VERSION 5.8 ;
BUSBITCHARS "[]" ;
DIVIDERCHAR "/" ;
UNITS
    DATABASE MICRONS 1000 ;
END UNITS

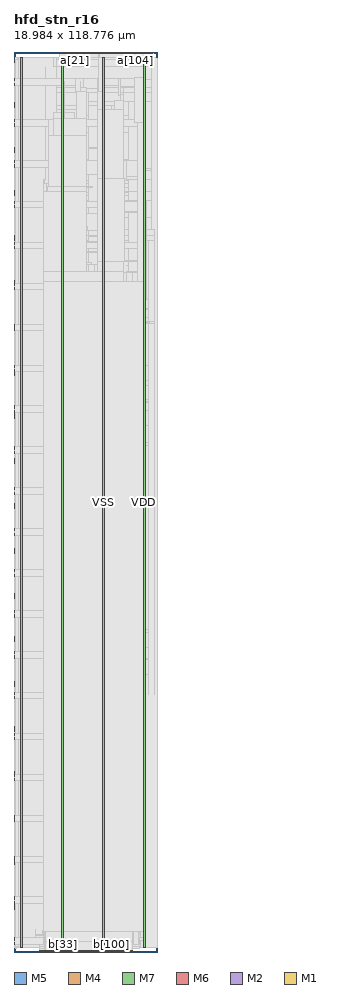
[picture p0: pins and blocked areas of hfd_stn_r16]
MACRO hfd_stn_r16
  FOREIGN hfd_stn_r16 0 0 ;
  CLASS BLOCK ;
  SIZE 18.984 BY 118.776 ;
  PIN a[0]
    DIRECTION INPUT ;
    USE SIGNAL ;
    PORT
      LAYER M5 ;
        RECT  6 118.584 6.024 118.776 ;
    END
  END a[0]
  PIN a[100]
    DIRECTION INPUT ;
    USE SIGNAL ;
    PORT
      LAYER M5 ;
        RECT  15.6 118.584 15.624 118.776 ;
    END
  END a[100]
  PIN a[101]
    DIRECTION INPUT ;
    USE SIGNAL ;
    PORT
      LAYER M5 ;
        RECT  15.696 118.584 15.72 118.776 ;
    END
  END a[101]
  PIN a[102]
    DIRECTION INPUT ;
    USE SIGNAL ;
    PORT
      LAYER M5 ;
        RECT  15.792 118.584 15.816 118.776 ;
    END
  END a[102]
  PIN a[103]
    DIRECTION INPUT ;
    USE SIGNAL ;
    PORT
      LAYER M5 ;
        RECT  15.888 118.584 15.912 118.776 ;
    END
  END a[103]
  PIN a[104]
    DIRECTION INPUT ;
    USE SIGNAL ;
    PORT
      LAYER M5 ;
        RECT  15.984 118.584 16.008 118.776 ;
    END
  END a[104]
  PIN a[105]
    DIRECTION INPUT ;
    USE SIGNAL ;
    PORT
      LAYER M5 ;
        RECT  16.08 118.584 16.104 118.776 ;
    END
  END a[105]
  PIN a[106]
    DIRECTION INPUT ;
    USE SIGNAL ;
    PORT
      LAYER M5 ;
        RECT  16.176 118.584 16.2 118.776 ;
    END
  END a[106]
  PIN a[107]
    DIRECTION INPUT ;
    USE SIGNAL ;
    PORT
      LAYER M5 ;
        RECT  16.272 118.584 16.296 118.776 ;
    END
  END a[107]
  PIN a[108]
    DIRECTION INPUT ;
    USE SIGNAL ;
    PORT
      LAYER M5 ;
        RECT  16.368 118.584 16.392 118.776 ;
    END
  END a[108]
  PIN a[109]
    DIRECTION INPUT ;
    USE SIGNAL ;
    PORT
      LAYER M5 ;
        RECT  16.464 118.584 16.488 118.776 ;
    END
  END a[109]
  PIN a[10]
    DIRECTION INPUT ;
    USE SIGNAL ;
    PORT
      LAYER M5 ;
        RECT  6.96 118.584 6.984 118.776 ;
    END
  END a[10]
  PIN a[110]
    DIRECTION INPUT ;
    USE SIGNAL ;
    PORT
      LAYER M5 ;
        RECT  16.56 118.584 16.584 118.776 ;
    END
  END a[110]
  PIN a[111]
    DIRECTION INPUT ;
    USE SIGNAL ;
    PORT
      LAYER M5 ;
        RECT  16.656 118.584 16.68 118.776 ;
    END
  END a[111]
  PIN a[112]
    DIRECTION INPUT ;
    USE SIGNAL ;
    PORT
      LAYER M5 ;
        RECT  16.752 118.584 16.776 118.776 ;
    END
  END a[112]
  PIN a[113]
    DIRECTION INPUT ;
    USE SIGNAL ;
    PORT
      LAYER M5 ;
        RECT  16.848 118.584 16.872 118.776 ;
    END
  END a[113]
  PIN a[114]
    DIRECTION INPUT ;
    USE SIGNAL ;
    PORT
      LAYER M5 ;
        RECT  16.944 118.584 16.968 118.776 ;
    END
  END a[114]
  PIN a[115]
    DIRECTION INPUT ;
    USE SIGNAL ;
    PORT
      LAYER M5 ;
        RECT  17.04 118.584 17.064 118.776 ;
    END
  END a[115]
  PIN a[116]
    DIRECTION INPUT ;
    USE SIGNAL ;
    PORT
      LAYER M5 ;
        RECT  17.136 118.584 17.16 118.776 ;
    END
  END a[116]
  PIN a[117]
    DIRECTION INPUT ;
    USE SIGNAL ;
    PORT
      LAYER M5 ;
        RECT  17.232 118.584 17.256 118.776 ;
    END
  END a[117]
  PIN a[118]
    DIRECTION INPUT ;
    USE SIGNAL ;
    PORT
      LAYER M5 ;
        RECT  17.328 118.584 17.352 118.776 ;
    END
  END a[118]
  PIN a[119]
    DIRECTION INPUT ;
    USE SIGNAL ;
    PORT
      LAYER M5 ;
        RECT  17.424 118.584 17.448 118.776 ;
    END
  END a[119]
  PIN a[11]
    DIRECTION INPUT ;
    USE SIGNAL ;
    PORT
      LAYER M5 ;
        RECT  7.056 118.584 7.08 118.776 ;
    END
  END a[11]
  PIN a[120]
    DIRECTION INPUT ;
    USE SIGNAL ;
    PORT
      LAYER M5 ;
        RECT  17.52 118.584 17.544 118.776 ;
    END
  END a[120]
  PIN a[121]
    DIRECTION INPUT ;
    USE SIGNAL ;
    PORT
      LAYER M5 ;
        RECT  17.616 118.584 17.64 118.776 ;
    END
  END a[121]
  PIN a[122]
    DIRECTION INPUT ;
    USE SIGNAL ;
    PORT
      LAYER M5 ;
        RECT  17.712 118.584 17.736 118.776 ;
    END
  END a[122]
  PIN a[123]
    DIRECTION INPUT ;
    USE SIGNAL ;
    PORT
      LAYER M5 ;
        RECT  17.808 118.584 17.832 118.776 ;
    END
  END a[123]
  PIN a[124]
    DIRECTION INPUT ;
    USE SIGNAL ;
    PORT
      LAYER M5 ;
        RECT  17.904 118.584 17.928 118.776 ;
    END
  END a[124]
  PIN a[125]
    DIRECTION INPUT ;
    USE SIGNAL ;
    PORT
      LAYER M5 ;
        RECT  18 118.584 18.024 118.776 ;
    END
  END a[125]
  PIN a[126]
    DIRECTION INPUT ;
    USE SIGNAL ;
    PORT
      LAYER M5 ;
        RECT  18.096 118.584 18.12 118.776 ;
    END
  END a[126]
  PIN a[127]
    DIRECTION INPUT ;
    USE SIGNAL ;
    PORT
      LAYER M5 ;
        RECT  18.192 118.584 18.216 118.776 ;
    END
  END a[127]
  PIN a[128]
    DIRECTION INPUT ;
    USE SIGNAL ;
    PORT
      LAYER M5 ;
        RECT  18.288 118.584 18.312 118.776 ;
    END
  END a[128]
  PIN a[12]
    DIRECTION INPUT ;
    USE SIGNAL ;
    PORT
      LAYER M5 ;
        RECT  7.152 118.584 7.176 118.776 ;
    END
  END a[12]
  PIN a[13]
    DIRECTION INPUT ;
    USE SIGNAL ;
    PORT
      LAYER M5 ;
        RECT  7.248 118.584 7.272 118.776 ;
    END
  END a[13]
  PIN a[14]
    DIRECTION INPUT ;
    USE SIGNAL ;
    PORT
      LAYER M5 ;
        RECT  7.344 118.584 7.368 118.776 ;
    END
  END a[14]
  PIN a[15]
    DIRECTION INPUT ;
    USE SIGNAL ;
    PORT
      LAYER M5 ;
        RECT  7.44 118.584 7.464 118.776 ;
    END
  END a[15]
  PIN a[16]
    DIRECTION INPUT ;
    USE SIGNAL ;
    PORT
      LAYER M5 ;
        RECT  7.536 118.584 7.56 118.776 ;
    END
  END a[16]
  PIN a[17]
    DIRECTION INPUT ;
    USE SIGNAL ;
    PORT
      LAYER M5 ;
        RECT  7.632 118.584 7.656 118.776 ;
    END
  END a[17]
  PIN a[18]
    DIRECTION INPUT ;
    USE SIGNAL ;
    PORT
      LAYER M5 ;
        RECT  7.728 118.584 7.752 118.776 ;
    END
  END a[18]
  PIN a[19]
    DIRECTION INPUT ;
    USE SIGNAL ;
    PORT
      LAYER M5 ;
        RECT  7.824 118.584 7.848 118.776 ;
    END
  END a[19]
  PIN a[1]
    DIRECTION INPUT ;
    USE SIGNAL ;
    PORT
      LAYER M5 ;
        RECT  6.096 118.584 6.12 118.776 ;
    END
  END a[1]
  PIN a[20]
    DIRECTION INPUT ;
    USE SIGNAL ;
    PORT
      LAYER M5 ;
        RECT  7.92 118.584 7.944 118.776 ;
    END
  END a[20]
  PIN a[21]
    DIRECTION INPUT ;
    USE SIGNAL ;
    PORT
      LAYER M5 ;
        RECT  8.016 118.584 8.04 118.776 ;
    END
  END a[21]
  PIN a[22]
    DIRECTION INPUT ;
    USE SIGNAL ;
    PORT
      LAYER M5 ;
        RECT  8.112 118.584 8.136 118.776 ;
    END
  END a[22]
  PIN a[23]
    DIRECTION INPUT ;
    USE SIGNAL ;
    PORT
      LAYER M5 ;
        RECT  8.208 118.584 8.232 118.776 ;
    END
  END a[23]
  PIN a[24]
    DIRECTION INPUT ;
    USE SIGNAL ;
    PORT
      LAYER M5 ;
        RECT  8.304 118.584 8.328 118.776 ;
    END
  END a[24]
  PIN a[25]
    DIRECTION INPUT ;
    USE SIGNAL ;
    PORT
      LAYER M5 ;
        RECT  8.4 118.584 8.424 118.776 ;
    END
  END a[25]
  PIN a[26]
    DIRECTION INPUT ;
    USE SIGNAL ;
    PORT
      LAYER M5 ;
        RECT  8.496 118.584 8.52 118.776 ;
    END
  END a[26]
  PIN a[27]
    DIRECTION INPUT ;
    USE SIGNAL ;
    PORT
      LAYER M5 ;
        RECT  8.592 118.584 8.616 118.776 ;
    END
  END a[27]
  PIN a[28]
    DIRECTION INPUT ;
    USE SIGNAL ;
    PORT
      LAYER M5 ;
        RECT  8.688 118.584 8.712 118.776 ;
    END
  END a[28]
  PIN a[29]
    DIRECTION INPUT ;
    USE SIGNAL ;
    PORT
      LAYER M5 ;
        RECT  8.784 118.584 8.808 118.776 ;
    END
  END a[29]
  PIN a[2]
    DIRECTION INPUT ;
    USE SIGNAL ;
    PORT
      LAYER M5 ;
        RECT  6.192 118.584 6.216 118.776 ;
    END
  END a[2]
  PIN a[30]
    DIRECTION INPUT ;
    USE SIGNAL ;
    PORT
      LAYER M5 ;
        RECT  8.88 118.584 8.904 118.776 ;
    END
  END a[30]
  PIN a[31]
    DIRECTION INPUT ;
    USE SIGNAL ;
    PORT
      LAYER M5 ;
        RECT  8.976 118.584 9 118.776 ;
    END
  END a[31]
  PIN a[32]
    DIRECTION INPUT ;
    USE SIGNAL ;
    PORT
      LAYER M5 ;
        RECT  9.072 118.584 9.096 118.776 ;
    END
  END a[32]
  PIN a[33]
    DIRECTION INPUT ;
    USE SIGNAL ;
    PORT
      LAYER M5 ;
        RECT  9.168 118.584 9.192 118.776 ;
    END
  END a[33]
  PIN a[34]
    DIRECTION INPUT ;
    USE SIGNAL ;
    PORT
      LAYER M5 ;
        RECT  9.264 118.584 9.288 118.776 ;
    END
  END a[34]
  PIN a[35]
    DIRECTION INPUT ;
    USE SIGNAL ;
    PORT
      LAYER M5 ;
        RECT  9.36 118.584 9.384 118.776 ;
    END
  END a[35]
  PIN a[36]
    DIRECTION INPUT ;
    USE SIGNAL ;
    PORT
      LAYER M5 ;
        RECT  9.456 118.584 9.48 118.776 ;
    END
  END a[36]
  PIN a[37]
    DIRECTION INPUT ;
    USE SIGNAL ;
    PORT
      LAYER M5 ;
        RECT  9.552 118.584 9.576 118.776 ;
    END
  END a[37]
  PIN a[38]
    DIRECTION INPUT ;
    USE SIGNAL ;
    PORT
      LAYER M5 ;
        RECT  9.648 118.584 9.672 118.776 ;
    END
  END a[38]
  PIN a[39]
    DIRECTION INPUT ;
    USE SIGNAL ;
    PORT
      LAYER M5 ;
        RECT  9.744 118.584 9.768 118.776 ;
    END
  END a[39]
  PIN a[3]
    DIRECTION INPUT ;
    USE SIGNAL ;
    PORT
      LAYER M5 ;
        RECT  6.288 118.584 6.312 118.776 ;
    END
  END a[3]
  PIN a[40]
    DIRECTION INPUT ;
    USE SIGNAL ;
    PORT
      LAYER M5 ;
        RECT  9.84 118.584 9.864 118.776 ;
    END
  END a[40]
  PIN a[41]
    DIRECTION INPUT ;
    USE SIGNAL ;
    PORT
      LAYER M5 ;
        RECT  9.936 118.584 9.96 118.776 ;
    END
  END a[41]
  PIN a[42]
    DIRECTION INPUT ;
    USE SIGNAL ;
    PORT
      LAYER M5 ;
        RECT  10.032 118.584 10.056 118.776 ;
    END
  END a[42]
  PIN a[43]
    DIRECTION INPUT ;
    USE SIGNAL ;
    PORT
      LAYER M5 ;
        RECT  10.128 118.584 10.152 118.776 ;
    END
  END a[43]
  PIN a[44]
    DIRECTION INPUT ;
    USE SIGNAL ;
    PORT
      LAYER M5 ;
        RECT  10.224 118.584 10.248 118.776 ;
    END
  END a[44]
  PIN a[45]
    DIRECTION INPUT ;
    USE SIGNAL ;
    PORT
      LAYER M5 ;
        RECT  10.32 118.584 10.344 118.776 ;
    END
  END a[45]
  PIN a[46]
    DIRECTION INPUT ;
    USE SIGNAL ;
    PORT
      LAYER M5 ;
        RECT  10.416 118.584 10.44 118.776 ;
    END
  END a[46]
  PIN a[47]
    DIRECTION INPUT ;
    USE SIGNAL ;
    PORT
      LAYER M5 ;
        RECT  10.512 118.584 10.536 118.776 ;
    END
  END a[47]
  PIN a[48]
    DIRECTION INPUT ;
    USE SIGNAL ;
    PORT
      LAYER M5 ;
        RECT  10.608 118.584 10.632 118.776 ;
    END
  END a[48]
  PIN a[49]
    DIRECTION INPUT ;
    USE SIGNAL ;
    PORT
      LAYER M5 ;
        RECT  10.704 118.584 10.728 118.776 ;
    END
  END a[49]
  PIN a[4]
    DIRECTION INPUT ;
    USE SIGNAL ;
    PORT
      LAYER M5 ;
        RECT  6.384 118.584 6.408 118.776 ;
    END
  END a[4]
  PIN a[50]
    DIRECTION INPUT ;
    USE SIGNAL ;
    PORT
      LAYER M5 ;
        RECT  10.8 118.584 10.824 118.776 ;
    END
  END a[50]
  PIN a[51]
    DIRECTION INPUT ;
    USE SIGNAL ;
    PORT
      LAYER M5 ;
        RECT  10.896 118.584 10.92 118.776 ;
    END
  END a[51]
  PIN a[52]
    DIRECTION INPUT ;
    USE SIGNAL ;
    PORT
      LAYER M5 ;
        RECT  10.992 118.584 11.016 118.776 ;
    END
  END a[52]
  PIN a[53]
    DIRECTION INPUT ;
    USE SIGNAL ;
    PORT
      LAYER M5 ;
        RECT  11.088 118.584 11.112 118.776 ;
    END
  END a[53]
  PIN a[54]
    DIRECTION INPUT ;
    USE SIGNAL ;
    PORT
      LAYER M5 ;
        RECT  11.184 118.584 11.208 118.776 ;
    END
  END a[54]
  PIN a[55]
    DIRECTION INPUT ;
    USE SIGNAL ;
    PORT
      LAYER M5 ;
        RECT  11.28 118.584 11.304 118.776 ;
    END
  END a[55]
  PIN a[56]
    DIRECTION INPUT ;
    USE SIGNAL ;
    PORT
      LAYER M5 ;
        RECT  11.376 118.584 11.4 118.776 ;
    END
  END a[56]
  PIN a[57]
    DIRECTION INPUT ;
    USE SIGNAL ;
    PORT
      LAYER M5 ;
        RECT  11.472 118.584 11.496 118.776 ;
    END
  END a[57]
  PIN a[58]
    DIRECTION INPUT ;
    USE SIGNAL ;
    PORT
      LAYER M5 ;
        RECT  11.568 118.584 11.592 118.776 ;
    END
  END a[58]
  PIN a[59]
    DIRECTION INPUT ;
    USE SIGNAL ;
    PORT
      LAYER M5 ;
        RECT  11.664 118.584 11.688 118.776 ;
    END
  END a[59]
  PIN a[5]
    DIRECTION INPUT ;
    USE SIGNAL ;
    PORT
      LAYER M5 ;
        RECT  6.48 118.584 6.504 118.776 ;
    END
  END a[5]
  PIN a[60]
    DIRECTION INPUT ;
    USE SIGNAL ;
    PORT
      LAYER M5 ;
        RECT  11.76 118.584 11.784 118.776 ;
    END
  END a[60]
  PIN a[61]
    DIRECTION INPUT ;
    USE SIGNAL ;
    PORT
      LAYER M5 ;
        RECT  11.856 118.584 11.88 118.776 ;
    END
  END a[61]
  PIN a[62]
    DIRECTION INPUT ;
    USE SIGNAL ;
    PORT
      LAYER M5 ;
        RECT  11.952 118.584 11.976 118.776 ;
    END
  END a[62]
  PIN a[63]
    DIRECTION INPUT ;
    USE SIGNAL ;
    PORT
      LAYER M5 ;
        RECT  12.048 118.584 12.072 118.776 ;
    END
  END a[63]
  PIN a[64]
    DIRECTION INPUT ;
    USE SIGNAL ;
    PORT
      LAYER M5 ;
        RECT  12.144 118.584 12.168 118.776 ;
    END
  END a[64]
  PIN a[65]
    DIRECTION INPUT ;
    USE SIGNAL ;
    PORT
      LAYER M5 ;
        RECT  12.24 118.584 12.264 118.776 ;
    END
  END a[65]
  PIN a[66]
    DIRECTION INPUT ;
    USE SIGNAL ;
    PORT
      LAYER M5 ;
        RECT  12.336 118.584 12.36 118.776 ;
    END
  END a[66]
  PIN a[67]
    DIRECTION INPUT ;
    USE SIGNAL ;
    PORT
      LAYER M5 ;
        RECT  12.432 118.584 12.456 118.776 ;
    END
  END a[67]
  PIN a[68]
    DIRECTION INPUT ;
    USE SIGNAL ;
    PORT
      LAYER M5 ;
        RECT  12.528 118.584 12.552 118.776 ;
    END
  END a[68]
  PIN a[69]
    DIRECTION INPUT ;
    USE SIGNAL ;
    PORT
      LAYER M5 ;
        RECT  12.624 118.584 12.648 118.776 ;
    END
  END a[69]
  PIN a[6]
    DIRECTION INPUT ;
    USE SIGNAL ;
    PORT
      LAYER M5 ;
        RECT  6.576 118.584 6.6 118.776 ;
    END
  END a[6]
  PIN a[70]
    DIRECTION INPUT ;
    USE SIGNAL ;
    PORT
      LAYER M5 ;
        RECT  12.72 118.584 12.744 118.776 ;
    END
  END a[70]
  PIN a[71]
    DIRECTION INPUT ;
    USE SIGNAL ;
    PORT
      LAYER M5 ;
        RECT  12.816 118.584 12.84 118.776 ;
    END
  END a[71]
  PIN a[72]
    DIRECTION INPUT ;
    USE SIGNAL ;
    PORT
      LAYER M5 ;
        RECT  12.912 118.584 12.936 118.776 ;
    END
  END a[72]
  PIN a[73]
    DIRECTION INPUT ;
    USE SIGNAL ;
    PORT
      LAYER M5 ;
        RECT  13.008 118.584 13.032 118.776 ;
    END
  END a[73]
  PIN a[74]
    DIRECTION INPUT ;
    USE SIGNAL ;
    PORT
      LAYER M5 ;
        RECT  13.104 118.584 13.128 118.776 ;
    END
  END a[74]
  PIN a[75]
    DIRECTION INPUT ;
    USE SIGNAL ;
    PORT
      LAYER M5 ;
        RECT  13.2 118.584 13.224 118.776 ;
    END
  END a[75]
  PIN a[76]
    DIRECTION INPUT ;
    USE SIGNAL ;
    PORT
      LAYER M5 ;
        RECT  13.296 118.584 13.32 118.776 ;
    END
  END a[76]
  PIN a[77]
    DIRECTION INPUT ;
    USE SIGNAL ;
    PORT
      LAYER M5 ;
        RECT  13.392 118.584 13.416 118.776 ;
    END
  END a[77]
  PIN a[78]
    DIRECTION INPUT ;
    USE SIGNAL ;
    PORT
      LAYER M5 ;
        RECT  13.488 118.584 13.512 118.776 ;
    END
  END a[78]
  PIN a[79]
    DIRECTION INPUT ;
    USE SIGNAL ;
    PORT
      LAYER M5 ;
        RECT  13.584 118.584 13.608 118.776 ;
    END
  END a[79]
  PIN a[7]
    DIRECTION INPUT ;
    USE SIGNAL ;
    PORT
      LAYER M5 ;
        RECT  6.672 118.584 6.696 118.776 ;
    END
  END a[7]
  PIN a[80]
    DIRECTION INPUT ;
    USE SIGNAL ;
    PORT
      LAYER M5 ;
        RECT  13.68 118.584 13.704 118.776 ;
    END
  END a[80]
  PIN a[81]
    DIRECTION INPUT ;
    USE SIGNAL ;
    PORT
      LAYER M5 ;
        RECT  13.776 118.584 13.8 118.776 ;
    END
  END a[81]
  PIN a[82]
    DIRECTION INPUT ;
    USE SIGNAL ;
    PORT
      LAYER M5 ;
        RECT  13.872 118.584 13.896 118.776 ;
    END
  END a[82]
  PIN a[83]
    DIRECTION INPUT ;
    USE SIGNAL ;
    PORT
      LAYER M5 ;
        RECT  13.968 118.584 13.992 118.776 ;
    END
  END a[83]
  PIN a[84]
    DIRECTION INPUT ;
    USE SIGNAL ;
    PORT
      LAYER M5 ;
        RECT  14.064 118.584 14.088 118.776 ;
    END
  END a[84]
  PIN a[85]
    DIRECTION INPUT ;
    USE SIGNAL ;
    PORT
      LAYER M5 ;
        RECT  14.16 118.584 14.184 118.776 ;
    END
  END a[85]
  PIN a[86]
    DIRECTION INPUT ;
    USE SIGNAL ;
    PORT
      LAYER M5 ;
        RECT  14.256 118.584 14.28 118.776 ;
    END
  END a[86]
  PIN a[87]
    DIRECTION INPUT ;
    USE SIGNAL ;
    PORT
      LAYER M5 ;
        RECT  14.352 118.584 14.376 118.776 ;
    END
  END a[87]
  PIN a[88]
    DIRECTION INPUT ;
    USE SIGNAL ;
    PORT
      LAYER M5 ;
        RECT  14.448 118.584 14.472 118.776 ;
    END
  END a[88]
  PIN a[89]
    DIRECTION INPUT ;
    USE SIGNAL ;
    PORT
      LAYER M5 ;
        RECT  14.544 118.584 14.568 118.776 ;
    END
  END a[89]
  PIN a[8]
    DIRECTION INPUT ;
    USE SIGNAL ;
    PORT
      LAYER M5 ;
        RECT  6.768 118.584 6.792 118.776 ;
    END
  END a[8]
  PIN a[90]
    DIRECTION INPUT ;
    USE SIGNAL ;
    PORT
      LAYER M5 ;
        RECT  14.64 118.584 14.664 118.776 ;
    END
  END a[90]
  PIN a[91]
    DIRECTION INPUT ;
    USE SIGNAL ;
    PORT
      LAYER M5 ;
        RECT  14.736 118.584 14.76 118.776 ;
    END
  END a[91]
  PIN a[92]
    DIRECTION INPUT ;
    USE SIGNAL ;
    PORT
      LAYER M5 ;
        RECT  14.832 118.584 14.856 118.776 ;
    END
  END a[92]
  PIN a[93]
    DIRECTION INPUT ;
    USE SIGNAL ;
    PORT
      LAYER M5 ;
        RECT  14.928 118.584 14.952 118.776 ;
    END
  END a[93]
  PIN a[94]
    DIRECTION INPUT ;
    USE SIGNAL ;
    PORT
      LAYER M5 ;
        RECT  15.024 118.584 15.048 118.776 ;
    END
  END a[94]
  PIN a[95]
    DIRECTION INPUT ;
    USE SIGNAL ;
    PORT
      LAYER M5 ;
        RECT  15.12 118.584 15.144 118.776 ;
    END
  END a[95]
  PIN a[96]
    DIRECTION INPUT ;
    USE SIGNAL ;
    PORT
      LAYER M5 ;
        RECT  15.216 118.584 15.24 118.776 ;
    END
  END a[96]
  PIN a[97]
    DIRECTION INPUT ;
    USE SIGNAL ;
    PORT
      LAYER M5 ;
        RECT  15.312 118.584 15.336 118.776 ;
    END
  END a[97]
  PIN a[98]
    DIRECTION INPUT ;
    USE SIGNAL ;
    PORT
      LAYER M5 ;
        RECT  15.408 118.584 15.432 118.776 ;
    END
  END a[98]
  PIN a[99]
    DIRECTION INPUT ;
    USE SIGNAL ;
    PORT
      LAYER M5 ;
        RECT  15.504 118.584 15.528 118.776 ;
    END
  END a[99]
  PIN a[9]
    DIRECTION INPUT ;
    USE SIGNAL ;
    PORT
      LAYER M5 ;
        RECT  6.864 118.584 6.888 118.776 ;
    END
  END a[9]
  PIN b[0]
    DIRECTION OUTPUT ;
    USE SIGNAL ;
    PORT
      LAYER M5 ;
        RECT  3.312 0 3.336 0.192 ;
    END
  END b[0]
  PIN b[100]
    DIRECTION OUTPUT ;
    USE SIGNAL ;
    PORT
      LAYER M5 ;
        RECT  12.912 0 12.936 0.192 ;
    END
  END b[100]
  PIN b[101]
    DIRECTION OUTPUT ;
    USE SIGNAL ;
    PORT
      LAYER M5 ;
        RECT  13.008 0 13.032 0.192 ;
    END
  END b[101]
  PIN b[102]
    DIRECTION OUTPUT ;
    USE SIGNAL ;
    PORT
      LAYER M5 ;
        RECT  13.104 0 13.128 0.192 ;
    END
  END b[102]
  PIN b[103]
    DIRECTION OUTPUT ;
    USE SIGNAL ;
    PORT
      LAYER M5 ;
        RECT  13.2 0 13.224 0.192 ;
    END
  END b[103]
  PIN b[104]
    DIRECTION OUTPUT ;
    USE SIGNAL ;
    PORT
      LAYER M5 ;
        RECT  13.296 0 13.32 0.192 ;
    END
  END b[104]
  PIN b[105]
    DIRECTION OUTPUT ;
    USE SIGNAL ;
    PORT
      LAYER M5 ;
        RECT  13.392 0 13.416 0.192 ;
    END
  END b[105]
  PIN b[106]
    DIRECTION OUTPUT ;
    USE SIGNAL ;
    PORT
      LAYER M5 ;
        RECT  13.488 0 13.512 0.192 ;
    END
  END b[106]
  PIN b[107]
    DIRECTION OUTPUT ;
    USE SIGNAL ;
    PORT
      LAYER M5 ;
        RECT  13.584 0 13.608 0.192 ;
    END
  END b[107]
  PIN b[108]
    DIRECTION OUTPUT ;
    USE SIGNAL ;
    PORT
      LAYER M5 ;
        RECT  13.68 0 13.704 0.192 ;
    END
  END b[108]
  PIN b[109]
    DIRECTION OUTPUT ;
    USE SIGNAL ;
    PORT
      LAYER M5 ;
        RECT  13.776 0 13.8 0.192 ;
    END
  END b[109]
  PIN b[10]
    DIRECTION OUTPUT ;
    USE SIGNAL ;
    PORT
      LAYER M5 ;
        RECT  4.272 0 4.296 0.192 ;
    END
  END b[10]
  PIN b[110]
    DIRECTION OUTPUT ;
    USE SIGNAL ;
    PORT
      LAYER M5 ;
        RECT  13.872 0 13.896 0.192 ;
    END
  END b[110]
  PIN b[111]
    DIRECTION OUTPUT ;
    USE SIGNAL ;
    PORT
      LAYER M5 ;
        RECT  13.968 0 13.992 0.192 ;
    END
  END b[111]
  PIN b[112]
    DIRECTION OUTPUT ;
    USE SIGNAL ;
    PORT
      LAYER M5 ;
        RECT  14.064 0 14.088 0.192 ;
    END
  END b[112]
  PIN b[113]
    DIRECTION OUTPUT ;
    USE SIGNAL ;
    PORT
      LAYER M5 ;
        RECT  14.16 0 14.184 0.192 ;
    END
  END b[113]
  PIN b[114]
    DIRECTION OUTPUT ;
    USE SIGNAL ;
    PORT
      LAYER M5 ;
        RECT  14.256 0 14.28 0.192 ;
    END
  END b[114]
  PIN b[115]
    DIRECTION OUTPUT ;
    USE SIGNAL ;
    PORT
      LAYER M5 ;
        RECT  14.352 0 14.376 0.192 ;
    END
  END b[115]
  PIN b[116]
    DIRECTION OUTPUT ;
    USE SIGNAL ;
    PORT
      LAYER M5 ;
        RECT  14.448 0 14.472 0.192 ;
    END
  END b[116]
  PIN b[117]
    DIRECTION OUTPUT ;
    USE SIGNAL ;
    PORT
      LAYER M5 ;
        RECT  14.544 0 14.568 0.192 ;
    END
  END b[117]
  PIN b[118]
    DIRECTION OUTPUT ;
    USE SIGNAL ;
    PORT
      LAYER M5 ;
        RECT  14.64 0 14.664 0.192 ;
    END
  END b[118]
  PIN b[119]
    DIRECTION OUTPUT ;
    USE SIGNAL ;
    PORT
      LAYER M5 ;
        RECT  14.736 0 14.76 0.192 ;
    END
  END b[119]
  PIN b[11]
    DIRECTION OUTPUT ;
    USE SIGNAL ;
    PORT
      LAYER M5 ;
        RECT  4.368 0 4.392 0.192 ;
    END
  END b[11]
  PIN b[120]
    DIRECTION OUTPUT ;
    USE SIGNAL ;
    PORT
      LAYER M5 ;
        RECT  14.832 0 14.856 0.192 ;
    END
  END b[120]
  PIN b[121]
    DIRECTION OUTPUT ;
    USE SIGNAL ;
    PORT
      LAYER M5 ;
        RECT  14.928 0 14.952 0.192 ;
    END
  END b[121]
  PIN b[122]
    DIRECTION OUTPUT ;
    USE SIGNAL ;
    PORT
      LAYER M5 ;
        RECT  15.024 0 15.048 0.192 ;
    END
  END b[122]
  PIN b[123]
    DIRECTION OUTPUT ;
    USE SIGNAL ;
    PORT
      LAYER M5 ;
        RECT  15.12 0 15.144 0.192 ;
    END
  END b[123]
  PIN b[124]
    DIRECTION OUTPUT ;
    USE SIGNAL ;
    PORT
      LAYER M5 ;
        RECT  15.216 0 15.24 0.192 ;
    END
  END b[124]
  PIN b[125]
    DIRECTION OUTPUT ;
    USE SIGNAL ;
    PORT
      LAYER M5 ;
        RECT  15.312 0 15.336 0.192 ;
    END
  END b[125]
  PIN b[126]
    DIRECTION OUTPUT ;
    USE SIGNAL ;
    PORT
      LAYER M5 ;
        RECT  15.408 0 15.432 0.192 ;
    END
  END b[126]
  PIN b[127]
    DIRECTION OUTPUT ;
    USE SIGNAL ;
    PORT
      LAYER M5 ;
        RECT  15.504 0 15.528 0.192 ;
    END
  END b[127]
  PIN b[128]
    DIRECTION OUTPUT ;
    USE SIGNAL ;
    PORT
      LAYER M5 ;
        RECT  15.6 0 15.624 0.192 ;
    END
  END b[128]
  PIN b[12]
    DIRECTION OUTPUT ;
    USE SIGNAL ;
    PORT
      LAYER M5 ;
        RECT  4.464 0 4.488 0.192 ;
    END
  END b[12]
  PIN b[13]
    DIRECTION OUTPUT ;
    USE SIGNAL ;
    PORT
      LAYER M5 ;
        RECT  4.56 0 4.584 0.192 ;
    END
  END b[13]
  PIN b[14]
    DIRECTION OUTPUT ;
    USE SIGNAL ;
    PORT
      LAYER M5 ;
        RECT  4.656 0 4.68 0.192 ;
    END
  END b[14]
  PIN b[15]
    DIRECTION OUTPUT ;
    USE SIGNAL ;
    PORT
      LAYER M5 ;
        RECT  4.752 0 4.776 0.192 ;
    END
  END b[15]
  PIN b[16]
    DIRECTION OUTPUT ;
    USE SIGNAL ;
    PORT
      LAYER M5 ;
        RECT  4.848 0 4.872 0.192 ;
    END
  END b[16]
  PIN b[17]
    DIRECTION OUTPUT ;
    USE SIGNAL ;
    PORT
      LAYER M5 ;
        RECT  4.944 0 4.968 0.192 ;
    END
  END b[17]
  PIN b[18]
    DIRECTION OUTPUT ;
    USE SIGNAL ;
    PORT
      LAYER M5 ;
        RECT  5.04 0 5.064 0.192 ;
    END
  END b[18]
  PIN b[19]
    DIRECTION OUTPUT ;
    USE SIGNAL ;
    PORT
      LAYER M5 ;
        RECT  5.136 0 5.16 0.192 ;
    END
  END b[19]
  PIN b[1]
    DIRECTION OUTPUT ;
    USE SIGNAL ;
    PORT
      LAYER M5 ;
        RECT  3.408 0 3.432 0.192 ;
    END
  END b[1]
  PIN b[20]
    DIRECTION OUTPUT ;
    USE SIGNAL ;
    PORT
      LAYER M5 ;
        RECT  5.232 0 5.256 0.192 ;
    END
  END b[20]
  PIN b[21]
    DIRECTION OUTPUT ;
    USE SIGNAL ;
    PORT
      LAYER M5 ;
        RECT  5.328 0 5.352 0.192 ;
    END
  END b[21]
  PIN b[22]
    DIRECTION OUTPUT ;
    USE SIGNAL ;
    PORT
      LAYER M5 ;
        RECT  5.424 0 5.448 0.192 ;
    END
  END b[22]
  PIN b[23]
    DIRECTION OUTPUT ;
    USE SIGNAL ;
    PORT
      LAYER M5 ;
        RECT  5.52 0 5.544 0.192 ;
    END
  END b[23]
  PIN b[24]
    DIRECTION OUTPUT ;
    USE SIGNAL ;
    PORT
      LAYER M5 ;
        RECT  5.616 0 5.64 0.192 ;
    END
  END b[24]
  PIN b[25]
    DIRECTION OUTPUT ;
    USE SIGNAL ;
    PORT
      LAYER M5 ;
        RECT  5.712 0 5.736 0.192 ;
    END
  END b[25]
  PIN b[26]
    DIRECTION OUTPUT ;
    USE SIGNAL ;
    PORT
      LAYER M5 ;
        RECT  5.808 0 5.832 0.192 ;
    END
  END b[26]
  PIN b[27]
    DIRECTION OUTPUT ;
    USE SIGNAL ;
    PORT
      LAYER M5 ;
        RECT  5.904 0 5.928 0.192 ;
    END
  END b[27]
  PIN b[28]
    DIRECTION OUTPUT ;
    USE SIGNAL ;
    PORT
      LAYER M5 ;
        RECT  6 0 6.024 0.192 ;
    END
  END b[28]
  PIN b[29]
    DIRECTION OUTPUT ;
    USE SIGNAL ;
    PORT
      LAYER M5 ;
        RECT  6.096 0 6.12 0.192 ;
    END
  END b[29]
  PIN b[2]
    DIRECTION OUTPUT ;
    USE SIGNAL ;
    PORT
      LAYER M5 ;
        RECT  3.504 0 3.528 0.192 ;
    END
  END b[2]
  PIN b[30]
    DIRECTION OUTPUT ;
    USE SIGNAL ;
    PORT
      LAYER M5 ;
        RECT  6.192 0 6.216 0.192 ;
    END
  END b[30]
  PIN b[31]
    DIRECTION OUTPUT ;
    USE SIGNAL ;
    PORT
      LAYER M5 ;
        RECT  6.288 0 6.312 0.192 ;
    END
  END b[31]
  PIN b[32]
    DIRECTION OUTPUT ;
    USE SIGNAL ;
    PORT
      LAYER M5 ;
        RECT  6.384 0 6.408 0.192 ;
    END
  END b[32]
  PIN b[33]
    DIRECTION OUTPUT ;
    USE SIGNAL ;
    PORT
      LAYER M5 ;
        RECT  6.48 0 6.504 0.192 ;
    END
  END b[33]
  PIN b[34]
    DIRECTION OUTPUT ;
    USE SIGNAL ;
    PORT
      LAYER M5 ;
        RECT  6.576 0 6.6 0.192 ;
    END
  END b[34]
  PIN b[35]
    DIRECTION OUTPUT ;
    USE SIGNAL ;
    PORT
      LAYER M5 ;
        RECT  6.672 0 6.696 0.192 ;
    END
  END b[35]
  PIN b[36]
    DIRECTION OUTPUT ;
    USE SIGNAL ;
    PORT
      LAYER M5 ;
        RECT  6.768 0 6.792 0.192 ;
    END
  END b[36]
  PIN b[37]
    DIRECTION OUTPUT ;
    USE SIGNAL ;
    PORT
      LAYER M5 ;
        RECT  6.864 0 6.888 0.192 ;
    END
  END b[37]
  PIN b[38]
    DIRECTION OUTPUT ;
    USE SIGNAL ;
    PORT
      LAYER M5 ;
        RECT  6.96 0 6.984 0.192 ;
    END
  END b[38]
  PIN b[39]
    DIRECTION OUTPUT ;
    USE SIGNAL ;
    PORT
      LAYER M5 ;
        RECT  7.056 0 7.08 0.192 ;
    END
  END b[39]
  PIN b[3]
    DIRECTION OUTPUT ;
    USE SIGNAL ;
    PORT
      LAYER M5 ;
        RECT  3.6 0 3.624 0.192 ;
    END
  END b[3]
  PIN b[40]
    DIRECTION OUTPUT ;
    USE SIGNAL ;
    PORT
      LAYER M5 ;
        RECT  7.152 0 7.176 0.192 ;
    END
  END b[40]
  PIN b[41]
    DIRECTION OUTPUT ;
    USE SIGNAL ;
    PORT
      LAYER M5 ;
        RECT  7.248 0 7.272 0.192 ;
    END
  END b[41]
  PIN b[42]
    DIRECTION OUTPUT ;
    USE SIGNAL ;
    PORT
      LAYER M5 ;
        RECT  7.344 0 7.368 0.192 ;
    END
  END b[42]
  PIN b[43]
    DIRECTION OUTPUT ;
    USE SIGNAL ;
    PORT
      LAYER M5 ;
        RECT  7.44 0 7.464 0.192 ;
    END
  END b[43]
  PIN b[44]
    DIRECTION OUTPUT ;
    USE SIGNAL ;
    PORT
      LAYER M5 ;
        RECT  7.536 0 7.56 0.192 ;
    END
  END b[44]
  PIN b[45]
    DIRECTION OUTPUT ;
    USE SIGNAL ;
    PORT
      LAYER M5 ;
        RECT  7.632 0 7.656 0.192 ;
    END
  END b[45]
  PIN b[46]
    DIRECTION OUTPUT ;
    USE SIGNAL ;
    PORT
      LAYER M5 ;
        RECT  7.728 0 7.752 0.192 ;
    END
  END b[46]
  PIN b[47]
    DIRECTION OUTPUT ;
    USE SIGNAL ;
    PORT
      LAYER M5 ;
        RECT  7.824 0 7.848 0.192 ;
    END
  END b[47]
  PIN b[48]
    DIRECTION OUTPUT ;
    USE SIGNAL ;
    PORT
      LAYER M5 ;
        RECT  7.92 0 7.944 0.192 ;
    END
  END b[48]
  PIN b[49]
    DIRECTION OUTPUT ;
    USE SIGNAL ;
    PORT
      LAYER M5 ;
        RECT  8.016 0 8.04 0.192 ;
    END
  END b[49]
  PIN b[4]
    DIRECTION OUTPUT ;
    USE SIGNAL ;
    PORT
      LAYER M5 ;
        RECT  3.696 0 3.72 0.192 ;
    END
  END b[4]
  PIN b[50]
    DIRECTION OUTPUT ;
    USE SIGNAL ;
    PORT
      LAYER M5 ;
        RECT  8.112 0 8.136 0.192 ;
    END
  END b[50]
  PIN b[51]
    DIRECTION OUTPUT ;
    USE SIGNAL ;
    PORT
      LAYER M5 ;
        RECT  8.208 0 8.232 0.192 ;
    END
  END b[51]
  PIN b[52]
    DIRECTION OUTPUT ;
    USE SIGNAL ;
    PORT
      LAYER M5 ;
        RECT  8.304 0 8.328 0.192 ;
    END
  END b[52]
  PIN b[53]
    DIRECTION OUTPUT ;
    USE SIGNAL ;
    PORT
      LAYER M5 ;
        RECT  8.4 0 8.424 0.192 ;
    END
  END b[53]
  PIN b[54]
    DIRECTION OUTPUT ;
    USE SIGNAL ;
    PORT
      LAYER M5 ;
        RECT  8.496 0 8.52 0.192 ;
    END
  END b[54]
  PIN b[55]
    DIRECTION OUTPUT ;
    USE SIGNAL ;
    PORT
      LAYER M5 ;
        RECT  8.592 0 8.616 0.192 ;
    END
  END b[55]
  PIN b[56]
    DIRECTION OUTPUT ;
    USE SIGNAL ;
    PORT
      LAYER M5 ;
        RECT  8.688 0 8.712 0.192 ;
    END
  END b[56]
  PIN b[57]
    DIRECTION OUTPUT ;
    USE SIGNAL ;
    PORT
      LAYER M5 ;
        RECT  8.784 0 8.808 0.192 ;
    END
  END b[57]
  PIN b[58]
    DIRECTION OUTPUT ;
    USE SIGNAL ;
    PORT
      LAYER M5 ;
        RECT  8.88 0 8.904 0.192 ;
    END
  END b[58]
  PIN b[59]
    DIRECTION OUTPUT ;
    USE SIGNAL ;
    PORT
      LAYER M5 ;
        RECT  8.976 0 9 0.192 ;
    END
  END b[59]
  PIN b[5]
    DIRECTION OUTPUT ;
    USE SIGNAL ;
    PORT
      LAYER M5 ;
        RECT  3.792 0 3.816 0.192 ;
    END
  END b[5]
  PIN b[60]
    DIRECTION OUTPUT ;
    USE SIGNAL ;
    PORT
      LAYER M5 ;
        RECT  9.072 0 9.096 0.192 ;
    END
  END b[60]
  PIN b[61]
    DIRECTION OUTPUT ;
    USE SIGNAL ;
    PORT
      LAYER M5 ;
        RECT  9.168 0 9.192 0.192 ;
    END
  END b[61]
  PIN b[62]
    DIRECTION OUTPUT ;
    USE SIGNAL ;
    PORT
      LAYER M5 ;
        RECT  9.264 0 9.288 0.192 ;
    END
  END b[62]
  PIN b[63]
    DIRECTION OUTPUT ;
    USE SIGNAL ;
    PORT
      LAYER M5 ;
        RECT  9.36 0 9.384 0.192 ;
    END
  END b[63]
  PIN b[64]
    DIRECTION OUTPUT ;
    USE SIGNAL ;
    PORT
      LAYER M5 ;
        RECT  9.456 0 9.48 0.192 ;
    END
  END b[64]
  PIN b[65]
    DIRECTION OUTPUT ;
    USE SIGNAL ;
    PORT
      LAYER M5 ;
        RECT  9.552 0 9.576 0.192 ;
    END
  END b[65]
  PIN b[66]
    DIRECTION OUTPUT ;
    USE SIGNAL ;
    PORT
      LAYER M5 ;
        RECT  9.648 0 9.672 0.192 ;
    END
  END b[66]
  PIN b[67]
    DIRECTION OUTPUT ;
    USE SIGNAL ;
    PORT
      LAYER M5 ;
        RECT  9.744 0 9.768 0.192 ;
    END
  END b[67]
  PIN b[68]
    DIRECTION OUTPUT ;
    USE SIGNAL ;
    PORT
      LAYER M5 ;
        RECT  9.84 0 9.864 0.192 ;
    END
  END b[68]
  PIN b[69]
    DIRECTION OUTPUT ;
    USE SIGNAL ;
    PORT
      LAYER M5 ;
        RECT  9.936 0 9.96 0.192 ;
    END
  END b[69]
  PIN b[6]
    DIRECTION OUTPUT ;
    USE SIGNAL ;
    PORT
      LAYER M5 ;
        RECT  3.888 0 3.912 0.192 ;
    END
  END b[6]
  PIN b[70]
    DIRECTION OUTPUT ;
    USE SIGNAL ;
    PORT
      LAYER M5 ;
        RECT  10.032 0 10.056 0.192 ;
    END
  END b[70]
  PIN b[71]
    DIRECTION OUTPUT ;
    USE SIGNAL ;
    PORT
      LAYER M5 ;
        RECT  10.128 0 10.152 0.192 ;
    END
  END b[71]
  PIN b[72]
    DIRECTION OUTPUT ;
    USE SIGNAL ;
    PORT
      LAYER M5 ;
        RECT  10.224 0 10.248 0.192 ;
    END
  END b[72]
  PIN b[73]
    DIRECTION OUTPUT ;
    USE SIGNAL ;
    PORT
      LAYER M5 ;
        RECT  10.32 0 10.344 0.192 ;
    END
  END b[73]
  PIN b[74]
    DIRECTION OUTPUT ;
    USE SIGNAL ;
    PORT
      LAYER M5 ;
        RECT  10.416 0 10.44 0.192 ;
    END
  END b[74]
  PIN b[75]
    DIRECTION OUTPUT ;
    USE SIGNAL ;
    PORT
      LAYER M5 ;
        RECT  10.512 0 10.536 0.192 ;
    END
  END b[75]
  PIN b[76]
    DIRECTION OUTPUT ;
    USE SIGNAL ;
    PORT
      LAYER M5 ;
        RECT  10.608 0 10.632 0.192 ;
    END
  END b[76]
  PIN b[77]
    DIRECTION OUTPUT ;
    USE SIGNAL ;
    PORT
      LAYER M5 ;
        RECT  10.704 0 10.728 0.192 ;
    END
  END b[77]
  PIN b[78]
    DIRECTION OUTPUT ;
    USE SIGNAL ;
    PORT
      LAYER M5 ;
        RECT  10.8 0 10.824 0.192 ;
    END
  END b[78]
  PIN b[79]
    DIRECTION OUTPUT ;
    USE SIGNAL ;
    PORT
      LAYER M5 ;
        RECT  10.896 0 10.92 0.192 ;
    END
  END b[79]
  PIN b[7]
    DIRECTION OUTPUT ;
    USE SIGNAL ;
    PORT
      LAYER M5 ;
        RECT  3.984 0 4.008 0.192 ;
    END
  END b[7]
  PIN b[80]
    DIRECTION OUTPUT ;
    USE SIGNAL ;
    PORT
      LAYER M5 ;
        RECT  10.992 0 11.016 0.192 ;
    END
  END b[80]
  PIN b[81]
    DIRECTION OUTPUT ;
    USE SIGNAL ;
    PORT
      LAYER M5 ;
        RECT  11.088 0 11.112 0.192 ;
    END
  END b[81]
  PIN b[82]
    DIRECTION OUTPUT ;
    USE SIGNAL ;
    PORT
      LAYER M5 ;
        RECT  11.184 0 11.208 0.192 ;
    END
  END b[82]
  PIN b[83]
    DIRECTION OUTPUT ;
    USE SIGNAL ;
    PORT
      LAYER M5 ;
        RECT  11.28 0 11.304 0.192 ;
    END
  END b[83]
  PIN b[84]
    DIRECTION OUTPUT ;
    USE SIGNAL ;
    PORT
      LAYER M5 ;
        RECT  11.376 0 11.4 0.192 ;
    END
  END b[84]
  PIN b[85]
    DIRECTION OUTPUT ;
    USE SIGNAL ;
    PORT
      LAYER M5 ;
        RECT  11.472 0 11.496 0.192 ;
    END
  END b[85]
  PIN b[86]
    DIRECTION OUTPUT ;
    USE SIGNAL ;
    PORT
      LAYER M5 ;
        RECT  11.568 0 11.592 0.192 ;
    END
  END b[86]
  PIN b[87]
    DIRECTION OUTPUT ;
    USE SIGNAL ;
    PORT
      LAYER M5 ;
        RECT  11.664 0 11.688 0.192 ;
    END
  END b[87]
  PIN b[88]
    DIRECTION OUTPUT ;
    USE SIGNAL ;
    PORT
      LAYER M5 ;
        RECT  11.76 0 11.784 0.192 ;
    END
  END b[88]
  PIN b[89]
    DIRECTION OUTPUT ;
    USE SIGNAL ;
    PORT
      LAYER M5 ;
        RECT  11.856 0 11.88 0.192 ;
    END
  END b[89]
  PIN b[8]
    DIRECTION OUTPUT ;
    USE SIGNAL ;
    PORT
      LAYER M5 ;
        RECT  4.08 0 4.104 0.192 ;
    END
  END b[8]
  PIN b[90]
    DIRECTION OUTPUT ;
    USE SIGNAL ;
    PORT
      LAYER M5 ;
        RECT  11.952 0 11.976 0.192 ;
    END
  END b[90]
  PIN b[91]
    DIRECTION OUTPUT ;
    USE SIGNAL ;
    PORT
      LAYER M5 ;
        RECT  12.048 0 12.072 0.192 ;
    END
  END b[91]
  PIN b[92]
    DIRECTION OUTPUT ;
    USE SIGNAL ;
    PORT
      LAYER M5 ;
        RECT  12.144 0 12.168 0.192 ;
    END
  END b[92]
  PIN b[93]
    DIRECTION OUTPUT ;
    USE SIGNAL ;
    PORT
      LAYER M5 ;
        RECT  12.24 0 12.264 0.192 ;
    END
  END b[93]
  PIN b[94]
    DIRECTION OUTPUT ;
    USE SIGNAL ;
    PORT
      LAYER M5 ;
        RECT  12.336 0 12.36 0.192 ;
    END
  END b[94]
  PIN b[95]
    DIRECTION OUTPUT ;
    USE SIGNAL ;
    PORT
      LAYER M5 ;
        RECT  12.432 0 12.456 0.192 ;
    END
  END b[95]
  PIN b[96]
    DIRECTION OUTPUT ;
    USE SIGNAL ;
    PORT
      LAYER M5 ;
        RECT  12.528 0 12.552 0.192 ;
    END
  END b[96]
  PIN b[97]
    DIRECTION OUTPUT ;
    USE SIGNAL ;
    PORT
      LAYER M5 ;
        RECT  12.624 0 12.648 0.192 ;
    END
  END b[97]
  PIN b[98]
    DIRECTION OUTPUT ;
    USE SIGNAL ;
    PORT
      LAYER M5 ;
        RECT  12.72 0 12.744 0.192 ;
    END
  END b[98]
  PIN b[99]
    DIRECTION OUTPUT ;
    USE SIGNAL ;
    PORT
      LAYER M5 ;
        RECT  12.816 0 12.84 0.192 ;
    END
  END b[99]
  PIN b[9]
    DIRECTION OUTPUT ;
    USE SIGNAL ;
    PORT
      LAYER M5 ;
        RECT  4.176 0 4.2 0.192 ;
    END
  END b[9]
  PIN rst[0]
    DIRECTION INPUT ;
    USE SIGNAL ;
    PORT
      LAYER M4 ;
        RECT  18.792 118.08 18.984 118.104 ;
    END
  END rst[0]
  PIN VDD
    DIRECTION INOUT ;
    USE POWER ;
    PORT
      LAYER M7 ;
        RECT  17.056 0.531 17.344 117.999 ;
        RECT  6.256 0.531 6.544 117.999 ;
      LAYER M6 ;
        RECT  0 114.972 0.032 115.26 ;
        RECT  0 109.572 0.032 109.86 ;
        RECT  0 104.172 0.032 104.46 ;
        RECT  0 98.772 0.032 99.06 ;
        RECT  0 93.372 0.032 93.66 ;
        RECT  0 87.972 0.032 88.26 ;
        RECT  0 82.572 0.032 82.86 ;
        RECT  0 77.172 0.032 77.46 ;
        RECT  0 71.772 0.032 72.06 ;
        RECT  0 66.372 0.032 66.66 ;
        RECT  0 60.972 0.032 61.26 ;
        RECT  0 55.572 0.032 55.86 ;
        RECT  0 50.172 0.032 50.46 ;
        RECT  0 44.772 0.032 45.06 ;
        RECT  0 39.372 0.032 39.66 ;
        RECT  0 33.972 0.032 34.26 ;
        RECT  0 28.572 0.032 28.86 ;
        RECT  0 23.172 0.032 23.46 ;
        RECT  0 17.772 0.032 18.06 ;
        RECT  0 12.372 0.032 12.66 ;
        RECT  0 6.972 0.032 7.26 ;
        RECT  0 1.572 0.032 1.86 ;
      LAYER M2 ;
        RECT  0 117.981 0.018 117.999 ;
        RECT  0 117.441 0.018 117.459 ;
        RECT  0 116.901 0.018 116.919 ;
        RECT  0 116.361 0.018 116.379 ;
        RECT  0 115.821 0.018 115.839 ;
        RECT  0 115.281 0.018 115.299 ;
        RECT  0 114.741 0.018 114.759 ;
        RECT  0 114.201 0.018 114.219 ;
        RECT  0 113.661 0.018 113.679 ;
        RECT  0 113.121 0.018 113.139 ;
        RECT  0 112.581 0.018 112.599 ;
        RECT  0 112.041 0.018 112.059 ;
        RECT  0 111.501 0.018 111.519 ;
        RECT  0 110.961 0.018 110.979 ;
        RECT  0 110.421 0.018 110.439 ;
        RECT  0 109.881 0.018 109.899 ;
        RECT  0 109.341 0.018 109.359 ;
        RECT  0 108.801 0.018 108.819 ;
        RECT  0 108.261 0.018 108.279 ;
        RECT  0 107.721 0.018 107.739 ;
        RECT  0 107.181 0.018 107.199 ;
        RECT  0 106.641 0.018 106.659 ;
        RECT  0 106.101 0.018 106.119 ;
        RECT  0 105.561 0.018 105.579 ;
        RECT  0 105.021 0.018 105.039 ;
        RECT  0 104.481 0.018 104.499 ;
        RECT  0 103.941 0.018 103.959 ;
        RECT  0 103.401 0.018 103.419 ;
        RECT  0 102.861 0.018 102.879 ;
        RECT  0 102.321 0.018 102.339 ;
        RECT  0 101.781 0.018 101.799 ;
        RECT  0 101.241 0.018 101.259 ;
        RECT  0 100.701 0.018 100.719 ;
        RECT  0 100.161 0.018 100.179 ;
        RECT  0 99.621 0.018 99.639 ;
        RECT  0 99.081 0.018 99.099 ;
        RECT  0 98.541 0.018 98.559 ;
        RECT  0 98.001 0.018 98.019 ;
        RECT  0 97.461 0.018 97.479 ;
        RECT  0 96.921 0.018 96.939 ;
        RECT  0 96.381 0.018 96.399 ;
        RECT  0 95.841 0.018 95.859 ;
        RECT  0 95.301 0.018 95.319 ;
        RECT  0 94.761 0.018 94.779 ;
        RECT  0 94.221 0.018 94.239 ;
        RECT  0 93.681 0.018 93.699 ;
        RECT  0 93.141 0.018 93.159 ;
        RECT  0 92.601 0.018 92.619 ;
        RECT  0 92.061 0.018 92.079 ;
        RECT  0 91.521 0.018 91.539 ;
        RECT  0 90.981 0.018 90.999 ;
        RECT  0 90.441 0.018 90.459 ;
        RECT  0 89.901 0.018 89.919 ;
        RECT  0 89.361 0.018 89.379 ;
        RECT  0 88.821 0.018 88.839 ;
        RECT  0 88.281 0.018 88.299 ;
        RECT  0 87.741 0.018 87.759 ;
        RECT  0 87.201 0.018 87.219 ;
        RECT  0 86.661 0.018 86.679 ;
        RECT  0 86.121 0.018 86.139 ;
        RECT  0 85.581 0.018 85.599 ;
        RECT  0 85.041 0.018 85.059 ;
        RECT  0 84.501 0.018 84.519 ;
        RECT  0 83.961 0.018 83.979 ;
        RECT  0 83.421 0.018 83.439 ;
        RECT  0 82.881 0.018 82.899 ;
        RECT  0 82.341 0.018 82.359 ;
        RECT  0 81.801 0.018 81.819 ;
        RECT  0 81.261 0.018 81.279 ;
        RECT  0 80.721 0.018 80.739 ;
        RECT  0 80.181 0.018 80.199 ;
        RECT  0 79.641 0.018 79.659 ;
        RECT  0 79.101 0.018 79.119 ;
        RECT  0 78.561 0.018 78.579 ;
        RECT  0 78.021 0.018 78.039 ;
        RECT  0 77.481 0.018 77.499 ;
        RECT  0 76.941 0.018 76.959 ;
        RECT  0 76.401 0.018 76.419 ;
        RECT  0 75.861 0.018 75.879 ;
        RECT  0 75.321 0.018 75.339 ;
        RECT  0 74.781 0.018 74.799 ;
        RECT  0 74.241 0.018 74.259 ;
        RECT  0 73.701 0.018 73.719 ;
        RECT  0 73.161 0.018 73.179 ;
        RECT  0 72.621 0.018 72.639 ;
        RECT  0 72.081 0.018 72.099 ;
        RECT  0 71.541 0.018 71.559 ;
        RECT  0 71.001 0.018 71.019 ;
        RECT  0 70.461 0.018 70.479 ;
        RECT  0 69.921 0.018 69.939 ;
        RECT  0 69.381 0.018 69.399 ;
        RECT  0 68.841 0.018 68.859 ;
        RECT  0 68.301 0.018 68.319 ;
        RECT  0 67.761 0.018 67.779 ;
        RECT  0 67.221 0.018 67.239 ;
        RECT  0 66.681 0.018 66.699 ;
        RECT  0 66.141 0.018 66.159 ;
        RECT  0 65.601 0.018 65.619 ;
        RECT  0 65.061 0.018 65.079 ;
        RECT  0 64.521 0.018 64.539 ;
        RECT  0 63.981 0.018 63.999 ;
        RECT  0 63.441 0.018 63.459 ;
        RECT  0 62.901 0.018 62.919 ;
        RECT  0 62.361 0.018 62.379 ;
        RECT  0 61.821 0.018 61.839 ;
        RECT  0 61.281 0.018 61.299 ;
        RECT  0 60.741 0.018 60.759 ;
        RECT  0 60.201 0.018 60.219 ;
        RECT  0 59.661 0.018 59.679 ;
        RECT  0 59.121 0.018 59.139 ;
        RECT  0 58.581 0.018 58.599 ;
        RECT  0 58.041 0.018 58.059 ;
        RECT  0 57.501 0.018 57.519 ;
        RECT  0 56.961 0.018 56.979 ;
        RECT  0 56.421 0.018 56.439 ;
        RECT  0 55.881 0.018 55.899 ;
        RECT  0 55.341 0.018 55.359 ;
        RECT  0 54.801 0.018 54.819 ;
        RECT  0 54.261 0.018 54.279 ;
        RECT  0 53.721 0.018 53.739 ;
        RECT  0 53.181 0.018 53.199 ;
        RECT  0 52.641 0.018 52.659 ;
        RECT  0 52.101 0.018 52.119 ;
        RECT  0 51.561 0.018 51.579 ;
        RECT  0 51.021 0.018 51.039 ;
        RECT  0 50.481 0.018 50.499 ;
        RECT  0 49.941 0.018 49.959 ;
        RECT  0 49.401 0.018 49.419 ;
        RECT  0 48.861 0.018 48.879 ;
        RECT  0 48.321 0.018 48.339 ;
        RECT  0 47.781 0.018 47.799 ;
        RECT  0 47.241 0.018 47.259 ;
        RECT  0 46.701 0.018 46.719 ;
        RECT  0 46.161 0.018 46.179 ;
        RECT  0 45.621 0.018 45.639 ;
        RECT  0 45.081 0.018 45.099 ;
        RECT  0 44.541 0.018 44.559 ;
        RECT  0 44.001 0.018 44.019 ;
        RECT  0 43.461 0.018 43.479 ;
        RECT  0 42.921 0.018 42.939 ;
        RECT  0 42.381 0.018 42.399 ;
        RECT  0 41.841 0.018 41.859 ;
        RECT  0 41.301 0.018 41.319 ;
        RECT  0 40.761 0.018 40.779 ;
        RECT  0 40.221 0.018 40.239 ;
        RECT  0 39.681 0.018 39.699 ;
        RECT  0 39.141 0.018 39.159 ;
        RECT  0 38.601 0.018 38.619 ;
        RECT  0 38.061 0.018 38.079 ;
        RECT  0 37.521 0.018 37.539 ;
        RECT  0 36.981 0.018 36.999 ;
        RECT  0 36.441 0.018 36.459 ;
        RECT  0 35.901 0.018 35.919 ;
        RECT  0 35.361 0.018 35.379 ;
        RECT  0 34.821 0.018 34.839 ;
        RECT  0 34.281 0.018 34.299 ;
        RECT  0 33.741 0.018 33.759 ;
        RECT  0 33.201 0.018 33.219 ;
        RECT  0 32.661 0.018 32.679 ;
        RECT  0 32.121 0.018 32.139 ;
        RECT  0 31.581 0.018 31.599 ;
        RECT  0 31.041 0.018 31.059 ;
        RECT  0 30.501 0.018 30.519 ;
        RECT  0 29.961 0.018 29.979 ;
        RECT  0 29.421 0.018 29.439 ;
        RECT  0 28.881 0.018 28.899 ;
        RECT  0 28.341 0.018 28.359 ;
        RECT  0 27.801 0.018 27.819 ;
        RECT  0 27.261 0.018 27.279 ;
        RECT  0 26.721 0.018 26.739 ;
        RECT  0 26.181 0.018 26.199 ;
        RECT  0 25.641 0.018 25.659 ;
        RECT  0 25.101 0.018 25.119 ;
        RECT  0 24.561 0.018 24.579 ;
        RECT  0 24.021 0.018 24.039 ;
        RECT  0 23.481 0.018 23.499 ;
        RECT  0 22.941 0.018 22.959 ;
        RECT  0 22.401 0.018 22.419 ;
        RECT  0 21.861 0.018 21.879 ;
        RECT  0 21.321 0.018 21.339 ;
        RECT  0 20.781 0.018 20.799 ;
        RECT  0 20.241 0.018 20.259 ;
        RECT  0 19.701 0.018 19.719 ;
        RECT  0 19.161 0.018 19.179 ;
        RECT  0 18.621 0.018 18.639 ;
        RECT  0 18.081 0.018 18.099 ;
        RECT  0 17.541 0.018 17.559 ;
        RECT  0 17.001 0.018 17.019 ;
        RECT  0 16.461 0.018 16.479 ;
        RECT  0 15.921 0.018 15.939 ;
        RECT  0 15.381 0.018 15.399 ;
        RECT  0 14.841 0.018 14.859 ;
        RECT  0 14.301 0.018 14.319 ;
        RECT  0 13.761 0.018 13.779 ;
        RECT  0 13.221 0.018 13.239 ;
        RECT  0 12.681 0.018 12.699 ;
        RECT  0 12.141 0.018 12.159 ;
        RECT  0 11.601 0.018 11.619 ;
        RECT  0 11.061 0.018 11.079 ;
        RECT  0 10.521 0.018 10.539 ;
        RECT  0 9.981 0.018 9.999 ;
        RECT  0 9.441 0.018 9.459 ;
        RECT  0 8.901 0.018 8.919 ;
        RECT  0 8.361 0.018 8.379 ;
        RECT  0 7.821 0.018 7.839 ;
        RECT  0 7.281 0.018 7.299 ;
        RECT  0 6.741 0.018 6.759 ;
        RECT  0 6.201 0.018 6.219 ;
        RECT  0 5.661 0.018 5.679 ;
        RECT  0 5.121 0.018 5.139 ;
        RECT  0 4.581 0.018 4.599 ;
        RECT  0 4.041 0.018 4.059 ;
        RECT  0 3.501 0.018 3.519 ;
        RECT  0 2.961 0.018 2.979 ;
        RECT  0 2.421 0.018 2.439 ;
        RECT  0 1.881 0.018 1.899 ;
        RECT  0 1.341 0.018 1.359 ;
        RECT  0 0.801 0.018 0.819 ;
      LAYER M1 ;
        RECT  0 117.981 0.018 117.999 ;
        RECT  0 117.441 0.018 117.459 ;
        RECT  0 116.901 0.018 116.919 ;
        RECT  0 116.361 0.018 116.379 ;
        RECT  0 115.821 0.018 115.839 ;
        RECT  0 115.281 0.018 115.299 ;
        RECT  0 114.741 0.018 114.759 ;
        RECT  0 114.201 0.018 114.219 ;
        RECT  0 113.661 0.018 113.679 ;
        RECT  0 113.121 0.018 113.139 ;
        RECT  0 112.581 0.018 112.599 ;
        RECT  0 112.041 0.018 112.059 ;
        RECT  0 111.501 0.018 111.519 ;
        RECT  0 110.961 0.018 110.979 ;
        RECT  0 110.421 0.018 110.439 ;
        RECT  0 109.881 0.018 109.899 ;
        RECT  0 109.341 0.018 109.359 ;
        RECT  0 108.801 0.018 108.819 ;
        RECT  0 108.261 0.018 108.279 ;
        RECT  0 107.721 0.018 107.739 ;
        RECT  0 107.181 0.018 107.199 ;
        RECT  0 106.641 0.018 106.659 ;
        RECT  0 106.101 0.018 106.119 ;
        RECT  0 105.561 0.018 105.579 ;
        RECT  0 105.021 0.018 105.039 ;
        RECT  0 104.481 0.018 104.499 ;
        RECT  0 103.941 0.018 103.959 ;
        RECT  0 103.401 0.018 103.419 ;
        RECT  0 102.861 0.018 102.879 ;
        RECT  0 102.321 0.018 102.339 ;
        RECT  0 101.781 0.018 101.799 ;
        RECT  0 101.241 0.018 101.259 ;
        RECT  0 100.701 0.018 100.719 ;
        RECT  0 100.161 0.018 100.179 ;
        RECT  0 99.621 0.018 99.639 ;
        RECT  0 99.081 0.018 99.099 ;
        RECT  0 98.541 0.018 98.559 ;
        RECT  0 98.001 0.018 98.019 ;
        RECT  0 97.461 0.018 97.479 ;
        RECT  0 96.921 0.018 96.939 ;
        RECT  0 96.381 0.018 96.399 ;
        RECT  0 95.841 0.018 95.859 ;
        RECT  0 95.301 0.018 95.319 ;
        RECT  0 94.761 0.018 94.779 ;
        RECT  0 94.221 0.018 94.239 ;
        RECT  0 93.681 0.018 93.699 ;
        RECT  0 93.141 0.018 93.159 ;
        RECT  0 92.601 0.018 92.619 ;
        RECT  0 92.061 0.018 92.079 ;
        RECT  0 91.521 0.018 91.539 ;
        RECT  0 90.981 0.018 90.999 ;
        RECT  0 90.441 0.018 90.459 ;
        RECT  0 89.901 0.018 89.919 ;
        RECT  0 89.361 0.018 89.379 ;
        RECT  0 88.821 0.018 88.839 ;
        RECT  0 88.281 0.018 88.299 ;
        RECT  0 87.741 0.018 87.759 ;
        RECT  0 87.201 0.018 87.219 ;
        RECT  0 86.661 0.018 86.679 ;
        RECT  0 86.121 0.018 86.139 ;
        RECT  0 85.581 0.018 85.599 ;
        RECT  0 85.041 0.018 85.059 ;
        RECT  0 84.501 0.018 84.519 ;
        RECT  0 83.961 0.018 83.979 ;
        RECT  0 83.421 0.018 83.439 ;
        RECT  0 82.881 0.018 82.899 ;
        RECT  0 82.341 0.018 82.359 ;
        RECT  0 81.801 0.018 81.819 ;
        RECT  0 81.261 0.018 81.279 ;
        RECT  0 80.721 0.018 80.739 ;
        RECT  0 80.181 0.018 80.199 ;
        RECT  0 79.641 0.018 79.659 ;
        RECT  0 79.101 0.018 79.119 ;
        RECT  0 78.561 0.018 78.579 ;
        RECT  0 78.021 0.018 78.039 ;
        RECT  0 77.481 0.018 77.499 ;
        RECT  0 76.941 0.018 76.959 ;
        RECT  0 76.401 0.018 76.419 ;
        RECT  0 75.861 0.018 75.879 ;
        RECT  0 75.321 0.018 75.339 ;
        RECT  0 74.781 0.018 74.799 ;
        RECT  0 74.241 0.018 74.259 ;
        RECT  0 73.701 0.018 73.719 ;
        RECT  0 73.161 0.018 73.179 ;
        RECT  0 72.621 0.018 72.639 ;
        RECT  0 72.081 0.018 72.099 ;
        RECT  0 71.541 0.018 71.559 ;
        RECT  0 71.001 0.018 71.019 ;
        RECT  0 70.461 0.018 70.479 ;
        RECT  0 69.921 0.018 69.939 ;
        RECT  0 69.381 0.018 69.399 ;
        RECT  0 68.841 0.018 68.859 ;
        RECT  0 68.301 0.018 68.319 ;
        RECT  0 67.761 0.018 67.779 ;
        RECT  0 67.221 0.018 67.239 ;
        RECT  0 66.681 0.018 66.699 ;
        RECT  0 66.141 0.018 66.159 ;
        RECT  0 65.601 0.018 65.619 ;
        RECT  0 65.061 0.018 65.079 ;
        RECT  0 64.521 0.018 64.539 ;
        RECT  0 63.981 0.018 63.999 ;
        RECT  0 63.441 0.018 63.459 ;
        RECT  0 62.901 0.018 62.919 ;
        RECT  0 62.361 0.018 62.379 ;
        RECT  0 61.821 0.018 61.839 ;
        RECT  0 61.281 0.018 61.299 ;
        RECT  0 60.741 0.018 60.759 ;
        RECT  0 60.201 0.018 60.219 ;
        RECT  0 59.661 0.018 59.679 ;
        RECT  0 59.121 0.018 59.139 ;
        RECT  0 58.581 0.018 58.599 ;
        RECT  0 58.041 0.018 58.059 ;
        RECT  0 57.501 0.018 57.519 ;
        RECT  0 56.961 0.018 56.979 ;
        RECT  0 56.421 0.018 56.439 ;
        RECT  0 55.881 0.018 55.899 ;
        RECT  0 55.341 0.018 55.359 ;
        RECT  0 54.801 0.018 54.819 ;
        RECT  0 54.261 0.018 54.279 ;
        RECT  0 53.721 0.018 53.739 ;
        RECT  0 53.181 0.018 53.199 ;
        RECT  0 52.641 0.018 52.659 ;
        RECT  0 52.101 0.018 52.119 ;
        RECT  0 51.561 0.018 51.579 ;
        RECT  0 51.021 0.018 51.039 ;
        RECT  0 50.481 0.018 50.499 ;
        RECT  0 49.941 0.018 49.959 ;
        RECT  0 49.401 0.018 49.419 ;
        RECT  0 48.861 0.018 48.879 ;
        RECT  0 48.321 0.018 48.339 ;
        RECT  0 47.781 0.018 47.799 ;
        RECT  0 47.241 0.018 47.259 ;
        RECT  0 46.701 0.018 46.719 ;
        RECT  0 46.161 0.018 46.179 ;
        RECT  0 45.621 0.018 45.639 ;
        RECT  0 45.081 0.018 45.099 ;
        RECT  0 44.541 0.018 44.559 ;
        RECT  0 44.001 0.018 44.019 ;
        RECT  0 43.461 0.018 43.479 ;
        RECT  0 42.921 0.018 42.939 ;
        RECT  0 42.381 0.018 42.399 ;
        RECT  0 41.841 0.018 41.859 ;
        RECT  0 41.301 0.018 41.319 ;
        RECT  0 40.761 0.018 40.779 ;
        RECT  0 40.221 0.018 40.239 ;
        RECT  0 39.681 0.018 39.699 ;
        RECT  0 39.141 0.018 39.159 ;
        RECT  0 38.601 0.018 38.619 ;
        RECT  0 38.061 0.018 38.079 ;
        RECT  0 37.521 0.018 37.539 ;
        RECT  0 36.981 0.018 36.999 ;
        RECT  0 36.441 0.018 36.459 ;
        RECT  0 35.901 0.018 35.919 ;
        RECT  0 35.361 0.018 35.379 ;
        RECT  0 34.821 0.018 34.839 ;
        RECT  0 34.281 0.018 34.299 ;
        RECT  0 33.741 0.018 33.759 ;
        RECT  0 33.201 0.018 33.219 ;
        RECT  0 32.661 0.018 32.679 ;
        RECT  0 32.121 0.018 32.139 ;
        RECT  0 31.581 0.018 31.599 ;
        RECT  0 31.041 0.018 31.059 ;
        RECT  0 30.501 0.018 30.519 ;
        RECT  0 29.961 0.018 29.979 ;
        RECT  0 29.421 0.018 29.439 ;
        RECT  0 28.881 0.018 28.899 ;
        RECT  0 28.341 0.018 28.359 ;
        RECT  0 27.801 0.018 27.819 ;
        RECT  0 27.261 0.018 27.279 ;
        RECT  0 26.721 0.018 26.739 ;
        RECT  0 26.181 0.018 26.199 ;
        RECT  0 25.641 0.018 25.659 ;
        RECT  0 25.101 0.018 25.119 ;
        RECT  0 24.561 0.018 24.579 ;
        RECT  0 24.021 0.018 24.039 ;
        RECT  0 23.481 0.018 23.499 ;
        RECT  0 22.941 0.018 22.959 ;
        RECT  0 22.401 0.018 22.419 ;
        RECT  0 21.861 0.018 21.879 ;
        RECT  0 21.321 0.018 21.339 ;
        RECT  0 20.781 0.018 20.799 ;
        RECT  0 20.241 0.018 20.259 ;
        RECT  0 19.701 0.018 19.719 ;
        RECT  0 19.161 0.018 19.179 ;
        RECT  0 18.621 0.018 18.639 ;
        RECT  0 18.081 0.018 18.099 ;
        RECT  0 17.541 0.018 17.559 ;
        RECT  0 17.001 0.018 17.019 ;
        RECT  0 16.461 0.018 16.479 ;
        RECT  0 15.921 0.018 15.939 ;
        RECT  0 15.381 0.018 15.399 ;
        RECT  0 14.841 0.018 14.859 ;
        RECT  0 14.301 0.018 14.319 ;
        RECT  0 13.761 0.018 13.779 ;
        RECT  0 13.221 0.018 13.239 ;
        RECT  0 12.681 0.018 12.699 ;
        RECT  0 12.141 0.018 12.159 ;
        RECT  0 11.601 0.018 11.619 ;
        RECT  0 11.061 0.018 11.079 ;
        RECT  0 10.521 0.018 10.539 ;
        RECT  0 9.981 0.018 9.999 ;
        RECT  0 9.441 0.018 9.459 ;
        RECT  0 8.901 0.018 8.919 ;
        RECT  0 8.361 0.018 8.379 ;
        RECT  0 7.821 0.018 7.839 ;
        RECT  0 7.281 0.018 7.299 ;
        RECT  0 6.741 0.018 6.759 ;
        RECT  0 6.201 0.018 6.219 ;
        RECT  0 5.661 0.018 5.679 ;
        RECT  0 5.121 0.018 5.139 ;
        RECT  0 4.581 0.018 4.599 ;
        RECT  0 4.041 0.018 4.059 ;
        RECT  0 3.501 0.018 3.519 ;
        RECT  0 2.961 0.018 2.979 ;
        RECT  0 2.421 0.018 2.439 ;
        RECT  0 1.881 0.018 1.899 ;
        RECT  0 1.341 0.018 1.359 ;
        RECT  0 0.801 0.018 0.819 ;
    END
  END VDD
  PIN VSS
    DIRECTION INOUT ;
    USE GROUND ;
    PORT
      LAYER M7 ;
        RECT  11.656 0.531 11.944 117.999 ;
        RECT  0.856 0.531 1.144 117.999 ;
      LAYER M6 ;
        RECT  0 114.396 0.032 114.684 ;
        RECT  0 108.996 0.032 109.284 ;
        RECT  0 103.596 0.032 103.884 ;
        RECT  0 98.196 0.032 98.484 ;
        RECT  0 92.796 0.032 93.084 ;
        RECT  0 87.396 0.032 87.684 ;
        RECT  0 81.996 0.032 82.284 ;
        RECT  0 76.596 0.032 76.884 ;
        RECT  0 71.196 0.032 71.484 ;
        RECT  0 65.796 0.032 66.084 ;
        RECT  0 60.396 0.032 60.684 ;
        RECT  0 54.996 0.032 55.284 ;
        RECT  0 49.596 0.032 49.884 ;
        RECT  0 44.196 0.032 44.484 ;
        RECT  0 38.796 0.032 39.084 ;
        RECT  0 33.396 0.032 33.684 ;
        RECT  0 27.996 0.032 28.284 ;
        RECT  0 22.596 0.032 22.884 ;
        RECT  0 17.196 0.032 17.484 ;
        RECT  0 11.796 0.032 12.084 ;
        RECT  0 6.396 0.032 6.684 ;
        RECT  0 0.996 0.032 1.284 ;
      LAYER M2 ;
        RECT  0 117.711 0.018 117.729 ;
        RECT  0 117.171 0.018 117.189 ;
        RECT  0 116.631 0.018 116.649 ;
        RECT  0 116.091 0.018 116.109 ;
        RECT  0 115.551 0.018 115.569 ;
        RECT  0 115.011 0.018 115.029 ;
        RECT  0 114.471 0.018 114.489 ;
        RECT  0 113.931 0.018 113.949 ;
        RECT  0 113.391 0.018 113.409 ;
        RECT  0 112.851 0.018 112.869 ;
        RECT  0 112.311 0.018 112.329 ;
        RECT  0 111.771 0.018 111.789 ;
        RECT  0 111.231 0.018 111.249 ;
        RECT  0 110.691 0.018 110.709 ;
        RECT  0 110.151 0.018 110.169 ;
        RECT  0 109.611 0.018 109.629 ;
        RECT  0 109.071 0.018 109.089 ;
        RECT  0 108.531 0.018 108.549 ;
        RECT  0 107.991 0.018 108.009 ;
        RECT  0 107.451 0.018 107.469 ;
        RECT  0 106.911 0.018 106.929 ;
        RECT  0 106.371 0.018 106.389 ;
        RECT  0 105.831 0.018 105.849 ;
        RECT  0 105.291 0.018 105.309 ;
        RECT  0 104.751 0.018 104.769 ;
        RECT  0 104.211 0.018 104.229 ;
        RECT  0 103.671 0.018 103.689 ;
        RECT  0 103.131 0.018 103.149 ;
        RECT  0 102.591 0.018 102.609 ;
        RECT  0 102.051 0.018 102.069 ;
        RECT  0 101.511 0.018 101.529 ;
        RECT  0 100.971 0.018 100.989 ;
        RECT  0 100.431 0.018 100.449 ;
        RECT  0 99.891 0.018 99.909 ;
        RECT  0 99.351 0.018 99.369 ;
        RECT  0 98.811 0.018 98.829 ;
        RECT  0 98.271 0.018 98.289 ;
        RECT  0 97.731 0.018 97.749 ;
        RECT  0 97.191 0.018 97.209 ;
        RECT  0 96.651 0.018 96.669 ;
        RECT  0 96.111 0.018 96.129 ;
        RECT  0 95.571 0.018 95.589 ;
        RECT  0 95.031 0.018 95.049 ;
        RECT  0 94.491 0.018 94.509 ;
        RECT  0 93.951 0.018 93.969 ;
        RECT  0 93.411 0.018 93.429 ;
        RECT  0 92.871 0.018 92.889 ;
        RECT  0 92.331 0.018 92.349 ;
        RECT  0 91.791 0.018 91.809 ;
        RECT  0 91.251 0.018 91.269 ;
        RECT  0 90.711 0.018 90.729 ;
        RECT  0 90.171 0.018 90.189 ;
        RECT  0 89.631 0.018 89.649 ;
        RECT  0 89.091 0.018 89.109 ;
        RECT  0 88.551 0.018 88.569 ;
        RECT  0 88.011 0.018 88.029 ;
        RECT  0 87.471 0.018 87.489 ;
        RECT  0 86.931 0.018 86.949 ;
        RECT  0 86.391 0.018 86.409 ;
        RECT  0 85.851 0.018 85.869 ;
        RECT  0 85.311 0.018 85.329 ;
        RECT  0 84.771 0.018 84.789 ;
        RECT  0 84.231 0.018 84.249 ;
        RECT  0 83.691 0.018 83.709 ;
        RECT  0 83.151 0.018 83.169 ;
        RECT  0 82.611 0.018 82.629 ;
        RECT  0 82.071 0.018 82.089 ;
        RECT  0 81.531 0.018 81.549 ;
        RECT  0 80.991 0.018 81.009 ;
        RECT  0 80.451 0.018 80.469 ;
        RECT  0 79.911 0.018 79.929 ;
        RECT  0 79.371 0.018 79.389 ;
        RECT  0 78.831 0.018 78.849 ;
        RECT  0 78.291 0.018 78.309 ;
        RECT  0 77.751 0.018 77.769 ;
        RECT  0 77.211 0.018 77.229 ;
        RECT  0 76.671 0.018 76.689 ;
        RECT  0 76.131 0.018 76.149 ;
        RECT  0 75.591 0.018 75.609 ;
        RECT  0 75.051 0.018 75.069 ;
        RECT  0 74.511 0.018 74.529 ;
        RECT  0 73.971 0.018 73.989 ;
        RECT  0 73.431 0.018 73.449 ;
        RECT  0 72.891 0.018 72.909 ;
        RECT  0 72.351 0.018 72.369 ;
        RECT  0 71.811 0.018 71.829 ;
        RECT  0 71.271 0.018 71.289 ;
        RECT  0 70.731 0.018 70.749 ;
        RECT  0 70.191 0.018 70.209 ;
        RECT  0 69.651 0.018 69.669 ;
        RECT  0 69.111 0.018 69.129 ;
        RECT  0 68.571 0.018 68.589 ;
        RECT  0 68.031 0.018 68.049 ;
        RECT  0 67.491 0.018 67.509 ;
        RECT  0 66.951 0.018 66.969 ;
        RECT  0 66.411 0.018 66.429 ;
        RECT  0 65.871 0.018 65.889 ;
        RECT  0 65.331 0.018 65.349 ;
        RECT  0 64.791 0.018 64.809 ;
        RECT  0 64.251 0.018 64.269 ;
        RECT  0 63.711 0.018 63.729 ;
        RECT  0 63.171 0.018 63.189 ;
        RECT  0 62.631 0.018 62.649 ;
        RECT  0 62.091 0.018 62.109 ;
        RECT  0 61.551 0.018 61.569 ;
        RECT  0 61.011 0.018 61.029 ;
        RECT  0 60.471 0.018 60.489 ;
        RECT  0 59.931 0.018 59.949 ;
        RECT  0 59.391 0.018 59.409 ;
        RECT  0 58.851 0.018 58.869 ;
        RECT  0 58.311 0.018 58.329 ;
        RECT  0 57.771 0.018 57.789 ;
        RECT  0 57.231 0.018 57.249 ;
        RECT  0 56.691 0.018 56.709 ;
        RECT  0 56.151 0.018 56.169 ;
        RECT  0 55.611 0.018 55.629 ;
        RECT  0 55.071 0.018 55.089 ;
        RECT  0 54.531 0.018 54.549 ;
        RECT  0 53.991 0.018 54.009 ;
        RECT  0 53.451 0.018 53.469 ;
        RECT  0 52.911 0.018 52.929 ;
        RECT  0 52.371 0.018 52.389 ;
        RECT  0 51.831 0.018 51.849 ;
        RECT  0 51.291 0.018 51.309 ;
        RECT  0 50.751 0.018 50.769 ;
        RECT  0 50.211 0.018 50.229 ;
        RECT  0 49.671 0.018 49.689 ;
        RECT  0 49.131 0.018 49.149 ;
        RECT  0 48.591 0.018 48.609 ;
        RECT  0 48.051 0.018 48.069 ;
        RECT  0 47.511 0.018 47.529 ;
        RECT  0 46.971 0.018 46.989 ;
        RECT  0 46.431 0.018 46.449 ;
        RECT  0 45.891 0.018 45.909 ;
        RECT  0 45.351 0.018 45.369 ;
        RECT  0 44.811 0.018 44.829 ;
        RECT  0 44.271 0.018 44.289 ;
        RECT  0 43.731 0.018 43.749 ;
        RECT  0 43.191 0.018 43.209 ;
        RECT  0 42.651 0.018 42.669 ;
        RECT  0 42.111 0.018 42.129 ;
        RECT  0 41.571 0.018 41.589 ;
        RECT  0 41.031 0.018 41.049 ;
        RECT  0 40.491 0.018 40.509 ;
        RECT  0 39.951 0.018 39.969 ;
        RECT  0 39.411 0.018 39.429 ;
        RECT  0 38.871 0.018 38.889 ;
        RECT  0 38.331 0.018 38.349 ;
        RECT  0 37.791 0.018 37.809 ;
        RECT  0 37.251 0.018 37.269 ;
        RECT  0 36.711 0.018 36.729 ;
        RECT  0 36.171 0.018 36.189 ;
        RECT  0 35.631 0.018 35.649 ;
        RECT  0 35.091 0.018 35.109 ;
        RECT  0 34.551 0.018 34.569 ;
        RECT  0 34.011 0.018 34.029 ;
        RECT  0 33.471 0.018 33.489 ;
        RECT  0 32.931 0.018 32.949 ;
        RECT  0 32.391 0.018 32.409 ;
        RECT  0 31.851 0.018 31.869 ;
        RECT  0 31.311 0.018 31.329 ;
        RECT  0 30.771 0.018 30.789 ;
        RECT  0 30.231 0.018 30.249 ;
        RECT  0 29.691 0.018 29.709 ;
        RECT  0 29.151 0.018 29.169 ;
        RECT  0 28.611 0.018 28.629 ;
        RECT  0 28.071 0.018 28.089 ;
        RECT  0 27.531 0.018 27.549 ;
        RECT  0 26.991 0.018 27.009 ;
        RECT  0 26.451 0.018 26.469 ;
        RECT  0 25.911 0.018 25.929 ;
        RECT  0 25.371 0.018 25.389 ;
        RECT  0 24.831 0.018 24.849 ;
        RECT  0 24.291 0.018 24.309 ;
        RECT  0 23.751 0.018 23.769 ;
        RECT  0 23.211 0.018 23.229 ;
        RECT  0 22.671 0.018 22.689 ;
        RECT  0 22.131 0.018 22.149 ;
        RECT  0 21.591 0.018 21.609 ;
        RECT  0 21.051 0.018 21.069 ;
        RECT  0 20.511 0.018 20.529 ;
        RECT  0 19.971 0.018 19.989 ;
        RECT  0 19.431 0.018 19.449 ;
        RECT  0 18.891 0.018 18.909 ;
        RECT  0 18.351 0.018 18.369 ;
        RECT  0 17.811 0.018 17.829 ;
        RECT  0 17.271 0.018 17.289 ;
        RECT  0 16.731 0.018 16.749 ;
        RECT  0 16.191 0.018 16.209 ;
        RECT  0 15.651 0.018 15.669 ;
        RECT  0 15.111 0.018 15.129 ;
        RECT  0 14.571 0.018 14.589 ;
        RECT  0 14.031 0.018 14.049 ;
        RECT  0 13.491 0.018 13.509 ;
        RECT  0 12.951 0.018 12.969 ;
        RECT  0 12.411 0.018 12.429 ;
        RECT  0 11.871 0.018 11.889 ;
        RECT  0 11.331 0.018 11.349 ;
        RECT  0 10.791 0.018 10.809 ;
        RECT  0 10.251 0.018 10.269 ;
        RECT  0 9.711 0.018 9.729 ;
        RECT  0 9.171 0.018 9.189 ;
        RECT  0 8.631 0.018 8.649 ;
        RECT  0 8.091 0.018 8.109 ;
        RECT  0 7.551 0.018 7.569 ;
        RECT  0 7.011 0.018 7.029 ;
        RECT  0 6.471 0.018 6.489 ;
        RECT  0 5.931 0.018 5.949 ;
        RECT  0 5.391 0.018 5.409 ;
        RECT  0 4.851 0.018 4.869 ;
        RECT  0 4.311 0.018 4.329 ;
        RECT  0 3.771 0.018 3.789 ;
        RECT  0 3.231 0.018 3.249 ;
        RECT  0 2.691 0.018 2.709 ;
        RECT  0 2.151 0.018 2.169 ;
        RECT  0 1.611 0.018 1.629 ;
        RECT  0 1.071 0.018 1.089 ;
        RECT  0 0.531 0.018 0.549 ;
      LAYER M1 ;
        RECT  0 117.711 0.018 117.729 ;
        RECT  0 117.171 0.018 117.189 ;
        RECT  0 116.631 0.018 116.649 ;
        RECT  0 116.091 0.018 116.109 ;
        RECT  0 115.551 0.018 115.569 ;
        RECT  0 115.011 0.018 115.029 ;
        RECT  0 114.471 0.018 114.489 ;
        RECT  0 113.931 0.018 113.949 ;
        RECT  0 113.391 0.018 113.409 ;
        RECT  0 112.851 0.018 112.869 ;
        RECT  0 112.311 0.018 112.329 ;
        RECT  0 111.771 0.018 111.789 ;
        RECT  0 111.231 0.018 111.249 ;
        RECT  0 110.691 0.018 110.709 ;
        RECT  0 110.151 0.018 110.169 ;
        RECT  0 109.611 0.018 109.629 ;
        RECT  0 109.071 0.018 109.089 ;
        RECT  0 108.531 0.018 108.549 ;
        RECT  0 107.991 0.018 108.009 ;
        RECT  0 107.451 0.018 107.469 ;
        RECT  0 106.911 0.018 106.929 ;
        RECT  0 106.371 0.018 106.389 ;
        RECT  0 105.831 0.018 105.849 ;
        RECT  0 105.291 0.018 105.309 ;
        RECT  0 104.751 0.018 104.769 ;
        RECT  0 104.211 0.018 104.229 ;
        RECT  0 103.671 0.018 103.689 ;
        RECT  0 103.131 0.018 103.149 ;
        RECT  0 102.591 0.018 102.609 ;
        RECT  0 102.051 0.018 102.069 ;
        RECT  0 101.511 0.018 101.529 ;
        RECT  0 100.971 0.018 100.989 ;
        RECT  0 100.431 0.018 100.449 ;
        RECT  0 99.891 0.018 99.909 ;
        RECT  0 99.351 0.018 99.369 ;
        RECT  0 98.811 0.018 98.829 ;
        RECT  0 98.271 0.018 98.289 ;
        RECT  0 97.731 0.018 97.749 ;
        RECT  0 97.191 0.018 97.209 ;
        RECT  0 96.651 0.018 96.669 ;
        RECT  0 96.111 0.018 96.129 ;
        RECT  0 95.571 0.018 95.589 ;
        RECT  0 95.031 0.018 95.049 ;
        RECT  0 94.491 0.018 94.509 ;
        RECT  0 93.951 0.018 93.969 ;
        RECT  0 93.411 0.018 93.429 ;
        RECT  0 92.871 0.018 92.889 ;
        RECT  0 92.331 0.018 92.349 ;
        RECT  0 91.791 0.018 91.809 ;
        RECT  0 91.251 0.018 91.269 ;
        RECT  0 90.711 0.018 90.729 ;
        RECT  0 90.171 0.018 90.189 ;
        RECT  0 89.631 0.018 89.649 ;
        RECT  0 89.091 0.018 89.109 ;
        RECT  0 88.551 0.018 88.569 ;
        RECT  0 88.011 0.018 88.029 ;
        RECT  0 87.471 0.018 87.489 ;
        RECT  0 86.931 0.018 86.949 ;
        RECT  0 86.391 0.018 86.409 ;
        RECT  0 85.851 0.018 85.869 ;
        RECT  0 85.311 0.018 85.329 ;
        RECT  0 84.771 0.018 84.789 ;
        RECT  0 84.231 0.018 84.249 ;
        RECT  0 83.691 0.018 83.709 ;
        RECT  0 83.151 0.018 83.169 ;
        RECT  0 82.611 0.018 82.629 ;
        RECT  0 82.071 0.018 82.089 ;
        RECT  0 81.531 0.018 81.549 ;
        RECT  0 80.991 0.018 81.009 ;
        RECT  0 80.451 0.018 80.469 ;
        RECT  0 79.911 0.018 79.929 ;
        RECT  0 79.371 0.018 79.389 ;
        RECT  0 78.831 0.018 78.849 ;
        RECT  0 78.291 0.018 78.309 ;
        RECT  0 77.751 0.018 77.769 ;
        RECT  0 77.211 0.018 77.229 ;
        RECT  0 76.671 0.018 76.689 ;
        RECT  0 76.131 0.018 76.149 ;
        RECT  0 75.591 0.018 75.609 ;
        RECT  0 75.051 0.018 75.069 ;
        RECT  0 74.511 0.018 74.529 ;
        RECT  0 73.971 0.018 73.989 ;
        RECT  0 73.431 0.018 73.449 ;
        RECT  0 72.891 0.018 72.909 ;
        RECT  0 72.351 0.018 72.369 ;
        RECT  0 71.811 0.018 71.829 ;
        RECT  0 71.271 0.018 71.289 ;
        RECT  0 70.731 0.018 70.749 ;
        RECT  0 70.191 0.018 70.209 ;
        RECT  0 69.651 0.018 69.669 ;
        RECT  0 69.111 0.018 69.129 ;
        RECT  0 68.571 0.018 68.589 ;
        RECT  0 68.031 0.018 68.049 ;
        RECT  0 67.491 0.018 67.509 ;
        RECT  0 66.951 0.018 66.969 ;
        RECT  0 66.411 0.018 66.429 ;
        RECT  0 65.871 0.018 65.889 ;
        RECT  0 65.331 0.018 65.349 ;
        RECT  0 64.791 0.018 64.809 ;
        RECT  0 64.251 0.018 64.269 ;
        RECT  0 63.711 0.018 63.729 ;
        RECT  0 63.171 0.018 63.189 ;
        RECT  0 62.631 0.018 62.649 ;
        RECT  0 62.091 0.018 62.109 ;
        RECT  0 61.551 0.018 61.569 ;
        RECT  0 61.011 0.018 61.029 ;
        RECT  0 60.471 0.018 60.489 ;
        RECT  0 59.931 0.018 59.949 ;
        RECT  0 59.391 0.018 59.409 ;
        RECT  0 58.851 0.018 58.869 ;
        RECT  0 58.311 0.018 58.329 ;
        RECT  0 57.771 0.018 57.789 ;
        RECT  0 57.231 0.018 57.249 ;
        RECT  0 56.691 0.018 56.709 ;
        RECT  0 56.151 0.018 56.169 ;
        RECT  0 55.611 0.018 55.629 ;
        RECT  0 55.071 0.018 55.089 ;
        RECT  0 54.531 0.018 54.549 ;
        RECT  0 53.991 0.018 54.009 ;
        RECT  0 53.451 0.018 53.469 ;
        RECT  0 52.911 0.018 52.929 ;
        RECT  0 52.371 0.018 52.389 ;
        RECT  0 51.831 0.018 51.849 ;
        RECT  0 51.291 0.018 51.309 ;
        RECT  0 50.751 0.018 50.769 ;
        RECT  0 50.211 0.018 50.229 ;
        RECT  0 49.671 0.018 49.689 ;
        RECT  0 49.131 0.018 49.149 ;
        RECT  0 48.591 0.018 48.609 ;
        RECT  0 48.051 0.018 48.069 ;
        RECT  0 47.511 0.018 47.529 ;
        RECT  0 46.971 0.018 46.989 ;
        RECT  0 46.431 0.018 46.449 ;
        RECT  0 45.891 0.018 45.909 ;
        RECT  0 45.351 0.018 45.369 ;
        RECT  0 44.811 0.018 44.829 ;
        RECT  0 44.271 0.018 44.289 ;
        RECT  0 43.731 0.018 43.749 ;
        RECT  0 43.191 0.018 43.209 ;
        RECT  0 42.651 0.018 42.669 ;
        RECT  0 42.111 0.018 42.129 ;
        RECT  0 41.571 0.018 41.589 ;
        RECT  0 41.031 0.018 41.049 ;
        RECT  0 40.491 0.018 40.509 ;
        RECT  0 39.951 0.018 39.969 ;
        RECT  0 39.411 0.018 39.429 ;
        RECT  0 38.871 0.018 38.889 ;
        RECT  0 38.331 0.018 38.349 ;
        RECT  0 37.791 0.018 37.809 ;
        RECT  0 37.251 0.018 37.269 ;
        RECT  0 36.711 0.018 36.729 ;
        RECT  0 36.171 0.018 36.189 ;
        RECT  0 35.631 0.018 35.649 ;
        RECT  0 35.091 0.018 35.109 ;
        RECT  0 34.551 0.018 34.569 ;
        RECT  0 34.011 0.018 34.029 ;
        RECT  0 33.471 0.018 33.489 ;
        RECT  0 32.931 0.018 32.949 ;
        RECT  0 32.391 0.018 32.409 ;
        RECT  0 31.851 0.018 31.869 ;
        RECT  0 31.311 0.018 31.329 ;
        RECT  0 30.771 0.018 30.789 ;
        RECT  0 30.231 0.018 30.249 ;
        RECT  0 29.691 0.018 29.709 ;
        RECT  0 29.151 0.018 29.169 ;
        RECT  0 28.611 0.018 28.629 ;
        RECT  0 28.071 0.018 28.089 ;
        RECT  0 27.531 0.018 27.549 ;
        RECT  0 26.991 0.018 27.009 ;
        RECT  0 26.451 0.018 26.469 ;
        RECT  0 25.911 0.018 25.929 ;
        RECT  0 25.371 0.018 25.389 ;
        RECT  0 24.831 0.018 24.849 ;
        RECT  0 24.291 0.018 24.309 ;
        RECT  0 23.751 0.018 23.769 ;
        RECT  0 23.211 0.018 23.229 ;
        RECT  0 22.671 0.018 22.689 ;
        RECT  0 22.131 0.018 22.149 ;
        RECT  0 21.591 0.018 21.609 ;
        RECT  0 21.051 0.018 21.069 ;
        RECT  0 20.511 0.018 20.529 ;
        RECT  0 19.971 0.018 19.989 ;
        RECT  0 19.431 0.018 19.449 ;
        RECT  0 18.891 0.018 18.909 ;
        RECT  0 18.351 0.018 18.369 ;
        RECT  0 17.811 0.018 17.829 ;
        RECT  0 17.271 0.018 17.289 ;
        RECT  0 16.731 0.018 16.749 ;
        RECT  0 16.191 0.018 16.209 ;
        RECT  0 15.651 0.018 15.669 ;
        RECT  0 15.111 0.018 15.129 ;
        RECT  0 14.571 0.018 14.589 ;
        RECT  0 14.031 0.018 14.049 ;
        RECT  0 13.491 0.018 13.509 ;
        RECT  0 12.951 0.018 12.969 ;
        RECT  0 12.411 0.018 12.429 ;
        RECT  0 11.871 0.018 11.889 ;
        RECT  0 11.331 0.018 11.349 ;
        RECT  0 10.791 0.018 10.809 ;
        RECT  0 10.251 0.018 10.269 ;
        RECT  0 9.711 0.018 9.729 ;
        RECT  0 9.171 0.018 9.189 ;
        RECT  0 8.631 0.018 8.649 ;
        RECT  0 8.091 0.018 8.109 ;
        RECT  0 7.551 0.018 7.569 ;
        RECT  0 7.011 0.018 7.029 ;
        RECT  0 6.471 0.018 6.489 ;
        RECT  0 5.931 0.018 5.949 ;
        RECT  0 5.391 0.018 5.409 ;
        RECT  0 4.851 0.018 4.869 ;
        RECT  0 4.311 0.018 4.329 ;
        RECT  0 3.771 0.018 3.789 ;
        RECT  0 3.231 0.018 3.249 ;
        RECT  0 2.691 0.018 2.709 ;
        RECT  0 2.151 0.018 2.169 ;
        RECT  0 1.611 0.018 1.629 ;
        RECT  0 1.071 0.018 1.089 ;
        RECT  0 0.531 0.018 0.549 ;
    END
  END VSS
  OBS
    LAYER RVTN ;
     RECT  0 0.54 18.954 0.675 ;
     RECT  0 0.945 18.954 1.215 ;
     RECT  0 1.485 18.954 1.755 ;
     RECT  0 2.025 18.954 2.295 ;
     RECT  0 2.565 18.954 2.835 ;
     RECT  0 3.105 18.954 3.375 ;
     RECT  0 3.645 18.954 3.915 ;
     RECT  0 4.185 18.954 4.455 ;
     RECT  0 4.725 18.954 4.995 ;
     RECT  0 5.265 18.954 5.535 ;
     RECT  0 5.805 18.954 6.075 ;
     RECT  0 6.345 18.954 6.615 ;
     RECT  0 6.885 18.954 7.155 ;
     RECT  0 7.425 18.954 7.695 ;
     RECT  0 7.965 18.954 8.235 ;
     RECT  0 8.505 18.954 8.775 ;
     RECT  0 9.045 18.954 9.315 ;
     RECT  0 9.585 18.954 9.855 ;
     RECT  0 10.125 18.954 10.395 ;
     RECT  0 10.665 18.954 10.935 ;
     RECT  0 11.205 18.954 11.475 ;
     RECT  0 11.745 18.954 12.015 ;
     RECT  0 12.285 18.954 12.555 ;
     RECT  0 12.825 18.954 13.095 ;
     RECT  0 13.365 18.954 13.635 ;
     RECT  0 13.905 18.954 14.175 ;
     RECT  0 14.445 18.954 14.715 ;
     RECT  0 14.985 18.954 15.255 ;
     RECT  0 15.525 18.954 15.795 ;
     RECT  0 16.065 18.954 16.335 ;
     RECT  0 16.605 18.954 16.875 ;
     RECT  0 17.145 18.954 17.415 ;
     RECT  0 17.685 18.954 17.955 ;
     RECT  0 18.225 18.954 18.495 ;
     RECT  0 18.765 18.954 19.035 ;
     RECT  0 19.305 18.954 19.575 ;
     RECT  0 19.845 18.954 20.115 ;
     RECT  0 20.385 18.954 20.655 ;
     RECT  0 20.925 18.954 21.195 ;
     RECT  0 21.465 18.954 21.735 ;
     RECT  0 22.005 18.954 22.275 ;
     RECT  0 22.545 18.954 22.815 ;
     RECT  0 23.085 18.954 23.355 ;
     RECT  0 23.625 18.954 23.895 ;
     RECT  0 24.165 18.954 24.435 ;
     RECT  0 24.705 18.954 24.975 ;
     RECT  0 25.245 18.954 25.515 ;
     RECT  0 25.785 18.954 26.055 ;
     RECT  0 26.325 18.954 26.595 ;
     RECT  0 26.865 18.954 27.135 ;
     RECT  0 27.405 18.954 27.675 ;
     RECT  0 27.945 18.954 28.215 ;
     RECT  0 28.485 18.954 28.755 ;
     RECT  0 29.025 18.954 29.295 ;
     RECT  0 29.565 18.954 29.835 ;
     RECT  0 30.105 18.954 30.375 ;
     RECT  0 30.645 18.954 30.915 ;
     RECT  0 31.185 18.954 31.455 ;
     RECT  0 31.725 18.954 31.995 ;
     RECT  0 32.265 18.954 32.535 ;
     RECT  0 32.805 18.954 33.075 ;
     RECT  0 33.345 18.954 33.615 ;
     RECT  0 33.885 18.954 34.155 ;
     RECT  0 34.425 18.954 34.695 ;
     RECT  0 34.965 18.954 35.235 ;
     RECT  0 35.505 18.954 35.775 ;
     RECT  0 36.045 18.954 36.315 ;
     RECT  0 36.585 18.954 36.855 ;
     RECT  0 37.125 18.954 37.395 ;
     RECT  0 37.665 18.954 37.935 ;
     RECT  0 38.205 18.954 38.475 ;
     RECT  0 38.745 18.954 39.015 ;
     RECT  0 39.285 18.954 39.555 ;
     RECT  0 39.825 18.954 40.095 ;
     RECT  0 40.365 18.954 40.635 ;
     RECT  0 40.905 18.954 41.175 ;
     RECT  0 41.445 18.954 41.715 ;
     RECT  0 41.985 18.954 42.255 ;
     RECT  0 42.525 18.954 42.795 ;
     RECT  0 43.065 18.954 43.335 ;
     RECT  0 43.605 18.954 43.875 ;
     RECT  0 44.145 18.954 44.415 ;
     RECT  0 44.685 18.954 44.955 ;
     RECT  0 45.225 18.954 45.495 ;
     RECT  0 45.765 18.954 46.035 ;
     RECT  0 46.305 18.954 46.575 ;
     RECT  0 46.845 18.954 47.115 ;
     RECT  0 47.385 18.954 47.655 ;
     RECT  0 47.925 18.954 48.195 ;
     RECT  0 48.465 18.954 48.735 ;
     RECT  0 49.005 18.954 49.275 ;
     RECT  0 49.545 18.954 49.815 ;
     RECT  0 50.085 18.954 50.355 ;
     RECT  0 50.625 18.954 50.895 ;
     RECT  0 51.165 18.954 51.435 ;
     RECT  0 51.705 18.954 51.975 ;
     RECT  0 52.245 18.954 52.515 ;
     RECT  0 52.785 18.954 53.055 ;
     RECT  0 53.325 18.954 53.595 ;
     RECT  0 53.865 18.954 54.135 ;
     RECT  0 54.405 18.954 54.675 ;
     RECT  0 54.945 18.954 55.215 ;
     RECT  0 55.485 18.954 55.755 ;
     RECT  0 56.025 18.954 56.295 ;
     RECT  0 56.565 18.954 56.835 ;
     RECT  0 57.105 18.954 57.375 ;
     RECT  0 57.645 18.954 57.915 ;
     RECT  0 58.185 18.954 58.455 ;
     RECT  0 58.725 18.954 58.995 ;
     RECT  0 59.265 18.954 59.535 ;
     RECT  0 59.805 18.954 60.075 ;
     RECT  0 60.345 18.954 60.615 ;
     RECT  0 60.885 18.954 61.155 ;
     RECT  0 61.425 18.954 61.695 ;
     RECT  0 61.965 18.954 62.235 ;
     RECT  0 62.505 18.954 62.775 ;
     RECT  0 63.045 18.954 63.315 ;
     RECT  0 63.585 18.954 63.855 ;
     RECT  0 64.125 18.954 64.395 ;
     RECT  0 64.665 18.954 64.935 ;
     RECT  0 65.205 18.954 65.475 ;
     RECT  0 65.745 18.954 66.015 ;
     RECT  0 66.285 18.954 66.555 ;
     RECT  0 66.825 18.954 67.095 ;
     RECT  0 67.365 18.954 67.635 ;
     RECT  0 67.905 18.954 68.175 ;
     RECT  0 68.445 18.954 68.715 ;
     RECT  0 68.985 18.954 69.255 ;
     RECT  0 69.525 18.954 69.795 ;
     RECT  0 70.065 18.954 70.335 ;
     RECT  0 70.605 18.954 70.875 ;
     RECT  0 71.145 18.954 71.415 ;
     RECT  0 71.685 18.954 71.955 ;
     RECT  0 72.225 18.954 72.495 ;
     RECT  0 72.765 18.954 73.035 ;
     RECT  0 73.305 18.954 73.575 ;
     RECT  0 73.845 18.954 74.115 ;
     RECT  0 74.385 18.954 74.655 ;
     RECT  0 74.925 18.954 75.195 ;
     RECT  0 75.465 18.954 75.735 ;
     RECT  0 76.005 18.954 76.275 ;
     RECT  0 76.545 18.954 76.815 ;
     RECT  0 77.085 18.954 77.355 ;
     RECT  0 77.625 18.954 77.895 ;
     RECT  0 78.165 18.954 78.435 ;
     RECT  0 78.705 18.954 78.975 ;
     RECT  0 79.245 18.954 79.515 ;
     RECT  0 79.785 18.954 80.055 ;
     RECT  0 80.325 18.954 80.595 ;
     RECT  0 80.865 18.954 81.135 ;
     RECT  0 81.405 18.954 81.675 ;
     RECT  0 81.945 18.954 82.215 ;
     RECT  0 82.485 18.954 82.755 ;
     RECT  0 83.025 18.954 83.295 ;
     RECT  0 83.565 18.954 83.835 ;
     RECT  0 84.105 18.954 84.375 ;
     RECT  0 84.645 18.954 84.915 ;
     RECT  0 85.185 18.954 85.455 ;
     RECT  0 85.725 18.954 85.995 ;
     RECT  0 86.265 18.954 86.535 ;
     RECT  0 86.805 18.954 87.075 ;
     RECT  0 87.345 18.954 87.615 ;
     RECT  0 87.885 18.954 88.155 ;
     RECT  0 88.425 18.954 88.695 ;
     RECT  0 88.965 18.954 89.235 ;
     RECT  0 89.505 18.954 89.775 ;
     RECT  0 90.045 18.954 90.315 ;
     RECT  0 90.585 18.954 90.855 ;
     RECT  0 91.125 18.954 91.395 ;
     RECT  0 91.665 18.954 91.935 ;
     RECT  0 92.205 18.954 92.475 ;
     RECT  0 92.745 18.954 93.015 ;
     RECT  0 93.285 18.954 93.555 ;
     RECT  0 93.825 18.954 94.095 ;
     RECT  0 94.365 18.954 94.635 ;
     RECT  0 94.905 18.954 95.175 ;
     RECT  0 95.445 18.954 95.715 ;
     RECT  0 95.985 18.954 96.255 ;
     RECT  0 96.525 18.954 96.795 ;
     RECT  0 97.065 18.954 97.335 ;
     RECT  0 97.605 18.954 97.875 ;
     RECT  0 98.145 18.954 98.415 ;
     RECT  0 98.685 18.954 98.955 ;
     RECT  0 99.225 18.954 99.495 ;
     RECT  0 99.765 18.954 100.035 ;
     RECT  0 100.305 18.954 100.575 ;
     RECT  0 100.845 18.954 101.115 ;
     RECT  0 101.385 18.954 101.655 ;
     RECT  0 101.925 18.954 102.195 ;
     RECT  0 102.465 18.954 102.735 ;
     RECT  0 103.005 18.954 103.275 ;
     RECT  0 103.545 18.954 103.815 ;
     RECT  0 104.085 18.954 104.355 ;
     RECT  0 104.625 18.954 104.895 ;
     RECT  0 105.165 18.954 105.435 ;
     RECT  0 105.705 18.954 105.975 ;
     RECT  0 106.245 18.954 106.515 ;
     RECT  0 106.785 18.954 107.055 ;
     RECT  0 107.325 18.954 107.595 ;
     RECT  0 107.865 18.954 108.135 ;
     RECT  0 108.405 18.954 108.675 ;
     RECT  0 108.945 18.954 109.215 ;
     RECT  0 109.485 18.954 109.755 ;
     RECT  0 110.025 18.954 110.295 ;
     RECT  0 110.565 18.954 110.835 ;
     RECT  0 111.105 18.954 111.375 ;
     RECT  0 111.645 18.954 111.915 ;
     RECT  0 112.185 18.954 112.455 ;
     RECT  0 112.725 18.954 112.995 ;
     RECT  0 113.265 18.954 113.535 ;
     RECT  0 113.805 18.954 114.075 ;
     RECT  0 114.345 18.954 114.615 ;
     RECT  0 114.885 18.954 115.155 ;
     RECT  0 115.425 18.954 115.695 ;
     RECT  0 115.965 18.954 116.235 ;
     RECT  0 116.505 18.954 116.775 ;
     RECT  0 117.045 18.954 117.315 ;
     RECT  0 117.585 18.954 117.855 ;
    LAYER RVTP ;
     RECT  0 0.675 18.954 0.945 ;
     RECT  0 1.215 18.954 1.485 ;
     RECT  0 1.755 18.954 2.025 ;
     RECT  0 2.295 18.954 2.565 ;
     RECT  0 2.835 18.954 3.105 ;
     RECT  0 3.375 18.954 3.645 ;
     RECT  0 3.915 18.954 4.185 ;
     RECT  0 4.455 18.954 4.725 ;
     RECT  0 4.995 18.954 5.265 ;
     RECT  0 5.535 18.954 5.805 ;
     RECT  0 6.075 18.954 6.345 ;
     RECT  0 6.615 18.954 6.885 ;
     RECT  0 7.155 18.954 7.425 ;
     RECT  0 7.695 18.954 7.965 ;
     RECT  0 8.235 18.954 8.505 ;
     RECT  0 8.775 18.954 9.045 ;
     RECT  0 9.315 18.954 9.585 ;
     RECT  0 9.855 18.954 10.125 ;
     RECT  0 10.395 18.954 10.665 ;
     RECT  0 10.935 18.954 11.205 ;
     RECT  0 11.475 18.954 11.745 ;
     RECT  0 12.015 18.954 12.285 ;
     RECT  0 12.555 18.954 12.825 ;
     RECT  0 13.095 18.954 13.365 ;
     RECT  0 13.635 18.954 13.905 ;
     RECT  0 14.175 18.954 14.445 ;
     RECT  0 14.715 18.954 14.985 ;
     RECT  0 15.255 18.954 15.525 ;
     RECT  0 15.795 18.954 16.065 ;
     RECT  0 16.335 18.954 16.605 ;
     RECT  0 16.875 18.954 17.145 ;
     RECT  0 17.415 18.954 17.685 ;
     RECT  0 17.955 18.954 18.225 ;
     RECT  0 18.495 18.954 18.765 ;
     RECT  0 19.035 18.954 19.305 ;
     RECT  0 19.575 18.954 19.845 ;
     RECT  0 20.115 18.954 20.385 ;
     RECT  0 20.655 18.954 20.925 ;
     RECT  0 21.195 18.954 21.465 ;
     RECT  0 21.735 18.954 22.005 ;
     RECT  0 22.275 18.954 22.545 ;
     RECT  0 22.815 18.954 23.085 ;
     RECT  0 23.355 18.954 23.625 ;
     RECT  0 23.895 18.954 24.165 ;
     RECT  0 24.435 18.954 24.705 ;
     RECT  0 24.975 18.954 25.245 ;
     RECT  0 25.515 18.954 25.785 ;
     RECT  0 26.055 18.954 26.325 ;
     RECT  0 26.595 18.954 26.865 ;
     RECT  0 27.135 18.954 27.405 ;
     RECT  0 27.675 18.954 27.945 ;
     RECT  0 28.215 18.954 28.485 ;
     RECT  0 28.755 18.954 29.025 ;
     RECT  0 29.295 18.954 29.565 ;
     RECT  0 29.835 18.954 30.105 ;
     RECT  0 30.375 18.954 30.645 ;
     RECT  0 30.915 18.954 31.185 ;
     RECT  0 31.455 18.954 31.725 ;
     RECT  0 31.995 18.954 32.265 ;
     RECT  0 32.535 18.954 32.805 ;
     RECT  0 33.075 18.954 33.345 ;
     RECT  0 33.615 18.954 33.885 ;
     RECT  0 34.155 18.954 34.425 ;
     RECT  0 34.695 18.954 34.965 ;
     RECT  0 35.235 18.954 35.505 ;
     RECT  0 35.775 18.954 36.045 ;
     RECT  0 36.315 18.954 36.585 ;
     RECT  0 36.855 18.954 37.125 ;
     RECT  0 37.395 18.954 37.665 ;
     RECT  0 37.935 18.954 38.205 ;
     RECT  0 38.475 18.954 38.745 ;
     RECT  0 39.015 18.954 39.285 ;
     RECT  0 39.555 18.954 39.825 ;
     RECT  0 40.095 18.954 40.365 ;
     RECT  0 40.635 18.954 40.905 ;
     RECT  0 41.175 18.954 41.445 ;
     RECT  0 41.715 18.954 41.985 ;
     RECT  0 42.255 18.954 42.525 ;
     RECT  0 42.795 18.954 43.065 ;
     RECT  0 43.335 18.954 43.605 ;
     RECT  0 43.875 18.954 44.145 ;
     RECT  0 44.415 18.954 44.685 ;
     RECT  0 44.955 18.954 45.225 ;
     RECT  0 45.495 18.954 45.765 ;
     RECT  0 46.035 18.954 46.305 ;
     RECT  0 46.575 18.954 46.845 ;
     RECT  0 47.115 18.954 47.385 ;
     RECT  0 47.655 18.954 47.925 ;
     RECT  0 48.195 18.954 48.465 ;
     RECT  0 48.735 18.954 49.005 ;
     RECT  0 49.275 18.954 49.545 ;
     RECT  0 49.815 18.954 50.085 ;
     RECT  0 50.355 18.954 50.625 ;
     RECT  0 50.895 18.954 51.165 ;
     RECT  0 51.435 18.954 51.705 ;
     RECT  0 51.975 18.954 52.245 ;
     RECT  0 52.515 18.954 52.785 ;
     RECT  0 53.055 18.954 53.325 ;
     RECT  0 53.595 18.954 53.865 ;
     RECT  0 54.135 18.954 54.405 ;
     RECT  0 54.675 18.954 54.945 ;
     RECT  0 55.215 18.954 55.485 ;
     RECT  0 55.755 18.954 56.025 ;
     RECT  0 56.295 18.954 56.565 ;
     RECT  0 56.835 18.954 57.105 ;
     RECT  0 57.375 18.954 57.645 ;
     RECT  0 57.915 18.954 58.185 ;
     RECT  0 58.455 18.954 58.725 ;
     RECT  0 58.995 18.954 59.265 ;
     RECT  0 59.535 18.954 59.805 ;
     RECT  0 60.075 18.954 60.345 ;
     RECT  0 60.615 18.954 60.885 ;
     RECT  0 61.155 18.954 61.425 ;
     RECT  0 61.695 18.954 61.965 ;
     RECT  0 62.235 18.954 62.505 ;
     RECT  0 62.775 18.954 63.045 ;
     RECT  0 63.315 18.954 63.585 ;
     RECT  0 63.855 18.954 64.125 ;
     RECT  0 64.395 18.954 64.665 ;
     RECT  0 64.935 18.954 65.205 ;
     RECT  0 65.475 18.954 65.745 ;
     RECT  0 66.015 18.954 66.285 ;
     RECT  0 66.555 18.954 66.825 ;
     RECT  0 67.095 18.954 67.365 ;
     RECT  0 67.635 18.954 67.905 ;
     RECT  0 68.175 18.954 68.445 ;
     RECT  0 68.715 18.954 68.985 ;
     RECT  0 69.255 18.954 69.525 ;
     RECT  0 69.795 18.954 70.065 ;
     RECT  0 70.335 18.954 70.605 ;
     RECT  0 70.875 18.954 71.145 ;
     RECT  0 71.415 18.954 71.685 ;
     RECT  0 71.955 18.954 72.225 ;
     RECT  0 72.495 18.954 72.765 ;
     RECT  0 73.035 18.954 73.305 ;
     RECT  0 73.575 18.954 73.845 ;
     RECT  0 74.115 18.954 74.385 ;
     RECT  0 74.655 18.954 74.925 ;
     RECT  0 75.195 18.954 75.465 ;
     RECT  0 75.735 18.954 76.005 ;
     RECT  0 76.275 18.954 76.545 ;
     RECT  0 76.815 18.954 77.085 ;
     RECT  0 77.355 18.954 77.625 ;
     RECT  0 77.895 18.954 78.165 ;
     RECT  0 78.435 18.954 78.705 ;
     RECT  0 78.975 18.954 79.245 ;
     RECT  0 79.515 18.954 79.785 ;
     RECT  0 80.055 18.954 80.325 ;
     RECT  0 80.595 18.954 80.865 ;
     RECT  0 81.135 18.954 81.405 ;
     RECT  0 81.675 18.954 81.945 ;
     RECT  0 82.215 18.954 82.485 ;
     RECT  0 82.755 18.954 83.025 ;
     RECT  0 83.295 18.954 83.565 ;
     RECT  0 83.835 18.954 84.105 ;
     RECT  0 84.375 18.954 84.645 ;
     RECT  0 84.915 18.954 85.185 ;
     RECT  0 85.455 18.954 85.725 ;
     RECT  0 85.995 18.954 86.265 ;
     RECT  0 86.535 18.954 86.805 ;
     RECT  0 87.075 18.954 87.345 ;
     RECT  0 87.615 18.954 87.885 ;
     RECT  0 88.155 18.954 88.425 ;
     RECT  0 88.695 18.954 88.965 ;
     RECT  0 89.235 18.954 89.505 ;
     RECT  0 89.775 18.954 90.045 ;
     RECT  0 90.315 18.954 90.585 ;
     RECT  0 90.855 18.954 91.125 ;
     RECT  0 91.395 18.954 91.665 ;
     RECT  0 91.935 18.954 92.205 ;
     RECT  0 92.475 18.954 92.745 ;
     RECT  0 93.015 18.954 93.285 ;
     RECT  0 93.555 18.954 93.825 ;
     RECT  0 94.095 18.954 94.365 ;
     RECT  0 94.635 18.954 94.905 ;
     RECT  0 95.175 18.954 95.445 ;
     RECT  0 95.715 18.954 95.985 ;
     RECT  0 96.255 18.954 96.525 ;
     RECT  0 96.795 18.954 97.065 ;
     RECT  0 97.335 18.954 97.605 ;
     RECT  0 97.875 18.954 98.145 ;
     RECT  0 98.415 18.954 98.685 ;
     RECT  0 98.955 18.954 99.225 ;
     RECT  0 99.495 18.954 99.765 ;
     RECT  0 100.035 18.954 100.305 ;
     RECT  0 100.575 18.954 100.845 ;
     RECT  0 101.115 18.954 101.385 ;
     RECT  0 101.655 18.954 101.925 ;
     RECT  0 102.195 18.954 102.465 ;
     RECT  0 102.735 18.954 103.005 ;
     RECT  0 103.275 18.954 103.545 ;
     RECT  0 103.815 18.954 104.085 ;
     RECT  0 104.355 18.954 104.625 ;
     RECT  0 104.895 18.954 105.165 ;
     RECT  0 105.435 18.954 105.705 ;
     RECT  0 105.975 18.954 106.245 ;
     RECT  0 106.515 18.954 106.785 ;
     RECT  0 107.055 18.954 107.325 ;
     RECT  0 107.595 18.954 107.865 ;
     RECT  0 108.135 18.954 108.405 ;
     RECT  0 108.675 18.954 108.945 ;
     RECT  0 109.215 18.954 109.485 ;
     RECT  0 109.755 18.954 110.025 ;
     RECT  0 110.295 18.954 110.565 ;
     RECT  0 110.835 18.954 111.105 ;
     RECT  0 111.375 18.954 111.645 ;
     RECT  0 111.915 18.954 112.185 ;
     RECT  0 112.455 18.954 112.725 ;
     RECT  0 112.995 18.954 113.265 ;
     RECT  0 113.535 18.954 113.805 ;
     RECT  0 114.075 18.954 114.345 ;
     RECT  0 114.615 18.954 114.885 ;
     RECT  0 115.155 18.954 115.425 ;
     RECT  0 115.695 18.954 115.965 ;
     RECT  0 116.235 18.954 116.505 ;
     RECT  0 116.775 18.954 117.045 ;
     RECT  0 117.315 18.954 117.585 ;
     RECT  0 117.855 18.954 117.99 ;
    LAYER M1 ;
     RECT  0 0.531 18.954 117.999 ;
    LAYER M2 ;
     RECT  0 0.531 18.954 117.999 ;
    LAYER M3 ;
     RECT  4.752 0.187 5.058 0.235 ;
     RECT  10.152 0.187 10.17 0.317 ;
     RECT  6.012 0.187 6.03 0.379 ;
     RECT  4.68 0.235 5.058 0.523 ;
     RECT  6.012 0.379 6.138 0.523 ;
     RECT  11.196 0.379 11.214 0.523 ;
     RECT  7.92 0.187 8.406 0.571 ;
     RECT  12.24 0.187 12.258 0.571 ;
     RECT  7.848 0.571 8.406 0.619 ;
     RECT  12.24 0.571 12.582 0.619 ;
     RECT  16.455 0.523 16.545 0.619 ;
     RECT  4.68 0.523 6.138 0.667 ;
     RECT  0.255 0.523 0.345 0.793 ;
     RECT  11.055 0.523 11.214 0.793 ;
     RECT  16.455 0.619 16.614 0.793 ;
     RECT  16.455 0.793 16.737 0.811 ;
     RECT  15.984 0.811 16.737 0.949 ;
     RECT  12.24 0.619 12.762 0.955 ;
     RECT  14.652 0.571 14.922 1.021 ;
     RECT  15.696 0.949 16.737 1.021 ;
     RECT  3.42 0.187 3.438 1.147 ;
     RECT  4.68 0.667 6.282 1.147 ;
     RECT  7.02 0.619 7.038 1.147 ;
     RECT  7.848 0.619 8.658 1.147 ;
     RECT  9.684 0.571 10.134 1.147 ;
     RECT  11.055 0.793 11.337 1.147 ;
     RECT  12.096 0.955 12.762 1.147 ;
     RECT  13.86 0.571 13.878 1.147 ;
     RECT  14.652 1.021 16.737 1.147 ;
     RECT  3.348 1.147 11.337 1.525 ;
     RECT  12.096 1.147 16.737 1.525 ;
     RECT  3.348 1.525 16.737 1.561 ;
     RECT  2.772 1.561 16.737 2.129 ;
     RECT  2.772 2.129 8.514 2.291 ;
     RECT  3.816 2.291 8.514 2.831 ;
     RECT  4.356 2.831 8.514 2.875 ;
     RECT  2.772 2.291 2.79 2.939 ;
     RECT  4.356 2.875 8.586 3.181 ;
     RECT  4.356 3.181 8.622 3.209 ;
     RECT  5.544 3.209 8.622 3.299 ;
     RECT  5.544 3.299 8.586 3.371 ;
     RECT  9.396 2.129 16.737 3.371 ;
     RECT  4.356 3.209 4.77 3.389 ;
     RECT  5.544 3.371 8.514 3.389 ;
     RECT  9.396 3.371 12.474 3.389 ;
     RECT  13.212 3.371 14.202 3.389 ;
     RECT  14.94 3.371 16.737 3.389 ;
     RECT  7.704 3.389 8.514 3.437 ;
     RECT  9.396 3.389 12.294 3.839 ;
     RECT  7.704 3.437 8.262 3.965 ;
     RECT  4.464 3.389 4.77 3.979 ;
     RECT  5.544 3.389 6.822 3.979 ;
     RECT  13.428 3.389 13.878 4.555 ;
     RECT  14.94 3.389 15.102 4.555 ;
     RECT  15.84 3.389 16.737 4.555 ;
     RECT  13.428 4.555 16.737 4.877 ;
     RECT  4.464 3.979 6.822 5.369 ;
     RECT  13.428 4.877 15.102 5.729 ;
     RECT  14.94 5.729 15.102 5.881 ;
     RECT  15.84 4.877 16.737 5.881 ;
     RECT  4.464 5.369 4.77 6.859 ;
     RECT  5.544 5.369 6.822 6.859 ;
     RECT  4.464 6.859 6.822 6.881 ;
     RECT  4.464 6.881 6.75 7.435 ;
     RECT  13.428 5.729 13.878 7.771 ;
     RECT  10.224 3.839 12.294 7.933 ;
     RECT  13.14 7.771 13.878 7.933 ;
     RECT  7.704 3.965 8.226 7.997 ;
     RECT  4.284 7.435 6.75 8.239 ;
     RECT  4.284 8.239 7.002 8.339 ;
     RECT  4.356 8.339 7.002 8.465 ;
     RECT  7.74 7.997 8.226 8.509 ;
     RECT  7.74 8.509 8.514 8.539 ;
     RECT  9.396 3.839 9.414 8.539 ;
     RECT  4.572 8.465 7.002 8.699 ;
     RECT  10.224 7.933 13.878 8.771 ;
     RECT  5.472 8.699 7.002 8.779 ;
     RECT  7.74 8.539 9.414 8.779 ;
     RECT  4.572 8.699 4.698 8.879 ;
     RECT  13.14 8.771 13.878 8.909 ;
     RECT  13.428 8.909 13.878 9.509 ;
     RECT  10.224 8.771 12.294 9.661 ;
     RECT  10.224 9.661 12.33 9.691 ;
     RECT  5.472 8.779 9.414 10.201 ;
     RECT  10.188 9.691 12.33 10.201 ;
     RECT  5.472 10.201 12.33 10.471 ;
     RECT  13.428 9.509 13.59 10.471 ;
     RECT  14.94 5.881 16.737 11.011 ;
     RECT  14.796 11.011 16.737 11.435 ;
     RECT  4.68 8.879 4.698 12.857 ;
     RECT  5.472 10.471 13.59 12.865 ;
     RECT  4.824 12.865 13.59 13.019 ;
     RECT  9.252 13.019 13.59 15.019 ;
     RECT  14.94 11.435 16.737 15.019 ;
     RECT  9.252 15.019 16.737 15.059 ;
     RECT  9.252 15.059 13.59 16.259 ;
     RECT  5.472 13.019 8.514 16.979 ;
     RECT  9.396 16.259 13.59 17.083 ;
     RECT  14.508 15.059 16.737 17.083 ;
     RECT  9.396 17.083 16.737 18.059 ;
     RECT  5.655 16.979 8.514 20.309 ;
     RECT  14.508 18.059 16.737 20.587 ;
     RECT  9.396 18.059 13.59 20.731 ;
     RECT  14.364 20.587 16.737 20.731 ;
     RECT  9.396 20.731 16.737 21.115 ;
     RECT  9.252 21.115 16.737 21.155 ;
     RECT  5.655 20.309 8.226 21.163 ;
     RECT  9.252 21.155 13.662 21.197 ;
     RECT  5.292 21.163 8.226 21.631 ;
     RECT  9.252 21.197 13.626 21.659 ;
     RECT  9.324 21.659 13.626 21.677 ;
     RECT  9.396 21.677 13.626 22.171 ;
     RECT  14.508 21.155 16.737 22.171 ;
     RECT  9.396 22.171 16.737 22.208 ;
     RECT  5.112 21.631 8.226 22.649 ;
     RECT  5.22 22.649 8.226 22.781 ;
     RECT  9.396 22.208 13.59 23.125 ;
     RECT  14.508 22.208 16.737 23.125 ;
     RECT  9.396 23.125 16.737 23.189 ;
     RECT  5.655 22.781 8.226 23.512 ;
     RECT  5.364 23.512 8.226 23.549 ;
     RECT  14.184 23.189 16.737 24.205 ;
     RECT  13.752 24.205 16.737 24.269 ;
     RECT  5.616 23.549 8.226 24.331 ;
     RECT  5.544 24.331 8.226 25.099 ;
     RECT  9.396 23.189 12.978 25.099 ;
     RECT  5.292 25.099 12.978 25.439 ;
     RECT  5.292 25.439 8.406 25.591 ;
     RECT  9.18 25.439 12.978 25.672 ;
     RECT  9.18 25.672 13.122 25.861 ;
     RECT  13.968 24.269 16.737 25.861 ;
     RECT  9.18 25.861 16.737 26.249 ;
     RECT  5.112 25.591 8.406 26.429 ;
     RECT  5.544 26.429 8.406 26.525 ;
     RECT  5.655 26.525 8.406 26.671 ;
     RECT  9.18 26.249 12.978 26.671 ;
     RECT  5.655 26.671 12.978 27.329 ;
     RECT  9.144 27.329 12.978 27.599 ;
     RECT  5.655 27.329 8.226 28.507 ;
     RECT  9.36 27.599 12.978 28.507 ;
     RECT  5.655 28.507 12.978 28.679 ;
     RECT  9.396 28.679 12.978 29.759 ;
     RECT  5.655 28.679 8.658 31.963 ;
     RECT  9.432 29.759 12.978 31.963 ;
     RECT  5.655 31.963 12.978 32.477 ;
     RECT  13.968 26.249 16.737 33.043 ;
     RECT  9.432 32.477 12.978 33.115 ;
     RECT  13.968 33.043 16.794 33.809 ;
     RECT  9.432 33.115 13.158 33.961 ;
     RECT  9.432 33.961 13.194 34.079 ;
     RECT  9.432 34.079 12.978 36.391 ;
     RECT  13.968 33.809 16.737 36.472 ;
     RECT  13.968 36.472 16.938 36.661 ;
     RECT  17.748 33.925 17.766 36.661 ;
     RECT  9.432 36.391 13.086 37.049 ;
     RECT  9.432 37.049 12.978 37.471 ;
     RECT  5.655 32.477 8.658 37.627 ;
     RECT  9.396 37.471 12.978 37.627 ;
     RECT  5.655 37.627 12.978 38.632 ;
     RECT  13.968 36.661 17.766 38.632 ;
     RECT  5.655 38.632 17.766 38.669 ;
     RECT  5.655 38.669 12.978 39.979 ;
     RECT  5.655 39.979 13.05 40.019 ;
     RECT  13.968 38.669 17.766 40.171 ;
     RECT  5.655 40.019 12.978 40.829 ;
     RECT  9.072 40.829 12.978 41.099 ;
     RECT  9.396 41.099 12.978 42.151 ;
     RECT  13.896 40.171 17.766 42.151 ;
     RECT  5.655 40.829 8.298 42.565 ;
     RECT  9.396 42.151 17.766 42.565 ;
     RECT  5.655 42.565 17.766 42.605 ;
     RECT  5.655 42.605 8.298 66.901 ;
     RECT  9.324 42.605 17.766 66.901 ;
     RECT  5.655 66.901 17.766 67.289 ;
     RECT  5.655 67.289 8.298 69.421 ;
     RECT  9.324 67.289 17.766 69.421 ;
     RECT  5.655 69.421 17.766 71.501 ;
     RECT  9.324 71.501 17.766 72.565 ;
     RECT  9.072 72.565 17.766 72.605 ;
     RECT  9.252 72.605 17.766 72.959 ;
     RECT  5.655 71.501 8.298 74.659 ;
     RECT  5.655 74.659 8.334 74.731 ;
     RECT  9.324 72.959 17.766 74.731 ;
     RECT  5.655 74.731 17.766 75.389 ;
     RECT  5.655 75.389 8.586 77.431 ;
     RECT  9.324 75.389 17.766 77.431 ;
     RECT  5.655 77.431 17.766 82.987 ;
     RECT  18.54 33.961 18.558 82.987 ;
     RECT  5.655 82.987 18.558 83.219 ;
     RECT  5.655 83.219 17.802 83.275 ;
     RECT  5.256 83.275 17.802 83.759 ;
     RECT  5.655 83.759 17.766 84.847 ;
     RECT  5.544 84.847 17.766 84.893 ;
     RECT  5.655 84.893 17.766 93.901 ;
     RECT  18.54 83.219 18.558 93.901 ;
     RECT  5.655 93.901 18.558 94.559 ;
     RECT  5.655 94.559 18.486 95.369 ;
     RECT  5.655 95.369 18.198 96.989 ;
     RECT  5.655 96.989 18.09 99.197 ;
     RECT  5.655 99.197 17.658 99.787 ;
     RECT  5.4 99.787 17.658 100.273 ;
     RECT  5.22 100.273 17.658 100.939 ;
     RECT  5.04 100.939 17.658 101.461 ;
     RECT  4.86 101.461 17.658 101.849 ;
     RECT  3.924 101.947 3.942 101.993 ;
     RECT  5.148 101.849 17.658 102.659 ;
     RECT  5.655 102.659 17.658 103.621 ;
     RECT  5.655 103.621 17.694 104.549 ;
     RECT  5.655 104.549 17.658 108.211 ;
     RECT  5.544 108.211 17.658 108.985 ;
     RECT  5.544 108.985 17.694 110.335 ;
     RECT  5.544 110.335 17.73 114.605 ;
     RECT  5.544 114.605 17.658 114.653 ;
     RECT  5.544 114.653 17.478 114.781 ;
     RECT  4.968 114.781 17.478 114.845 ;
     RECT  5.655 114.845 17.478 114.989 ;
     RECT  4.14 102.001 4.158 116.699 ;
     RECT  8.892 114.989 17.478 116.699 ;
     RECT  5.655 114.989 8.154 116.815 ;
     RECT  8.892 116.699 11.43 116.815 ;
     RECT  12.312 116.699 17.478 116.909 ;
     RECT  12.6 116.909 17.37 116.957 ;
     RECT  12.996 116.957 17.37 117.437 ;
     RECT  12.996 117.437 17.334 117.533 ;
     RECT  0.255 0.793 0.537 117.737 ;
     RECT  0.447 117.737 0.537 118.007 ;
     RECT  5.256 116.815 11.43 118.007 ;
     RECT  6.228 118.007 11.43 118.013 ;
     RECT  12.996 117.533 15.246 118.013 ;
     RECT  16.02 117.533 17.334 118.013 ;
     RECT  7.884 118.013 9.45 118.061 ;
     RECT  10.188 118.013 10.818 118.061 ;
     RECT  13.176 118.013 14.202 118.061 ;
     RECT  15.12 118.013 15.246 118.061 ;
     RECT  5.256 118.007 5.274 118.109 ;
     RECT  7.884 118.061 8.766 118.109 ;
     RECT  10.188 118.061 10.71 118.157 ;
     RECT  13.176 118.061 14.094 118.157 ;
     RECT  13.176 118.157 13.986 118.205 ;
     RECT  16.02 118.013 17.046 118.445 ;
     RECT  7.884 118.109 7.902 118.685 ;
     RECT  8.748 118.109 8.766 118.685 ;
     RECT  10.188 118.157 10.206 118.685 ;
     RECT  13.176 118.205 13.338 118.685 ;
     RECT  15.84 118.555 15.858 118.685 ;
     RECT  17.028 118.445 17.046 118.685 ;
     RECT  13.32 118.685 13.338 118.733 ;
    LAYER M4 ;
     RECT  0.248 0.528 0.352 117.732 ;
     RECT  0.352 0.798 0.44 117.732 ;
     RECT  0.44 0.798 0.544 118.002 ;
     RECT  3.293 1.152 3.365 1.176 ;
     RECT  3.365 0.192 3.449 1.176 ;
     RECT  3.449 0.576 3.556 1.176 ;
     RECT  3.884 101.952 3.971 101.976 ;
     RECT  3.556 0.576 3.973 1.224 ;
     RECT  3.973 0.576 4.165 1.272 ;
     RECT  3.836 2.688 4.165 2.712 ;
     RECT  4.165 0.576 4.268 2.712 ;
     RECT  4.229 7.44 4.313 7.464 ;
     RECT  4.268 0.576 4.345 2.808 ;
     RECT  4.345 0.576 4.493 3.384 ;
     RECT  4.493 0.576 4.549 1.272 ;
     RECT  4.549 0.192 4.565 1.272 ;
     RECT  4.493 2.688 4.643 3.384 ;
     RECT  5.125 23.52 5.209 23.544 ;
     RECT  5.125 21.168 5.489 21.192 ;
     RECT  5.209 22.752 5.489 23.544 ;
     RECT  5.125 25.104 5.489 25.128 ;
     RECT  4.549 100.944 5.509 100.968 ;
     RECT  4.565 0.192 5.648 1.224 ;
     RECT  4.643 2.688 5.648 2.808 ;
     RECT  4.949 3.984 5.648 4.008 ;
     RECT  4.453 6.864 5.648 6.888 ;
     RECT  5.489 21.168 5.648 25.128 ;
     RECT  5.489 26.496 5.648 26.52 ;
     RECT  5.125 83.28 5.648 83.304 ;
     RECT  5.489 84.864 5.648 84.888 ;
     RECT  5.125 99.792 5.648 99.816 ;
     RECT  5.509 100.944 5.648 101.448 ;
     RECT  4.957 114.816 5.648 114.84 ;
     RECT  5.245 118.08 5.648 118.104 ;
     RECT  5.648 0.192 5.944 118.104 ;
     RECT  5.944 114.576 6.035 118.104 ;
     RECT  5.944 0.192 6.041 3.432 ;
     RECT  6.041 0.288 6.083 3.432 ;
     RECT  5.944 33.12 6.083 34.776 ;
     RECT  5.944 92.784 6.083 92.808 ;
     RECT  5.944 106.896 6.085 107.832 ;
     RECT  6.083 0.384 6.11 3.432 ;
     RECT  6.11 0.384 6.149 3.384 ;
     RECT  6.083 33.12 6.149 33.864 ;
     RECT  6.149 0.576 6.193 3.384 ;
     RECT  5.944 104.256 6.265 104.28 ;
     RECT  6.085 106.896 6.323 107.256 ;
     RECT  6.193 0.576 6.329 3.192 ;
     RECT  6.149 33.12 6.329 33.144 ;
     RECT  5.944 100.368 6.337 100.392 ;
     RECT  6.329 2.304 6.401 3.192 ;
     RECT  6.035 114.576 6.419 118.008 ;
     RECT  6.419 114.576 6.515 115.176 ;
     RECT  5.944 109.152 6.563 109.176 ;
     RECT  6.323 107.232 6.581 107.256 ;
     RECT  6.419 116.304 6.707 118.008 ;
     RECT  5.944 13.968 6.796 13.992 ;
     RECT  5.944 111.744 6.803 111.768 ;
     RECT  5.944 17.088 6.889 18.072 ;
     RECT  5.944 90.672 6.94 91.32 ;
     RECT  6.94 91.296 6.941 91.32 ;
     RECT  5.944 10.896 6.977 10.92 ;
     RECT  5.944 105.504 7.004 105.528 ;
     RECT  6.956 80.112 7.043 80.136 ;
     RECT  5.944 97.68 7.085 97.704 ;
     RECT  7.004 104.832 7.091 105.528 ;
     RECT  5.944 102.048 7.121 102.792 ;
     RECT  6.889 18.048 7.187 18.072 ;
     RECT  7.045 26.736 7.187 26.76 ;
     RECT  6.707 116.304 7.187 116.376 ;
     RECT  7.091 105.504 7.229 105.528 ;
     RECT  6.329 0.576 7.325 1.224 ;
     RECT  7.121 102.624 7.427 102.792 ;
     RECT  7.427 102.768 7.429 102.792 ;
     RECT  6.401 2.352 7.477 3.192 ;
     RECT  7.405 25.68 7.484 25.704 ;
     RECT  7.484 25.344 7.489 25.704 ;
     RECT  7.429 102.768 7.517 103.224 ;
     RECT  7.436 88.992 7.523 89.016 ;
     RECT  7.429 36.528 7.553 36.552 ;
     RECT  7.489 25.344 7.571 25.368 ;
     RECT  7.187 116.352 7.571 116.376 ;
     RECT  7.532 20.304 7.619 20.328 ;
     RECT  7.532 27.312 7.619 27.336 ;
     RECT  7.325 0.576 7.621 1.272 ;
     RECT  7.477 2.352 7.621 3.384 ;
     RECT  7.549 33.12 7.633 33.144 ;
     RECT  7.621 0.576 7.805 3.384 ;
     RECT  7.429 99.648 7.805 99.672 ;
     RECT  6.707 117.408 7.829 118.008 ;
     RECT  7.805 0.576 7.861 1.656 ;
     RECT  7.805 2.784 7.861 3.384 ;
     RECT  7.801 96.288 7.907 96.312 ;
     RECT  7.861 0.288 7.909 1.656 ;
     RECT  7.868 70.752 7.955 70.776 ;
     RECT  7.868 85.92 7.955 85.944 ;
     RECT  7.937 110.064 7.957 110.088 ;
     RECT  7.861 2.784 7.985 4.008 ;
     RECT  7.429 28.992 7.985 29.016 ;
     RECT  6.515 114.576 8.005 114.84 ;
     RECT  8.005 114.576 8.017 115.176 ;
     RECT  7.937 24.528 8.021 24.552 ;
     RECT  7.957 110.064 8.021 110.808 ;
     RECT  7.517 102.768 8.044 102.792 ;
     RECT  7.964 67.392 8.051 67.416 ;
     RECT  7.964 97.776 8.051 97.8 ;
     RECT  8.017 82.608 8.125 82.632 ;
     RECT  7.909 0.192 8.165 1.656 ;
     RECT  7.957 36.624 8.201 36.648 ;
     RECT  8.021 110.784 8.201 110.808 ;
     RECT  7.985 2.784 8.209 3.96 ;
     RECT  8.156 75.36 8.243 75.384 ;
     RECT  8.209 2.832 8.317 3.96 ;
     RECT  8.125 82.56 8.341 82.632 ;
     RECT  8.165 0.192 8.417 1.224 ;
     RECT  7.957 30.816 8.417 30.84 ;
     RECT  7.957 87.84 8.417 87.864 ;
     RECT  8.317 2.832 8.435 3.432 ;
     RECT  8.053 107.184 8.435 107.208 ;
     RECT  8.341 82.08 8.489 82.632 ;
     RECT  7.045 83.808 8.525 83.832 ;
     RECT  8.435 2.88 8.531 3.432 ;
     RECT  8.444 31.872 8.531 31.896 ;
     RECT  8.513 78.672 8.597 78.696 ;
     RECT  8.513 86.736 8.597 86.76 ;
     RECT  8.513 89.04 8.597 89.064 ;
     RECT  8.017 114.576 8.668 115.224 ;
     RECT  8.588 10.224 8.675 10.248 ;
     RECT  8.593 74.736 8.677 74.76 ;
     RECT  8.293 37.632 8.684 37.656 ;
     RECT  7.829 117.408 8.701 118.68 ;
     RECT  8.684 37.632 8.705 38.184 ;
     RECT  8.636 90.048 8.723 90.072 ;
     RECT  8.668 114.624 8.723 115.224 ;
     RECT  8.705 38.16 8.771 38.184 ;
     RECT  8.533 69.456 8.777 69.48 ;
     RECT  8.701 117.12 8.777 118.68 ;
     RECT  8.725 71.472 8.813 71.496 ;
     RECT  8.533 82.944 8.819 83.592 ;
     RECT  8.732 102.528 8.819 102.552 ;
     RECT  8.732 111.696 8.819 111.72 ;
     RECT  8.777 117.12 8.819 118.584 ;
     RECT  8.819 82.944 8.849 82.968 ;
     RECT  8.773 98.64 8.857 98.664 ;
     RECT  8.723 114.624 8.915 115.176 ;
     RECT  7.813 8.544 8.993 8.568 ;
     RECT  8.917 28.512 9.001 28.536 ;
     RECT  8.533 96.912 9.02 96.936 ;
     RECT  8.972 42.576 9.059 42.6 ;
     RECT  8.972 79.728 9.059 79.752 ;
     RECT  9.02 96.672 9.061 96.936 ;
     RECT  9.013 31.968 9.1 32.472 ;
     RECT  9.013 102.624 9.101 102.648 ;
     RECT  9.02 72.576 9.107 72.6 ;
     RECT  9.061 96.672 9.107 97.368 ;
     RECT  8.417 0.576 9.137 1.224 ;
     RECT  9.107 97.344 9.145 97.368 ;
     RECT  9.061 93.504 9.148 93.528 ;
     RECT  8.677 13.104 9.164 13.128 ;
     RECT  9.089 27.408 9.173 27.432 ;
     RECT  9.1 31.968 9.173 31.992 ;
     RECT  9.089 39.168 9.173 39.192 ;
     RECT  8.915 115.152 9.203 115.176 ;
     RECT  8.819 117.12 9.205 118.104 ;
     RECT  8.533 25.104 9.209 25.128 ;
     RECT  9.109 92.352 9.209 92.376 ;
     RECT  9.157 81.216 9.244 81.24 ;
     RECT  9.212 21.12 9.269 21.144 ;
     RECT  9.164 12.96 9.281 13.128 ;
     RECT  9.269 21.12 9.353 21.672 ;
     RECT  9.353 21.12 9.443 21.576 ;
     RECT  9.109 113.472 9.497 113.496 ;
     RECT  9.445 20.64 9.533 20.664 ;
     RECT  8.531 2.88 9.548 2.904 ;
     RECT  9.589 87.504 9.673 87.528 ;
     RECT  9.673 87.504 9.677 88.392 ;
     RECT  9.457 77.04 9.683 77.064 ;
     RECT  9.673 95.28 9.685 95.304 ;
     RECT  9.281 12.96 9.713 12.984 ;
     RECT  9.665 28.992 9.749 29.016 ;
     RECT  9.685 95.28 9.757 95.784 ;
     RECT  9.685 114 9.877 114.024 ;
     RECT  9.836 68.496 9.923 68.52 ;
     RECT  9.677 88.368 9.923 88.392 ;
     RECT  9.685 33.792 9.929 33.816 ;
     RECT  9.733 64.368 10.001 64.392 ;
     RECT  9.548 2.688 10.021 2.904 ;
     RECT  9.757 95.76 10.037 95.784 ;
     RECT  9.961 90.768 10.045 90.792 ;
     RECT  9.98 59.232 10.067 59.256 ;
     RECT  10.021 2.304 10.076 2.904 ;
     RECT  9.137 0.576 10.097 1.176 ;
     RECT  9.205 116.88 10.133 118.104 ;
     RECT  10.133 116.88 10.141 118.68 ;
     RECT  10.097 0.192 10.181 1.176 ;
     RECT  10.165 6.288 10.213 6.312 ;
     RECT  10.141 116.304 10.217 118.68 ;
     RECT  10.217 116.304 10.259 118.584 ;
     RECT  10.181 0.288 10.468 1.176 ;
     RECT  10.748 61.776 10.825 61.8 ;
     RECT  10.249 26.256 10.837 26.28 ;
     RECT  10.076 2.304 10.885 3.192 ;
     RECT  10.837 25.728 10.933 26.28 ;
     RECT  10.825 61.488 10.933 61.8 ;
     RECT  10.853 62.784 10.933 62.808 ;
     RECT  10.468 0.288 11.048 1.224 ;
     RECT  10.885 2.304 11.048 3.432 ;
     RECT  10.213 6.288 11.048 6.888 ;
     RECT  9.733 9.696 11.048 9.72 ;
     RECT  10.933 25.728 11.048 27.24 ;
     RECT  9.685 30.24 11.048 30.264 ;
     RECT  10.364 36.672 11.048 36.696 ;
     RECT  10.285 47.232 11.048 47.256 ;
     RECT  10.357 53.328 11.048 53.352 ;
     RECT  10.549 55.392 11.048 55.416 ;
     RECT  10.933 61.488 11.048 62.808 ;
     RECT  10.933 65.52 11.048 65.544 ;
     RECT  10.133 69.504 11.048 69.528 ;
     RECT  10.789 75.12 11.048 75.144 ;
     RECT  9.889 79.248 11.048 79.272 ;
     RECT  10.172 90.96 11.048 90.984 ;
     RECT  10.316 97.92 11.048 97.944 ;
     RECT  10.261 100.944 11.048 100.968 ;
     RECT  9.877 114 11.048 114.6 ;
     RECT  10.259 116.304 11.048 118.248 ;
     RECT  11.048 0.288 11.344 118.248 ;
     RECT  11.344 117.984 11.411 118.248 ;
     RECT  11.344 14.208 11.459 14.232 ;
     RECT  11.344 69.984 11.459 70.824 ;
     RECT  11.344 102.624 11.477 102.648 ;
     RECT  11.344 73.584 11.485 73.608 ;
     RECT  11.411 117.984 11.507 118.008 ;
     RECT  11.344 19.344 11.555 19.368 ;
     RECT  11.344 104.304 11.603 104.328 ;
     RECT  11.344 27.936 11.621 27.96 ;
     RECT  11.344 71.808 11.651 71.832 ;
     RECT  11.344 38.688 11.657 39.192 ;
     RECT  11.344 18.096 11.693 18.12 ;
     RECT  11.344 111.312 11.699 112.344 ;
     RECT  11.344 106.8 11.747 106.824 ;
     RECT  11.344 82.8 11.795 82.824 ;
     RECT  11.344 86.352 11.891 86.376 ;
     RECT  11.344 33.312 11.987 33.816 ;
     RECT  11.344 29.088 12.061 29.688 ;
     RECT  11.459 69.984 12.061 70.008 ;
     RECT  11.344 2.496 12.131 3.768 ;
     RECT  11.657 38.688 12.131 38.712 ;
     RECT  11.344 113.424 12.179 113.544 ;
     RECT  11.344 0.288 12.229 1.416 ;
     RECT  11.344 6.864 12.233 6.888 ;
     RECT  12.061 29.664 12.233 29.688 ;
     RECT  11.344 63.216 12.269 63.24 ;
     RECT  11.699 111.744 12.275 112.344 ;
     RECT  12.229 0.192 12.313 1.416 ;
     RECT  12.313 0.576 12.325 1.416 ;
     RECT  12.131 2.496 12.325 3.384 ;
     RECT  11.344 36 12.349 36.024 ;
     RECT  11.344 116.88 12.373 116.904 ;
     RECT  12.325 73.488 12.412 73.512 ;
     RECT  11.344 41.616 12.421 41.64 ;
     RECT  12.38 94.512 12.467 94.536 ;
     RECT  12.409 37.104 12.493 37.128 ;
     RECT  12.421 41.616 12.508 41.928 ;
     RECT  11.344 114.576 12.509 115.128 ;
     RECT  12.337 30.72 12.553 30.744 ;
     RECT  12.553 30.672 12.563 30.744 ;
     RECT  11.344 84.528 12.563 84.552 ;
     RECT  12.508 41.616 12.565 41.64 ;
     RECT  12.373 116.304 12.589 116.904 ;
     RECT  12.325 0.576 12.593 3.384 ;
     RECT  12.509 89.712 12.593 89.736 ;
     RECT  12.509 113.952 12.593 115.128 ;
     RECT  12.517 28.416 12.629 28.44 ;
     RECT  12.517 52.704 12.629 52.728 ;
     RECT  12.563 30.672 12.659 30.696 ;
     RECT  12.517 35.904 12.665 35.928 ;
     RECT  12.517 106.08 12.665 106.104 ;
     RECT  11.987 33.792 12.697 33.816 ;
     RECT  12.613 62.688 12.7 62.712 ;
     RECT  12.661 52.416 12.745 52.44 ;
     RECT  12.517 90.72 12.755 90.744 ;
     RECT  12.661 92.88 12.812 92.904 ;
     RECT  12.757 56.784 12.844 56.808 ;
     RECT  12.757 61.44 12.844 61.464 ;
     RECT  12.757 69.216 12.844 69.24 ;
     RECT  12.589 116.304 12.851 116.952 ;
     RECT  12.812 92.016 12.899 92.904 ;
     RECT  12.899 92.88 12.947 92.904 ;
     RECT  12.517 21.072 12.949 21.096 ;
     RECT  12.949 20.976 13.036 21.096 ;
     RECT  12.853 36.912 13.061 37.032 ;
     RECT  13.061 37.008 13.069 37.032 ;
     RECT  12.913 51.936 13.091 51.96 ;
     RECT  12.593 114.528 13.093 115.128 ;
     RECT  13.021 39.984 13.105 40.008 ;
     RECT  12.985 117.984 13.121 118.008 ;
     RECT  12.697 33.792 13.129 33.864 ;
     RECT  13.045 108.768 13.132 108.792 ;
     RECT  13.052 74.688 13.139 74.712 ;
     RECT  13.093 25.68 13.177 25.704 ;
     RECT  13.093 68.496 13.177 68.52 ;
     RECT  13.1 8.88 13.187 8.904 ;
     RECT  12.275 112.32 13.187 112.344 ;
     RECT  13.121 117.984 13.204 118.68 ;
     RECT  13.129 33.12 13.213 33.864 ;
     RECT  13.129 104.928 13.213 104.952 ;
     RECT  13.141 67.2 13.228 67.224 ;
     RECT  13.196 62.592 13.283 62.616 ;
     RECT  13.093 72.432 13.313 72.456 ;
     RECT  13.141 83.28 13.313 83.304 ;
     RECT  13.244 96.096 13.331 96.12 ;
     RECT  13.244 105.312 13.331 105.336 ;
     RECT  13.204 117.984 13.349 118.728 ;
     RECT  13.349 117.984 13.372 118.584 ;
     RECT  13.309 64.368 13.393 64.392 ;
     RECT  13.036 21.024 13.445 21.096 ;
     RECT  13.285 22.176 13.445 22.2 ;
     RECT  12.593 0.624 13.589 3.384 ;
     RECT  13.141 99.792 13.601 99.816 ;
     RECT  13.093 114.528 13.621 115.224 ;
     RECT  13.445 21.024 13.637 22.2 ;
     RECT  13.213 33.84 13.667 33.864 ;
     RECT  13.561 38.64 13.667 38.664 ;
     RECT  13.621 113.952 13.667 115.224 ;
     RECT  13.589 0.624 13.669 3.96 ;
     RECT  13.669 0.576 13.673 3.96 ;
     RECT  13.637 21.024 13.673 21.192 ;
     RECT  13.669 87.792 13.697 87.816 ;
     RECT  12.851 116.88 13.705 116.952 ;
     RECT  13.372 117.984 13.705 118.2 ;
     RECT  13.673 21.024 13.708 21.048 ;
     RECT  13.621 88.992 13.708 89.016 ;
     RECT  13.673 0.576 13.709 3.384 ;
     RECT  13.669 65.568 13.753 65.592 ;
     RECT  13.669 96.336 13.753 96.36 ;
     RECT  13.669 111.216 13.753 111.24 ;
     RECT  13.669 112.368 13.772 112.392 ;
     RECT  13.667 113.952 13.772 114.6 ;
     RECT  13.697 87.168 13.781 87.816 ;
     RECT  13.724 24.24 13.811 24.264 ;
     RECT  13.733 8.544 13.817 8.568 ;
     RECT  13.637 22.176 13.853 22.2 ;
     RECT  13.669 78.672 13.853 78.696 ;
     RECT  13.772 112.368 13.853 114.6 ;
     RECT  13.853 112.368 13.859 113.16 ;
     RECT  13.841 17.088 13.925 17.112 ;
     RECT  13.859 112.368 13.925 112.392 ;
     RECT  13.909 92.016 13.996 92.04 ;
     RECT  13.709 0.576 14.051 1.656 ;
     RECT  14.053 111.264 14.14 111.288 ;
     RECT  14.108 91.2 14.195 91.224 ;
     RECT  14.156 77.712 14.243 78.024 ;
     RECT  14.065 97.68 14.243 97.704 ;
     RECT  13.201 80.064 14.245 80.088 ;
     RECT  14.093 103.152 14.245 103.176 ;
     RECT  14.245 79.248 14.252 80.088 ;
     RECT  13.781 87.792 14.252 87.816 ;
     RECT  14.243 78 14.257 78.024 ;
     RECT  13.957 4.56 14.285 4.584 ;
     RECT  14.245 103.152 14.329 103.368 ;
     RECT  14.252 15.024 14.339 15.048 ;
     RECT  14.252 79.248 14.339 80.184 ;
     RECT  14.252 87.792 14.339 88.104 ;
     RECT  14.339 79.248 14.393 79.272 ;
     RECT  14.341 20.784 14.428 20.808 ;
     RECT  14.348 48.384 14.435 48.408 ;
     RECT  14.293 57.648 14.465 57.672 ;
     RECT  14.396 28.32 14.483 28.344 ;
     RECT  14.425 26.256 14.509 26.28 ;
     RECT  14.581 112.272 14.668 112.296 ;
     RECT  13.705 116.88 14.675 118.2 ;
     RECT  14.629 50.976 14.716 51 ;
     RECT  14.677 48.48 14.819 48.504 ;
     RECT  14.629 56.256 14.819 56.28 ;
     RECT  14.605 58.752 14.819 58.776 ;
     RECT  14.741 11.376 14.825 11.4 ;
     RECT  14.741 89.712 14.825 89.736 ;
     RECT  14.757 33.888 14.861 33.912 ;
     RECT  14.821 51.888 14.905 51.912 ;
     RECT  14.821 87.264 14.908 87.288 ;
     RECT  14.821 100.368 14.908 100.392 ;
     RECT  14.821 102.384 14.908 102.408 ;
     RECT  14.051 0.576 14.933 1.272 ;
     RECT  13.853 114.576 15.059 114.6 ;
     RECT  14.929 22.8 15.077 22.824 ;
     RECT  14.929 30.768 15.077 30.792 ;
     RECT  14.965 53.472 15.107 53.496 ;
     RECT  14.965 60.768 15.107 60.792 ;
     RECT  14.821 26.832 15.109 26.856 ;
     RECT  14.857 90.624 15.155 90.648 ;
     RECT  15.109 26.832 15.221 26.952 ;
     RECT  13.709 2.688 15.229 3.384 ;
     RECT  15.229 2.688 15.253 3.192 ;
     RECT  15.221 26.832 15.329 26.856 ;
     RECT  14.821 73.488 15.329 73.512 ;
     RECT  14.933 0.624 15.356 1.272 ;
     RECT  15.253 2.544 15.356 3.192 ;
     RECT  15.253 60.816 15.365 60.84 ;
     RECT  15.349 102.336 15.436 102.36 ;
     RECT  15.356 0.624 15.443 3.192 ;
     RECT  15.073 115.68 15.469 115.704 ;
     RECT  15.713 4.56 15.721 4.584 ;
     RECT  15.469 115.68 15.757 115.752 ;
     RECT  14.675 116.928 15.781 118.2 ;
     RECT  15.781 116.928 15.829 118.584 ;
     RECT  15.829 116.928 15.913 118.68 ;
     RECT  15.721 4.56 15.973 4.872 ;
     RECT  15.577 62.64 15.973 62.664 ;
     RECT  15.781 83.616 15.973 83.64 ;
     RECT  15.757 115.44 16.045 115.752 ;
     RECT  15.913 116.928 16.045 118.44 ;
     RECT  16.045 115.44 16.081 118.44 ;
     RECT  15.973 83.04 16.117 83.64 ;
     RECT  15.443 0.624 16.448 1.224 ;
     RECT  15.443 2.352 16.448 3.192 ;
     RECT  15.973 4.56 16.448 5.736 ;
     RECT  15.541 8.352 16.448 8.376 ;
     RECT  16.309 27.312 16.448 27.336 ;
     RECT  15.397 30.24 16.448 30.264 ;
     RECT  16.309 31.536 16.448 31.56 ;
     RECT  15.397 32.544 16.448 32.568 ;
     RECT  15.973 41.664 16.448 41.688 ;
     RECT  15.973 46.464 16.448 46.488 ;
     RECT  16.309 56.256 16.448 56.28 ;
     RECT  15.973 62.64 16.448 62.76 ;
     RECT  15.973 68.352 16.448 68.376 ;
     RECT  15.397 72.192 16.448 72.216 ;
     RECT  15.505 75.264 16.448 75.288 ;
     RECT  15.973 77.568 16.448 78.12 ;
     RECT  15.829 80.16 16.448 80.184 ;
     RECT  16.117 83.04 16.448 83.832 ;
     RECT  15.397 88.416 16.448 88.44 ;
     RECT  16.289 91.824 16.448 91.848 ;
     RECT  16.268 99.36 16.448 99.384 ;
     RECT  16.153 102.576 16.448 102.6 ;
     RECT  16.076 103.584 16.448 103.608 ;
     RECT  16.309 105.408 16.448 105.432 ;
     RECT  15.884 109.68 16.448 109.704 ;
     RECT  16.081 114.576 16.448 118.44 ;
     RECT  16.448 0.528 16.552 118.44 ;
     RECT  16.552 0.624 16.625 118.44 ;
     RECT  16.625 0.798 16.744 118.44 ;
     RECT  16.744 102.048 16.883 102.072 ;
     RECT  16.744 115.68 16.883 118.44 ;
     RECT  16.744 92.832 16.931 92.856 ;
     RECT  16.883 116.256 16.931 118.44 ;
     RECT  16.744 36.48 16.949 36.504 ;
     RECT  16.931 116.448 16.973 118.44 ;
     RECT  16.744 63.792 17.027 63.816 ;
     RECT  16.973 116.448 17.057 118.68 ;
     RECT  17.057 116.448 17.075 118.584 ;
     RECT  16.744 108.288 17.129 108.312 ;
     RECT  16.744 113.424 17.129 114.648 ;
     RECT  16.744 104.544 17.165 104.568 ;
     RECT  17.075 116.448 17.363 118.008 ;
     RECT  16.744 94.992 17.404 95.016 ;
     RECT  17.363 116.448 17.459 117.432 ;
     RECT  16.744 86.064 17.555 86.088 ;
     RECT  17.129 114.576 17.747 114.648 ;
     RECT  17.459 116.88 17.843 117.432 ;
     RECT  16.744 82.992 17.885 83.016 ;
     RECT  17.747 114.576 17.939 114.6 ;
     RECT  17.129 113.424 18.035 113.448 ;
     RECT  18.044 99.168 18.131 99.192 ;
     RECT  17.843 116.88 18.227 116.904 ;
     RECT  18.277 118.56 18.419 118.584 ;
    LAYER M5 ;
     RECT  3.312 0.144 15.624 0.517 ;
     RECT  0.24 0.517 0.36 0.787 ;
     RECT  3.312 0.517 16.56 0.787 ;
     RECT  3.312 0.787 16.752 1.187 ;
     RECT  3.6 1.187 16.752 1.235 ;
     RECT  3.984 1.235 6.216 1.283 ;
     RECT  7.344 1.235 15.432 1.283 ;
     RECT  7.632 1.283 14.04 1.667 ;
     RECT  15.408 1.283 15.432 2.293 ;
     RECT  16.44 1.235 16.752 2.293 ;
     RECT  15.408 2.293 16.752 2.533 ;
     RECT  4.176 1.283 6.216 2.643 ;
     RECT  7.728 1.667 13.992 2.643 ;
     RECT  15.264 2.533 16.752 2.643 ;
     RECT  3.888 2.643 6.216 2.731 ;
     RECT  4.272 2.731 6.216 2.783 ;
     RECT  7.728 2.643 16.752 2.783 ;
     RECT  4.272 2.783 16.752 3.115 ;
     RECT  4.272 3.115 6.6 3.243 ;
     RECT  4.272 3.243 6.168 3.435 ;
     RECT  7.68 3.115 16.752 3.435 ;
     RECT  4.272 3.435 6.072 3.563 ;
     RECT  13.296 3.435 13.992 4.595 ;
     RECT  15.744 3.435 16.752 4.595 ;
     RECT  15.984 4.595 16.752 5.747 ;
     RECT  4.272 3.563 5.952 6.899 ;
     RECT  7.824 3.435 12.216 6.899 ;
     RECT  4.272 6.899 4.296 7.475 ;
     RECT  16.44 5.747 16.752 8.341 ;
     RECT  15.552 8.341 16.752 8.555 ;
     RECT  7.824 6.899 9.768 8.579 ;
     RECT  13.296 4.595 13.896 8.851 ;
     RECT  13.152 8.851 13.896 8.939 ;
     RECT  8.304 8.579 9.768 9.731 ;
     RECT  5.64 6.899 5.952 10.885 ;
     RECT  5.64 10.885 6.552 10.987 ;
     RECT  13.296 8.939 13.896 11.317 ;
     RECT  13.296 11.317 14.808 11.411 ;
     RECT  8.304 9.731 9.192 12.917 ;
     RECT  8.304 12.917 9.24 13.005 ;
     RECT  5.64 10.987 5.952 13.957 ;
     RECT  5.64 13.957 6.744 14.059 ;
     RECT  11.04 6.899 11.352 14.163 ;
     RECT  11.04 14.163 11.448 14.251 ;
     RECT  13.296 11.411 13.896 14.995 ;
     RECT  13.296 14.995 14.328 15.083 ;
     RECT  5.64 14.059 5.952 16.565 ;
     RECT  5.64 16.565 6.696 17.123 ;
     RECT  13.296 15.083 13.896 17.123 ;
     RECT  11.04 14.251 11.352 17.653 ;
     RECT  11.04 17.653 11.64 18.131 ;
     RECT  7.152 18.037 7.176 18.219 ;
     RECT  11.04 18.131 11.352 19.317 ;
     RECT  11.04 19.317 11.544 19.405 ;
     RECT  8.304 13.005 9.192 20.277 ;
     RECT  7.584 20.277 9.192 20.365 ;
     RECT  8.304 20.365 9.192 20.591 ;
     RECT  8.304 20.591 9.48 20.675 ;
     RECT  13.296 17.123 13.608 20.725 ;
     RECT  13.296 20.725 14.376 20.819 ;
     RECT  13.296 20.819 13.656 20.947 ;
     RECT  12.96 20.947 13.656 21.061 ;
     RECT  5.64 17.123 5.952 21.109 ;
     RECT  12.528 21.061 13.656 21.163 ;
     RECT  5.136 21.109 5.952 21.203 ;
     RECT  13.296 21.163 13.656 21.241 ;
     RECT  5.52 21.203 5.952 21.493 ;
     RECT  8.304 20.675 9.432 21.611 ;
     RECT  8.304 21.611 9.336 21.683 ;
     RECT  13.296 21.241 13.608 21.731 ;
     RECT  5.52 21.493 6.888 21.931 ;
     RECT  13.296 21.731 13.32 22.211 ;
     RECT  5.52 21.931 5.952 22.741 ;
     RECT  5.232 22.741 5.952 23.509 ;
     RECT  5.136 23.509 5.952 23.595 ;
     RECT  13.776 23.925 13.8 24.299 ;
     RECT  8.304 21.683 9.192 24.479 ;
     RECT  5.52 23.595 5.952 25.055 ;
     RECT  5.136 25.055 5.952 25.139 ;
     RECT  7.968 24.479 9.192 25.139 ;
     RECT  7.968 25.139 8.328 25.299 ;
     RECT  7.536 25.299 8.328 25.631 ;
     RECT  11.04 19.405 11.352 25.653 ;
     RECT  7.44 25.631 8.328 25.715 ;
     RECT  13.104 25.631 13.128 25.715 ;
     RECT  10.848 25.653 11.352 26.207 ;
     RECT  10.272 26.207 11.352 26.291 ;
     RECT  14.448 26.207 14.472 26.291 ;
     RECT  5.64 25.139 5.952 26.485 ;
     RECT  5.52 26.485 5.952 26.569 ;
     RECT  14.832 26.805 14.856 26.869 ;
     RECT  14.832 26.869 15.144 26.893 ;
     RECT  15.12 26.893 15.144 26.963 ;
     RECT  7.152 26.725 7.176 27.051 ;
     RECT  8.304 25.715 8.328 27.283 ;
     RECT  16.44 8.555 16.752 27.283 ;
     RECT  10.944 26.291 11.352 27.307 ;
     RECT  7.584 27.283 8.328 27.359 ;
     RECT  7.584 27.359 9.144 27.371 ;
     RECT  16.32 27.283 16.752 27.371 ;
     RECT  8.304 27.371 9.144 27.443 ;
     RECT  11.04 27.307 11.352 27.829 ;
     RECT  11.04 27.829 11.544 27.971 ;
     RECT  8.304 27.443 8.328 28.405 ;
     RECT  14.448 28.309 14.472 28.459 ;
     RECT  12.528 28.405 12.552 28.489 ;
     RECT  8.304 28.405 8.952 28.547 ;
     RECT  8.304 28.547 8.328 28.981 ;
     RECT  11.04 27.971 11.352 29.039 ;
     RECT  7.44 28.981 8.328 29.065 ;
     RECT  9.696 28.981 9.72 29.065 ;
     RECT  11.04 29.039 12.024 29.615 ;
     RECT  11.04 29.615 12.168 29.699 ;
     RECT  9.696 30.191 9.72 30.275 ;
     RECT  15.408 30.191 15.432 30.275 ;
     RECT  12.624 30.623 12.648 30.675 ;
     RECT  12.528 30.675 12.648 30.707 ;
     RECT  12.528 30.707 12.552 30.763 ;
     RECT  8.304 29.065 8.328 30.805 ;
     RECT  7.968 30.805 8.328 30.891 ;
     RECT  16.44 27.371 16.752 31.507 ;
     RECT  16.32 31.507 16.752 31.595 ;
     RECT  8.304 30.891 8.328 31.827 ;
     RECT  8.304 31.827 8.52 31.919 ;
     RECT  8.304 31.919 9.144 32.003 ;
     RECT  8.304 32.003 9.048 32.491 ;
     RECT  15.408 32.495 15.432 32.579 ;
     RECT  5.64 26.569 5.952 33.071 ;
     RECT  8.304 32.491 8.328 33.071 ;
     RECT  5.64 33.071 6.312 33.155 ;
     RECT  7.584 33.071 8.328 33.155 ;
     RECT  11.04 29.699 11.352 33.263 ;
     RECT  11.04 33.263 11.976 33.781 ;
     RECT  13.152 33.071 13.176 33.781 ;
     RECT  9.696 33.781 9.72 33.865 ;
     RECT  11.04 33.781 13.656 33.865 ;
     RECT  12.72 33.865 13.656 33.875 ;
     RECT  14.784 33.839 14.808 33.923 ;
     RECT  5.64 33.155 6.072 34.795 ;
     RECT  11.04 33.865 11.352 35.951 ;
     RECT  12.528 35.893 12.552 35.951 ;
     RECT  11.04 35.951 12.552 36.035 ;
     RECT  8.304 33.155 8.328 36.469 ;
     RECT  16.44 31.595 16.752 36.469 ;
     RECT  16.44 36.469 16.872 36.553 ;
     RECT  7.44 36.469 8.328 36.563 ;
     RECT  11.04 36.035 11.352 36.627 ;
     RECT  7.968 36.563 8.328 36.659 ;
     RECT  10.416 36.627 11.352 36.715 ;
     RECT  12.864 36.883 12.888 36.959 ;
     RECT  12.864 36.959 13.032 37.043 ;
     RECT  12.432 37.045 12.456 37.139 ;
     RECT  8.304 36.659 8.328 37.667 ;
     RECT  8.736 38.133 8.76 38.221 ;
     RECT  11.04 36.715 11.352 38.645 ;
     RECT  13.632 38.581 13.656 38.675 ;
     RECT  11.04 38.645 12.12 38.733 ;
     RECT  9.12 39.157 9.144 39.241 ;
     RECT  11.04 38.733 11.448 39.241 ;
     RECT  13.056 39.925 13.08 40.019 ;
     RECT  11.04 39.241 11.352 41.567 ;
     RECT  11.04 41.567 11.496 41.651 ;
     RECT  12.528 41.567 12.552 41.651 ;
     RECT  16.44 36.553 16.752 41.653 ;
     RECT  15.984 41.653 16.752 41.737 ;
     RECT  12.432 41.875 12.456 41.963 ;
     RECT  9.024 42.565 9.048 42.667 ;
     RECT  16.44 41.737 16.752 46.453 ;
     RECT  15.984 46.453 16.752 46.537 ;
     RECT  11.04 41.651 11.352 47.221 ;
     RECT  10.32 47.221 11.352 47.305 ;
     RECT  14.4 48.339 14.424 48.427 ;
     RECT  14.784 48.431 14.808 48.515 ;
     RECT  14.64 50.741 14.664 51.051 ;
     RECT  14.832 51.877 14.856 51.961 ;
     RECT  13.056 51.887 13.08 51.971 ;
     RECT  12.672 52.405 12.696 52.489 ;
     RECT  12.528 52.693 12.552 52.779 ;
     RECT  11.04 47.305 11.352 53.301 ;
     RECT  10.368 53.301 11.352 53.389 ;
     RECT  15.072 53.461 15.096 53.547 ;
     RECT  11.04 53.389 11.352 55.349 ;
     RECT  10.56 55.349 11.352 55.437 ;
     RECT  16.44 46.537 16.752 56.181 ;
     RECT  14.784 56.181 14.808 56.211 ;
     RECT  14.64 56.211 14.808 56.291 ;
     RECT  16.32 56.181 16.752 56.291 ;
     RECT  14.64 56.291 14.664 56.299 ;
     RECT  12.768 56.773 12.792 56.875 ;
     RECT  14.304 57.589 14.328 57.683 ;
     RECT  14.784 58.741 14.808 58.825 ;
     RECT  10.032 59.221 10.056 59.307 ;
     RECT  15.072 60.757 15.096 60.767 ;
     RECT  15.072 60.767 15.288 60.843 ;
     RECT  15.264 60.843 15.288 60.851 ;
     RECT  11.04 55.437 11.352 61.477 ;
     RECT  12.768 61.365 12.792 61.547 ;
     RECT  10.848 61.477 11.352 61.765 ;
     RECT  10.8 61.765 11.352 61.867 ;
     RECT  16.44 56.291 16.752 62.629 ;
     RECT  13.248 62.581 13.272 62.639 ;
     RECT  12.624 62.639 13.272 62.723 ;
     RECT  10.848 61.867 11.352 63.205 ;
     RECT  10.848 63.205 12.024 63.289 ;
     RECT  15.6 62.629 16.752 63.781 ;
     RECT  13.248 62.723 13.272 64.357 ;
     RECT  9.744 64.357 9.768 64.441 ;
     RECT  13.248 64.357 13.368 65.519 ;
     RECT  13.248 65.519 13.704 65.603 ;
     RECT  13.248 65.603 13.368 67.155 ;
     RECT  13.152 67.155 13.368 67.243 ;
     RECT  8.016 67.347 8.04 67.435 ;
     RECT  13.248 67.243 13.368 68.447 ;
     RECT  10.848 63.289 11.352 68.485 ;
     RECT  9.888 68.485 11.352 68.587 ;
     RECT  13.104 68.447 13.368 69.205 ;
     RECT  12.768 69.205 13.368 69.291 ;
     RECT  8.544 69.407 8.568 69.491 ;
     RECT  10.176 68.587 11.352 69.973 ;
     RECT  10.176 69.973 12.024 70.059 ;
     RECT  7.92 70.709 7.944 70.797 ;
     RECT  10.176 70.059 11.448 70.835 ;
     RECT  10.176 70.835 11.352 71.797 ;
     RECT  15.6 63.781 17.016 72.181 ;
     RECT  15.408 72.181 17.016 72.265 ;
     RECT  13.248 69.291 13.368 72.373 ;
     RECT  13.104 72.373 13.368 72.467 ;
     RECT  8.736 71.461 8.76 72.531 ;
     RECT  8.736 72.531 9.096 72.619 ;
     RECT  15.6 72.265 17.016 73.439 ;
     RECT  10.176 71.797 11.64 73.461 ;
     RECT  13.248 72.467 13.368 73.461 ;
     RECT  14.832 73.439 17.016 73.523 ;
     RECT  10.176 73.461 13.368 73.549 ;
     RECT  8.736 72.619 8.76 74.677 ;
     RECT  13.248 73.549 13.368 74.677 ;
     RECT  8.64 74.677 8.76 75.317 ;
     RECT  8.208 75.317 8.76 75.405 ;
     RECT  8.736 75.405 8.76 76.981 ;
     RECT  10.176 73.549 11.64 76.981 ;
     RECT  8.736 76.981 11.64 77.075 ;
     RECT  13.104 74.677 13.368 77.701 ;
     RECT  13.104 77.701 14.232 78.073 ;
     RECT  8.736 77.075 8.76 78.645 ;
     RECT  8.544 78.645 8.76 78.733 ;
     RECT  13.104 78.073 13.704 79.199 ;
     RECT  10.176 77.075 11.64 79.237 ;
     RECT  8.736 78.733 8.76 79.699 ;
     RECT  8.736 79.699 9.048 79.787 ;
     RECT  13.104 79.199 14.28 80.149 ;
     RECT  13.104 80.149 14.328 80.235 ;
     RECT  8.736 79.787 8.76 81.171 ;
     RECT  10.128 79.237 11.64 81.171 ;
     RECT  8.736 81.171 11.64 81.259 ;
     RECT  8.736 81.259 8.76 82.069 ;
     RECT  8.352 82.069 8.76 82.549 ;
     RECT  8.208 82.549 8.76 82.597 ;
     RECT  10.128 81.259 11.64 82.789 ;
     RECT  15.6 73.523 17.016 82.933 ;
     RECT  15.6 82.933 17.688 83.027 ;
     RECT  5.64 34.795 5.952 83.231 ;
     RECT  5.136 83.231 5.952 83.315 ;
     RECT  8.112 82.597 8.76 83.509 ;
     RECT  8.112 83.509 8.808 83.603 ;
     RECT  7.008 80.101 7.032 83.759 ;
     RECT  8.112 83.603 8.76 83.759 ;
     RECT  10.128 82.789 11.784 84.469 ;
     RECT  13.104 80.235 13.368 84.469 ;
     RECT  10.128 84.469 13.368 84.563 ;
     RECT  5.64 83.315 5.952 84.853 ;
     RECT  5.52 84.853 5.952 84.937 ;
     RECT  15.6 83.027 17.016 86.053 ;
     RECT  10.128 84.563 11.784 86.341 ;
     RECT  13.104 84.563 13.368 87.157 ;
     RECT  15.6 86.053 17.544 87.215 ;
     RECT  7.008 83.759 8.76 87.221 ;
     RECT  10.128 86.341 11.88 87.221 ;
     RECT  14.832 87.215 17.544 87.299 ;
     RECT  7.008 87.221 11.88 87.539 ;
     RECT  13.104 87.157 13.752 87.797 ;
     RECT  13.104 87.797 14.328 88.115 ;
     RECT  15.6 87.299 17.544 88.367 ;
     RECT  15.408 88.367 17.544 88.451 ;
     RECT  15.6 88.451 17.544 89.653 ;
     RECT  9.888 87.539 11.88 89.701 ;
     RECT  13.104 88.115 13.752 89.701 ;
     RECT  14.784 89.653 17.544 89.747 ;
     RECT  5.64 84.937 5.952 90.613 ;
     RECT  7.008 87.539 8.76 90.613 ;
     RECT  9.888 89.701 13.752 90.795 ;
     RECT  13.104 90.795 13.752 91.125 ;
     RECT  15.12 89.747 17.544 91.125 ;
     RECT  13.104 91.125 17.544 91.235 ;
     RECT  5.64 90.613 8.76 91.331 ;
     RECT  13.104 91.235 13.944 91.987 ;
     RECT  12.864 91.987 13.944 92.075 ;
     RECT  7.008 91.331 8.76 92.341 ;
     RECT  9.888 90.795 11.88 92.341 ;
     RECT  7.008 92.341 11.88 92.425 ;
     RECT  5.64 91.331 5.952 92.661 ;
     RECT  7.008 92.425 8.76 92.661 ;
     RECT  5.64 92.661 8.76 92.819 ;
     RECT  7.008 92.819 8.76 93.493 ;
     RECT  9.888 92.425 11.88 93.493 ;
     RECT  7.008 93.493 11.88 93.803 ;
     RECT  9.888 93.803 11.88 94.453 ;
     RECT  12.912 92.075 13.752 94.453 ;
     RECT  9.888 94.453 13.752 94.547 ;
     RECT  7.008 93.803 8.76 95.221 ;
     RECT  9.888 94.547 11.88 95.221 ;
     RECT  7.008 95.221 11.88 97.417 ;
     RECT  12.912 94.547 13.752 97.631 ;
     RECT  15.12 91.235 17.544 97.631 ;
     RECT  5.64 92.819 5.952 97.669 ;
     RECT  7.008 97.417 8.76 97.669 ;
     RECT  12.912 97.631 17.544 97.715 ;
     RECT  5.64 97.669 8.76 98.613 ;
     RECT  5.64 98.613 8.808 98.701 ;
     RECT  15.12 97.715 17.544 99.157 ;
     RECT  5.64 98.701 8.76 99.743 ;
     RECT  5.136 99.743 8.76 99.827 ;
     RECT  15.12 99.157 18.12 100.319 ;
     RECT  14.832 100.319 18.12 100.403 ;
     RECT  4.56 100.895 4.584 100.979 ;
     RECT  5.64 99.827 8.76 101.395 ;
     RECT  5.52 101.395 8.76 101.483 ;
     RECT  3.936 101.429 3.96 101.987 ;
     RECT  15.12 100.403 18.12 102.005 ;
     RECT  5.64 101.483 8.76 102.197 ;
     RECT  5.64 102.197 8.808 102.613 ;
     RECT  9.888 97.417 11.88 102.613 ;
     RECT  5.64 102.613 11.88 102.763 ;
     RECT  12.912 97.715 13.752 103.141 ;
     RECT  14.832 102.005 18.12 103.141 ;
     RECT  12.912 103.141 18.12 103.379 ;
     RECT  9.888 102.763 11.88 106.031 ;
     RECT  12.912 103.379 13.752 106.031 ;
     RECT  9.888 106.031 13.752 106.115 ;
     RECT  5.64 102.763 8.76 111.157 ;
     RECT  12.912 106.115 13.752 111.221 ;
     RECT  9.888 106.115 11.88 111.733 ;
     RECT  12.912 111.221 14.088 111.733 ;
     RECT  5.64 111.157 8.808 111.757 ;
     RECT  9.888 111.733 14.088 112.261 ;
     RECT  15.12 103.379 18.12 112.261 ;
     RECT  5.64 111.757 8.76 113.461 ;
     RECT  9.888 112.261 18.12 113.461 ;
     RECT  5.64 113.461 18.12 114.035 ;
     RECT  5.64 114.035 8.904 114.805 ;
     RECT  5.088 114.805 8.904 114.889 ;
     RECT  5.64 114.889 8.904 115.141 ;
     RECT  9.888 114.035 18.12 115.141 ;
     RECT  5.64 115.141 18.12 116.869 ;
     RECT  0.24 0.787 0.552 117.743 ;
     RECT  5.64 116.869 18.216 117.743 ;
     RECT  0.432 117.743 0.552 118.013 ;
     RECT  5.832 117.743 18.216 118.013 ;
     RECT  6 118.013 18.216 118.549 ;
     RECT  6 118.549 18.408 118.608 ;
     RECT  18.384 118.608 18.408 118.635 ;
     RECT  7.872 118.608 8.76 118.691 ;
     RECT  10.176 118.608 10.2 118.691 ;
     RECT  13.152 118.608 13.272 118.691 ;
     RECT  15.84 118.608 15.864 118.691 ;
     RECT  16.992 118.608 17.016 118.691 ;
     RECT  13.248 118.691 13.272 118.739 ;
    LAYER M6 ;
     RECT  0 0.996 3.877 1.86 ;
     RECT  3.893 100.352 3.925 100.384 ;
     RECT  3.877 0.996 4.069 2.72 ;
     RECT  0 22.596 4.085 23.46 ;
     RECT  4.069 0.192 4.277 2.72 ;
     RECT  0 81.996 4.277 82.86 ;
     RECT  4.277 0.192 4.334 2.848 ;
     RECT  0 98.196 4.341 99.06 ;
     RECT  3.925 100.352 4.341 101.472 ;
     RECT  4.334 0.192 4.403 3.424 ;
     RECT  0 108.996 4.597 109.86 ;
     RECT  4.403 0.192 4.651 3.296 ;
     RECT  0 103.596 4.661 104.46 ;
     RECT  4.651 0.192 4.715 2.848 ;
     RECT  4.715 0.192 5.099 2.72 ;
     RECT  4.917 21.12 5.171 21.152 ;
     RECT  4.853 25.088 5.171 25.12 ;
     RECT  4.277 81.996 5.171 83.296 ;
     RECT  4.597 107.776 5.237 109.86 ;
     RECT  0 33.396 5.493 34.26 ;
     RECT  4.085 22.596 5.509 23.584 ;
     RECT  5.237 107.776 5.557 110.816 ;
     RECT  5.509 21.76 5.611 24.48 ;
     RECT  4.661 103.596 5.621 105.504 ;
     RECT  5.509 26.496 5.675 26.528 ;
     RECT  5.045 91.264 5.877 91.296 ;
     RECT  0 92.796 5.877 93.66 ;
     RECT  5.493 33.088 5.941 34.26 ;
     RECT  4.341 98.196 5.941 101.472 ;
     RECT  5.621 103.168 5.941 105.504 ;
     RECT  5.941 33.088 6.083 34.784 ;
     RECT  5.877 92.672 6.083 93.66 ;
     RECT  5.557 107.2 6.083 110.816 ;
     RECT  6.037 3.392 6.123 3.552 ;
     RECT  5.877 91.136 6.133 91.296 ;
     RECT  6.123 3.392 6.202 3.424 ;
     RECT  6.083 107.2 6.277 107.232 ;
     RECT  5.941 98.196 6.323 105.504 ;
     RECT  6.277 106.944 6.323 107.232 ;
     RECT  0 11.796 6.517 12.66 ;
     RECT  0 17.196 6.638 18.06 ;
     RECT  6.323 101.44 6.645 105.504 ;
     RECT  6.323 106.944 6.645 106.976 ;
     RECT  6.517 10.944 6.699 12.66 ;
     RECT  6.645 101.44 6.699 106.976 ;
     RECT  6.638 16.576 6.707 18.06 ;
     RECT  6.645 14.016 6.755 14.048 ;
     RECT  0 27.996 6.773 28.86 ;
     RECT  5.099 0.192 6.837 1.86 ;
     RECT  6.565 3.2 6.837 3.232 ;
     RECT  5.611 21.76 6.837 23.46 ;
     RECT  6.133 90.624 6.899 91.296 ;
     RECT  6.699 102.016 6.899 106.784 ;
     RECT  6.837 21.504 6.91 23.46 ;
     RECT  6.899 106.624 6.955 106.784 ;
     RECT  6.965 25.664 7.093 25.696 ;
     RECT  6.773 27.996 7.093 29.024 ;
     RECT  6.707 17.196 7.141 18.06 ;
     RECT  6.899 102.592 7.147 104.864 ;
     RECT  6.955 106.752 7.147 106.784 ;
     RECT  6.323 98.196 7.157 99.744 ;
     RECT  7.141 17.196 7.211 18.208 ;
     RECT  5.171 81.996 7.221 82.86 ;
     RECT  5.509 84.864 7.221 84.896 ;
     RECT  7.093 25.664 7.475 29.024 ;
     RECT  7.285 36.48 7.475 36.512 ;
     RECT  0 87.396 7.477 88.26 ;
     RECT  6.083 92.796 7.541 93.66 ;
     RECT  7.157 96.896 7.571 99.744 ;
     RECT  7.525 25.344 7.595 25.376 ;
     RECT  6.91 21.632 7.605 23.46 ;
     RECT  7.475 26.88 7.659 28.86 ;
     RECT  6.083 33.088 7.659 34.26 ;
     RECT  6.837 0.192 7.669 3.232 ;
     RECT  7.477 87.396 7.669 88.992 ;
     RECT  0 76.596 7.733 77.46 ;
     RECT  6.069 69.44 7.909 69.472 ;
     RECT  0 71.196 7.909 72.06 ;
     RECT  7.221 81.996 7.909 84.896 ;
     RECT  7.605 21.632 8.003 25.12 ;
     RECT  6.709 30.848 8.003 30.88 ;
     RECT  7.477 36.608 8.003 36.64 ;
     RECT  7.909 81.996 8.003 85.92 ;
     RECT  6.083 108.996 8.003 110.816 ;
     RECT  0 65.796 8.005 66.66 ;
     RECT  0 114.396 8.181 115.26 ;
     RECT  7.733 76.596 8.197 78.688 ;
     RECT  7.669 0.192 8.245 3.424 ;
     RECT  8.003 84.864 8.309 85.92 ;
     RECT  7.669 87.396 8.309 89.056 ;
     RECT  8.245 0.192 8.314 4 ;
     RECT  8.245 95.232 8.501 95.264 ;
     RECT  7.571 96.896 8.501 99.06 ;
     RECT  8.314 0.192 8.555 3.424 ;
     RECT  8.003 25.088 8.579 25.12 ;
     RECT  7.909 69.44 8.579 72.06 ;
     RECT  8.197 75.328 8.579 78.688 ;
     RECT  8.309 84.864 8.579 89.056 ;
     RECT  8.579 75.328 8.629 77.46 ;
     RECT  8.579 87.232 8.677 89.056 ;
     RECT  8.555 0.192 8.683 2.848 ;
     RECT  7.147 102.592 8.693 104.46 ;
     RECT  8.629 74.688 8.698 77.46 ;
     RECT  0 38.796 8.725 39.66 ;
     RECT  8.693 102.464 8.773 104.46 ;
     RECT  8.117 31.872 8.811 31.968 ;
     RECT  8.003 81.996 8.821 83.552 ;
     RECT  8.677 87.232 8.821 90.08 ;
     RECT  7.541 92.352 8.821 93.66 ;
     RECT  8.757 111.168 8.83 111.712 ;
     RECT  8.821 81.216 8.875 83.552 ;
     RECT  8.579 84.864 8.875 85.92 ;
     RECT  8.821 87.232 8.875 93.66 ;
     RECT  8.773 102.208 8.875 104.46 ;
     RECT  8.83 111.168 8.875 111.2 ;
     RECT  8.725 38.144 8.939 39.66 ;
     RECT  8.811 31.936 8.949 31.968 ;
     RECT  7.659 33.396 8.949 34.26 ;
     RECT  8.949 31.936 9.059 34.26 ;
     RECT  8.579 70.72 9.061 72.06 ;
     RECT  8.875 90.752 9.061 93.66 ;
     RECT  8.994 79.744 9.067 79.776 ;
     RECT  9.061 90.752 9.067 93.792 ;
     RECT  8.875 102.464 9.067 104.46 ;
     RECT  8.501 95.232 9.107 99.06 ;
     RECT  9.061 70.72 9.131 72.608 ;
     RECT  8.698 75.136 9.131 77.46 ;
     RECT  9.067 92.352 9.131 93.792 ;
     RECT  9.107 95.232 9.131 96.672 ;
     RECT  7.659 27.392 9.155 28.86 ;
     RECT  9.059 31.936 9.155 31.968 ;
     RECT  9.131 92.352 9.155 93.66 ;
     RECT  8.181 113.472 9.155 115.26 ;
     RECT  6.699 11.796 9.186 12.66 ;
     RECT  8.875 81.216 9.203 82.86 ;
     RECT  7.573 20.288 9.253 20.32 ;
     RECT  8.003 21.632 9.253 23.46 ;
     RECT  8.629 10.24 9.259 10.272 ;
     RECT  9.186 11.796 9.451 12.96 ;
     RECT  9.253 20.288 9.451 23.46 ;
     RECT  9.451 20.608 9.491 23.46 ;
     RECT  9.491 21.12 9.579 23.46 ;
     RECT  8.875 87.232 9.635 88.26 ;
     RECT  9.155 27.996 9.653 28.86 ;
     RECT  9.525 30.208 9.653 30.24 ;
     RECT  8.005 65.796 9.717 67.424 ;
     RECT  9.653 27.996 9.731 30.24 ;
     RECT  9.131 95.232 9.731 95.776 ;
     RECT  9.717 65.796 9.771 68.576 ;
     RECT  9.71 64.384 9.779 64.416 ;
     RECT  9.771 68.48 9.963 68.576 ;
     RECT  0 60.396 10.021 61.26 ;
     RECT  8.683 0.192 10.101 2.72 ;
     RECT  9.067 90.752 10.259 90.976 ;
     RECT  9.013 42.624 10.293 42.656 ;
     RECT  9.461 26.24 10.307 26.272 ;
     RECT  8.949 100.928 10.307 100.96 ;
     RECT  10.286 47.232 10.355 47.264 ;
     RECT  9.131 70.72 10.357 72.06 ;
     RECT  10.293 52.736 10.403 53.344 ;
     RECT  10.405 36.672 10.475 36.704 ;
     RECT  10.293 42.496 10.475 42.656 ;
     RECT  10.475 42.496 10.539 42.528 ;
     RECT  10.259 90.752 10.677 90.784 ;
     RECT  10.021 59.264 10.741 61.26 ;
     RECT  10.741 59.264 10.795 61.856 ;
     RECT  9.131 75.136 10.835 75.168 ;
     RECT  10.421 25.664 10.883 25.696 ;
     RECT  10.101 0.192 10.914 3.232 ;
     RECT  9.731 27.996 10.933 28.86 ;
     RECT  10.795 60.396 10.933 61.856 ;
     RECT  10.741 63.232 10.933 63.264 ;
     RECT  9.155 113.984 10.997 115.26 ;
     RECT  10.933 27.264 11.051 28.86 ;
     RECT  9.771 65.796 11.061 66.66 ;
     RECT  11.051 27.84 11.189 28.86 ;
     RECT  10.101 73.536 11.459 73.568 ;
     RECT  9.067 102.592 11.459 104.46 ;
     RECT  10.997 113.472 11.459 115.26 ;
     RECT  7.211 17.196 11.49 18.06 ;
     RECT  9.579 21.12 11.509 21.152 ;
     RECT  11.413 14.208 11.563 14.24 ;
     RECT  11.49 17.196 11.563 19.36 ;
     RECT  11.189 27.84 11.578 29.088 ;
     RECT  9.059 33.396 11.941 34.26 ;
     RECT  9.963 68.48 12.021 68.512 ;
     RECT  10.357 70.016 12.021 72.06 ;
     RECT  10.933 60.396 12.035 63.264 ;
     RECT  12.021 68.48 12.035 72.06 ;
     RECT  8.939 38.796 12.066 39.66 ;
     RECT  12.035 70.784 12.075 72.06 ;
     RECT  10.914 0.192 12.085 3.36 ;
     RECT  11.578 27.996 12.085 29.088 ;
     RECT  12.066 38.656 12.139 39.66 ;
     RECT  12.085 27.996 12.179 29.664 ;
     RECT  11.253 35.904 12.277 35.936 ;
     RECT  11.459 103.596 12.277 104.46 ;
     RECT  12.277 35.904 12.398 36.96 ;
     RECT  11.438 41.6 12.405 41.632 ;
     RECT  12.277 103.596 12.405 104.928 ;
     RECT  11.701 106.816 12.405 106.848 ;
     RECT  9.155 92.796 12.421 93.66 ;
     RECT  12.398 35.904 12.467 37.088 ;
     RECT  12.075 71.196 12.469 72.06 ;
     RECT  12.021 73.472 12.469 73.504 ;
     RECT  12.405 41.6 12.478 41.952 ;
     RECT  12.467 35.904 12.563 37.024 ;
     RECT  10.403 52.736 12.563 52.768 ;
     RECT  10.677 89.728 12.563 90.784 ;
     RECT  12.405 103.596 12.563 106.848 ;
     RECT  12.478 41.6 12.587 41.632 ;
     RECT  9.107 98.196 12.597 99.06 ;
     RECT  12.517 30.656 12.659 30.752 ;
     RECT  0 54.996 12.661 55.86 ;
     RECT  12.661 52.416 12.73 52.448 ;
     RECT  12.563 90.688 12.779 90.72 ;
     RECT  12.661 54.996 12.843 56.864 ;
     RECT  9.203 81.996 12.853 82.86 ;
     RECT  12.517 84.48 12.853 84.512 ;
     RECT  12.421 92.796 12.853 94.496 ;
     RECT  12.563 36.928 12.899 37.024 ;
     RECT  12.035 60.396 12.907 62.752 ;
     RECT  12.085 0.192 12.971 3.808 ;
     RECT  11.509 20.992 12.995 21.152 ;
     RECT  12.899 36.992 13.043 37.024 ;
     RECT  12.139 38.796 13.045 39.66 ;
     RECT  8.003 108.996 13.045 109.86 ;
     RECT  12.853 58.752 13.099 58.784 ;
     RECT  11.061 65.536 13.109 66.66 ;
     RECT  12.035 68.48 13.109 69.28 ;
     RECT  13.045 38.796 13.114 39.968 ;
     RECT  12.917 25.664 13.139 25.696 ;
     RECT  12.469 71.196 13.139 73.504 ;
     RECT  11.941 33.28 13.141 34.26 ;
     RECT  13.109 65.536 13.163 69.28 ;
     RECT  12.563 106.816 13.163 106.848 ;
     RECT  13.163 65.536 13.187 68.384 ;
     RECT  12.853 81.996 13.187 84.512 ;
     RECT  12.597 98.196 13.187 99.808 ;
     RECT  13.141 33.088 13.227 34.26 ;
     RECT  12.981 111.168 13.237 111.2 ;
     RECT  13.141 8.896 13.291 8.928 ;
     RECT  12.563 103.596 13.301 105.312 ;
     RECT  12.853 92.032 13.355 94.496 ;
     RECT  13.285 96.128 13.355 96.16 ;
     RECT  13.301 103.168 13.355 105.312 ;
     RECT  9.131 76.596 13.429 77.46 ;
     RECT  12.971 0.996 13.621 3.808 ;
     RECT  12.995 21.056 13.621 21.152 ;
     RECT  13.114 38.796 13.621 39.66 ;
     RECT  9.635 87.396 13.621 88.26 ;
     RECT  13.187 65.536 13.715 66.66 ;
     RECT  13.493 96.32 13.715 96.352 ;
     RECT  13.237 111.168 13.715 112.352 ;
     RECT  9.579 22.596 13.742 23.46 ;
     RECT  13.742 22.596 13.765 23.968 ;
     RECT  13.621 21.056 13.803 21.216 ;
     RECT  12.179 27.996 13.813 28.86 ;
     RECT  11.459 114.396 13.813 115.26 ;
     RECT  13.765 22.596 13.867 24.288 ;
     RECT  13.355 92.032 13.955 93.66 ;
     RECT  12.659 30.72 13.995 30.752 ;
     RECT  13.045 108.8 14.059 109.86 ;
     RECT  13.813 113.088 14.059 115.26 ;
     RECT  13.621 87.396 14.069 88.992 ;
     RECT  13.715 111.232 14.099 111.264 ;
     RECT  13.429 76.596 14.133 78.688 ;
     RECT  13.187 98.196 14.197 99.06 ;
     RECT  14.069 87.232 14.261 88.992 ;
     RECT  14.133 76.596 14.291 79.264 ;
     RECT  9.451 11.796 14.325 12.66 ;
     RECT  14.261 57.6 14.339 57.632 ;
     RECT  0 49.596 14.374 50.46 ;
     RECT  14.293 15.04 14.379 15.072 ;
     RECT  14.291 76.596 14.379 78.048 ;
     RECT  14.293 80.192 14.379 80.224 ;
     RECT  14.325 20.736 14.398 20.768 ;
     RECT  13.621 0.996 14.437 4 ;
     RECT  13.813 26.816 14.437 28.86 ;
     RECT  13.621 38.592 14.443 39.66 ;
     RECT  14.437 26.24 14.507 28.86 ;
     RECT  13.139 71.196 14.517 72.06 ;
     RECT  13.139 73.472 14.517 73.504 ;
     RECT  13.355 103.168 14.517 104.46 ;
     RECT  14.437 0.192 14.571 4 ;
     RECT  14.149 91.136 14.571 91.168 ;
     RECT  14.374 48.384 14.581 50.46 ;
     RECT  13.045 51.904 14.581 52.064 ;
     RECT  12.843 54.996 14.675 56.288 ;
     RECT  14.581 48.384 14.699 52.064 ;
     RECT  14.325 11.648 14.754 12.66 ;
     RECT  14.699 51.904 14.763 52.064 ;
     RECT  0 6.396 14.773 7.26 ;
     RECT  14.261 87.232 14.819 89.696 ;
     RECT  14.754 11.328 14.827 12.66 ;
     RECT  14.507 26.816 14.867 28.86 ;
     RECT  14.763 51.904 14.867 51.936 ;
     RECT  14.517 71.196 14.867 73.504 ;
     RECT  14.819 87.232 14.867 88.416 ;
     RECT  13.557 100.352 14.867 100.384 ;
     RECT  14.517 102.016 14.867 104.46 ;
     RECT  15.061 53.504 15.147 53.536 ;
     RECT  14.867 26.88 15.155 28.86 ;
     RECT  14.571 0.192 15.226 3.424 ;
     RECT  14.773 58.752 15.275 58.784 ;
     RECT  13.227 33.396 15.349 34.26 ;
     RECT  15.221 30.208 15.443 30.24 ;
     RECT  15.349 32.512 15.443 34.26 ;
     RECT  14.867 71.196 15.443 72.224 ;
     RECT  14.867 87.396 15.443 88.416 ;
     RECT  14.699 48.448 15.467 50.46 ;
     RECT  14.773 6.396 15.587 8.544 ;
     RECT  15.226 0.192 15.659 2.848 ;
     RECT  13.187 81.996 15.669 82.86 ;
     RECT  15.659 0.996 15.723 2.848 ;
     RECT  15.669 81.996 15.733 83.104 ;
     RECT  13.187 84.48 15.733 84.512 ;
     RECT  15.733 81.996 15.787 84.512 ;
     RECT  15.787 81.996 15.915 83.68 ;
     RECT  14.059 114.24 15.925 115.26 ;
     RECT  15.861 80.192 15.934 80.224 ;
     RECT  15.925 114.24 15.994 115.424 ;
     RECT  14.005 41.664 16.019 41.696 ;
     RECT  10.485 46.464 16.019 46.496 ;
     RECT  12.907 62.72 16.019 62.752 ;
     RECT  13.187 68.352 16.019 68.384 ;
     RECT  14.379 76.596 16.019 77.856 ;
     RECT  15.915 81.996 16.019 83.104 ;
     RECT  14.059 108.996 16.245 109.86 ;
     RECT  14.197 97.664 16.29 99.06 ;
     RECT  13.955 92.796 16.309 93.66 ;
     RECT  14.867 102.336 16.309 104.46 ;
     RECT  16.245 31.552 16.355 31.584 ;
     RECT  14.675 54.996 16.355 56.224 ;
     RECT  16.29 97.664 16.363 99.36 ;
     RECT  16.309 102.016 16.363 105.44 ;
     RECT  15.723 0.996 16.427 2.784 ;
     RECT  16.309 91.776 16.427 93.66 ;
     RECT  16.363 103.488 16.491 105.44 ;
     RECT  15.155 27.328 16.555 28.86 ;
     RECT  16.427 0.996 16.56 1.86 ;
     RECT  15.587 6.396 16.56 7.26 ;
     RECT  14.827 11.796 16.56 12.66 ;
     RECT  11.563 17.196 16.56 18.06 ;
     RECT  13.867 22.596 16.56 23.46 ;
     RECT  16.555 27.996 16.56 28.86 ;
     RECT  15.443 33.396 16.56 34.26 ;
     RECT  14.443 38.796 16.56 39.66 ;
     RECT  0 44.196 16.56 45.06 ;
     RECT  15.467 49.596 16.56 50.46 ;
     RECT  16.355 54.996 16.56 55.86 ;
     RECT  12.907 60.396 16.56 61.26 ;
     RECT  13.715 65.796 16.56 66.66 ;
     RECT  15.443 71.196 16.56 72.06 ;
     RECT  16.019 76.596 16.56 77.46 ;
     RECT  16.019 81.996 16.56 82.976 ;
     RECT  15.443 87.396 16.56 88.26 ;
     RECT  16.427 92.796 16.56 93.66 ;
     RECT  16.491 103.596 16.56 104.608 ;
     RECT  15.413 36.48 16.883 36.512 ;
     RECT  16.363 102.016 16.883 102.048 ;
     RECT  16.363 97.664 16.939 99.06 ;
     RECT  16.56 92.864 16.954 93.66 ;
     RECT  16.56 104.172 17.123 104.608 ;
     RECT  16.245 108.288 17.123 109.86 ;
     RECT  15.994 114.24 17.123 115.26 ;
     RECT  16.56 1.572 17.344 1.86 ;
     RECT  16.56 6.972 17.344 7.26 ;
     RECT  16.56 12.372 17.344 12.66 ;
     RECT  16.56 17.772 17.344 18.06 ;
     RECT  16.56 23.172 17.344 23.46 ;
     RECT  16.56 28.572 17.344 28.86 ;
     RECT  16.56 33.972 17.344 34.26 ;
     RECT  16.56 39.372 17.344 39.66 ;
     RECT  16.56 44.772 17.344 45.06 ;
     RECT  16.56 50.172 17.344 50.46 ;
     RECT  16.56 55.572 17.344 55.86 ;
     RECT  16.56 60.972 17.344 61.26 ;
     RECT  16.56 66.372 17.344 66.66 ;
     RECT  16.56 71.772 17.344 72.06 ;
     RECT  16.56 77.172 17.344 77.46 ;
     RECT  16.56 82.572 17.344 82.976 ;
     RECT  16.56 87.972 17.344 88.26 ;
     RECT  16.954 93.372 17.344 93.66 ;
     RECT  16.939 98.772 17.344 99.06 ;
     RECT  17.123 104.172 17.344 104.46 ;
     RECT  17.123 109.572 17.344 109.86 ;
     RECT  17.123 114.972 17.344 115.26 ;
     RECT  16.885 95.232 17.363 95.264 ;
     RECT  17.344 82.944 17.699 82.976 ;
     RECT  11.189 118.592 18.419 118.624 ;
    LAYER M7 ;
     RECT  4.096 0.181 12.96 1.397 ;
     RECT  14.464 0.181 15.648 1.397 ;
     RECT  4.096 1.397 15.648 2.677 ;
     RECT  17.056 0.531 17.344 2.677 ;
     RECT  3.904 2.677 17.344 88.427 ;
     RECT  3.904 88.427 14.496 89.771 ;
     RECT  11.008 89.771 14.496 91.125 ;
     RECT  3.904 89.771 9.632 100.395 ;
     RECT  4.416 100.395 9.632 100.971 ;
     RECT  11.008 91.125 14.56 102.059 ;
     RECT  4.608 100.971 9.632 107.819 ;
     RECT  16.256 88.427 17.344 109.429 ;
     RECT  5.248 107.819 9.632 110.059 ;
     RECT  5.248 110.059 6.688 110.827 ;
     RECT  11.008 102.059 14.496 111.211 ;
     RECT  13.248 111.211 14.496 112.363 ;
     RECT  14.016 112.363 14.496 113.131 ;
     RECT  8.192 110.059 9.632 113.515 ;
     RECT  11.008 111.211 11.944 113.515 ;
     RECT  8.768 113.515 9.632 114.027 ;
     RECT  14.464 113.131 14.496 114.283 ;
     RECT  6.256 110.827 6.688 114.859 ;
     RECT  8.768 114.027 8.8 114.859 ;
     RECT  15.936 109.429 17.344 115.435 ;
     RECT  0.856 0.531 1.144 117.999 ;
     RECT  6.256 114.859 6.544 117.999 ;
     RECT  11.2 113.515 11.944 117.999 ;
     RECT  17.056 115.435 17.344 117.999 ;
     RECT  11.2 117.999 11.232 118.635 ;
  END
END hfd_stn_r16
END LIBRARY
